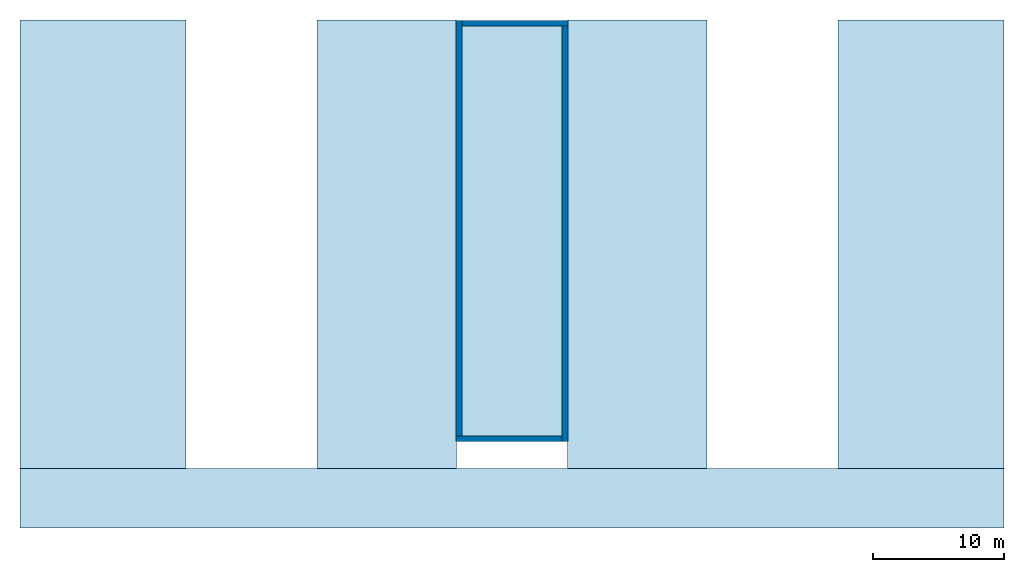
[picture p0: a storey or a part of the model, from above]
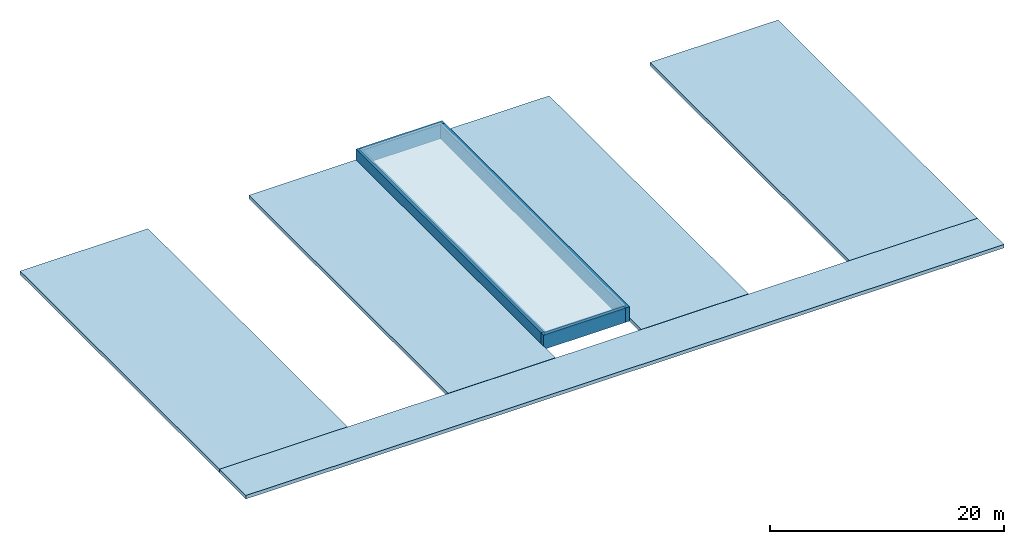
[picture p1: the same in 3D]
Properties of the parts of a building model (IFC2X3), part 1 of 3

# File
Description: ViewDefinition [CoordinationView_V2.0]
File name: Project Number
Time: 2020-09-23T11:52:34
Written by: The EXPRESS Data Manager Version 5.02.0100.07 : 28 Aug 2013
Made in: 21.0.0.383 - Exporter 21.0.0.383 - Alternate UI 21.0.0.383
Comment: STEP Physical File produced by: The EXPRESS Data Manager Version 5.02.0100.07 : 28 Aug 2013 * Module: EDMstepFileFactory/EDMstandAlone * Creation date: Wed Sep 23 11:52:34 2020 * Host: DESKTOP-DG8BND5 * Database: C:\Users\X\AppData\Local\Temp\ed47b6ea-077b-444b-8792-7ce0966b8367\b25919d0-d5f9-47cf-bf8c-4464f070ef61\ifc * Database version: 5507 * Database creation date: Wed Sep 23 11:42:41 2020 * Schema: IFC2X3 * Model: DataRepository.ifc * Model creation date: Wed Sep 23 11:42:42 2020 * Header model: DataRepository.ifc_HeaderModel * Header model creation date: Wed Sep 23 11:42:42 2020 * EDMuser: sdai-user * EDMgroup: sdai-group * License ID and type: 5605 : Permanent license. Expiry date: * EDMstepFileFactory options: 020000

# IfcProject, Project Number
LongName: Project Name; Phase: Project Status

# IfcSite, Default
RefLatitude: 48, 41, 46, 352233; RefLongitude: 6, 11, 34, 519615; RefElevation: 0 mm
Pset_ProductRequirements - Category: Project Information
Other - Category: Project Information; Client Name: Owner; Project Address: Enter address here; Project Issue Date: Issue Date; Project Name: Project Name; Project Number: Project Number; Project Status: Project Status

# IfcBuilding
Pset_BuildingCommon - NumberOfStoreys: 5
Pset_ProductRequirements - Category: Project Information
Other - Category: Project Information; Client Name: Owner; Project Address: Enter address here; Project Issue Date: Issue Date; Project Name: Project Name; Project Number: Project Number; Project Status: Project Status

# IfcBuildingStorey: Level:Circle Head - Project Datum (5)
Other(Type) - Category: Levels; Family Name: Level
Identity Data(Type) - Type Name: Circle Head - Project Datum
Graphics(Type) - Color: 0; Line Pattern: Centre; Line Weight: 1; Symbol: Anno_Level_Head_Circle: Standard; Symbol at End 1 Default: yes; Symbol at End 2 Default: no
Constraints(Type) - Elevation Base: Project Base Point
Pset_ProductRequirements - Category: Levels
Dimensions - Computation Height: 0 mm
Identity Data - Building Story: yes
Other - Category: Levels; Family: Level: Circle Head - Project Datum; Family and Type: Level: Circle Head - Project Datum; Type: Level: Circle Head - Project Datum; Type Id: Level: Circle Head - Project Datum
Name | LongName = Pset_AirSideSystemInformation, Name = Pset_ProductRequirements, Name = Identity Data, Name | Elevation (mm) = Constraints, Elevation (mm) | Structural
R-1 | R-1 | -3500 | yes
RDC | RDC | 0 | no
R+1 | R+1 | 3660 | no
R+2 | R+2 | 7320 | no
TOP | TOP | 11230 | no

# IfcBeam: M_Concrete-Rectangular Beam:200x300 mm, M_Concrete-Rectangular Beam:200x300 mm:497822
In: R-1
Type - Dimensions - b: 200 mm; h: 300 mm
Type - Identity Data - OmniClass Number: 23.25.30.11.14.14; OmniClass Title: Beams; Type Name: 200x300 mm
Type - Other - Category: Structural Framing; Family Name: M_Concrete-Rectangular Beam
Type - Structural - Section Shape: 0
Type - Pset_BeamCommon - IsExternal: no; LoadBearing: yes; Reference: 200x300 mm
Type - Pset_ProductRequirements - Category: Structural Framing
Type - Pset_QuantityTakeOff - Reference: 200x300 mm
Type - Pset_ReinforcementBarPitchOfBeam - Reference: 200x300 mm
Material: Concrete, Cast-in-Place gray
Pset_BeamCommon - Slope: 0 deg; Span: 1739.96 mm
Pset_QuantityTakeOff - sets with these values: 2
Constraints - Cross-Section Rotation: 0 deg; End Level Offset: 2330 mm; Reference Level: Level: R-1; Reference Level Elevation: -3500 mm; Start Level Offset: 2330 mm
Dimensions - Elevation at Bottom: -1470 mm; Elevation at Top: -1170 mm; Length: 1739.96 mm; Volume: 0.0989977 m3
Geometric Position - Join Status: Both joins enabled; y Justification: Origin; y Offset Value: 0 mm; yz Justification: Uniform; z Justification: Top; z Offset Value: 0 mm
Materials and Finishes - Structural Material: Concrete, Cast-in-Place gray
Other - Family: M_Concrete-Rectangular Beam: 200x300 mm; Family and Type: M_Concrete-Rectangular Beam: 200x300 mm; Type: M_Concrete-Rectangular Beam: 200x300 mm; Type Id: M_Concrete-Rectangular Beam: 200x300 mm
Phasing - Phase Created: New Construction
Structural - Enable Analytical Model: yes; Rebar Cover - Bottom Face: Rebar Cover Settings: Rebar Cover 1; Rebar Cover - Other Faces: Rebar Cover Settings: Rebar Cover 1; Rebar Cover - Top Face: Rebar Cover Settings: Rebar Cover 1; Cut Length: 1649.96 mm; Structural Usage: Secondary

# IfcBeam: M_Concrete-Rectangular Beam:400 x 800mm, M_Concrete-Rectangular Beam:400 x 800mm:545684
In: R+1
Type - PredefinedType: BEAM; Material: Concrete, Precast Smooth, Light Grey
Type - Dimensions - b: 430 mm; h: 430 mm
Type - Identity Data - OmniClass Number: 23.25.30.11.14.14; OmniClass Title: Beams; Type Name: 400 x 800mm
Type - Other - Category: Structural Framing; Family Name: M_Concrete-Rectangular Beam
Type - Structural - Section Shape: 0
Type - Pset_BeamCommon - IsExternal: no; LoadBearing: yes; Reference: 400 x 800mm
Type - Pset_ProductRequirements - Category: Structural Framing
Type - Pset_QuantityTakeOff - Reference: 400 x 800mm
Type - Pset_ReinforcementBarPitchOfBeam - Reference: 400 x 800mm
Pset_BeamCommon - Slope: 0 deg; Span: 31640 mm
Pset_QuantityTakeOff - sets with these values: 2
Constraints - Cross-Section Rotation: 0 deg; Reference Level: Level: R+1; End Level Offset: 0 mm; Orientation: Normal; Start Level Offset: 0 mm; Reference Level Elevation: 3660 mm; Work Plane: Level : R+1
Dimensions - Elevation at Bottom: 3230 mm; Elevation at Top: 3660 mm; Length: 31640 mm; Volume: 4.77689 m3
Geometric Position - Join Status: Both joins enabled; y Justification: Origin; y Offset Value: 0 mm; yz Justification: Uniform; z Justification: Top; z Offset Value: 0 mm
Materials and Finishes - Structural Material: Concrete, Precast Smooth, Light Grey
Other - Family: M_Concrete-Rectangular Beam: 400 x 800mm; Family and Type: M_Concrete-Rectangular Beam: 400 x 800mm; Type: M_Concrete-Rectangular Beam: 400 x 800mm; Type Id: M_Concrete-Rectangular Beam: 400 x 800mm
Phasing - Phase Created: Existing
Structural - Enable Analytical Model: yes; Rebar Cover - Bottom Face: Rebar Cover Settings: Rebar Cover 1; Rebar Cover - Other Faces: Rebar Cover Settings: Rebar Cover 1; Rebar Cover - Top Face: Rebar Cover Settings: Rebar Cover 1; Cut Length: 31425 mm; Structural Usage: Other

# IfcBeam: M_Concrete-Rectangular Beam:400 x 800mm (14)
In: R+1
Type - Dimensions - b: 430 mm; h: 430 mm
Type - Identity Data - OmniClass Number: 23.25.30.11.14.14; OmniClass Title: Beams; Type Name: 400 x 800mm
Type - Other - Category: Structural Framing; Family Name: M_Concrete-Rectangular Beam
Type - Structural - Section Shape: 0
Type - Pset_BeamCommon - IsExternal: no; LoadBearing: yes; Reference: 400 x 800mm
Type - Pset_ProductRequirements - Category: Structural Framing
Type - Pset_QuantityTakeOff - Reference: 400 x 800mm
Type - Pset_ReinforcementBarPitchOfBeam - Reference: 400 x 800mm
Material: Concrete, Precast Smooth, Light Grey
Pset_BeamCommon - Slope: 0 deg; Span: 4810 mm
Pset_QuantityTakeOff - sets with these values: 2
Constraints - Cross-Section Rotation: 0 deg; Reference Level: Level: R+1; End Level Offset: 0 mm; Orientation: Normal; Reference Level Elevation: 3660 mm; Start Level Offset: 0 mm; Work Plane: Level : R+1
Dimensions - Elevation at Bottom: 3230 mm; Elevation at Top: 3660 mm; Length: 4810 mm; Volume: 0.805166 m3
Geometric Position - Join Status: Both joins enabled; y Justification: Origin; y Offset Value: 0 mm; yz Justification: Uniform; z Justification: Top; z Offset Value: 0 mm
Materials and Finishes - Structural Material: Concrete, Precast Smooth, Light Grey
Other - Family: M_Concrete-Rectangular Beam: 400 x 800mm; Family and Type: M_Concrete-Rectangular Beam: 400 x 800mm; Type: M_Concrete-Rectangular Beam: 400 x 800mm; Type Id: M_Concrete-Rectangular Beam: 400 x 800mm
Phasing - Phase Created: Existing
Structural - Enable Analytical Model: yes; Rebar Cover - Bottom Face: Rebar Cover Settings: Rebar Cover 1; Rebar Cover - Other Faces: Rebar Cover Settings: Rebar Cover 1; Rebar Cover - Top Face: Rebar Cover Settings: Rebar Cover 1; End Attachment Type: End Elevation; Start Attachment Type: End Elevation; Structural Usage: Primary; Cut Length: 4354.6 mm
Name (M_Concrete-Rectangular Beam:400 x 800mm:...) | Comments
545226 | ThisIsExisting
545328 | ThisIsExisting
545407 | ThisIsExisting
545422 | ThisIsExisting
545442 | ThisIsExisting
545455 | ThisIsExisting
545468 | ThisIsExisting
545483 | ThisIsExisting
545496 | ThisIsExisting
545514 | ThisIsExisting
545534 | ThisIsExisting
545549 | ThisIsExisting
545629
545644

# IfcBeam: Poutre petite:Poutre petite (130)
Type - Identity Data - OmniClass Number: 23.25.30.11.14.14; OmniClass Title: Beams; Type Name: Poutre petite
Type - Other - Category: Structural Framing; Family Name: Poutre petite
Type - Structural - Section Shape: 0
Type - Pset_BeamCommon - IsExternal: no; LoadBearing: yes; Reference: Poutre petite
Type - Pset_ProductRequirements - Category: Structural Framing
Type - Pset_QuantityTakeOff - Reference: Poutre petite
Type - Pset_ReinforcementBarPitchOfBeam - Reference: Poutre petite
Material: Concrete, Precast Smooth, Light Grey
Pset_BeamCommon - Slope: 0 deg; Span: 2260 mm
Pset_QuantityTakeOff - sets with these values: 2
Constraints - Cross-Section Rotation: 0 deg; End Level Offset: 3530 mm; Start Level Offset: 3530 mm
Dimensions - Length: 2260 mm; Volume: 0.65021 m3
Geometric Position - End Extension: 0 mm; Join Status: Both joins enabled; Start Extension: 0 mm; y Justification: Origin; y Offset Value: 0 mm; yz Justification: Uniform; z Justification: Top; z Offset Value: 0 mm
Identity Data - Comments: ThisIsExisting
Materials and Finishes - Structural Material: Concrete - Precast Concrete
Other - Family: Poutre petite: Poutre petite; Family and Type: Poutre petite: Poutre petite; Type: Poutre petite: Poutre petite; Type Id: Poutre petite: Poutre petite
Phasing - Phase Created: Existing
Structural - Enable Analytical Model: yes; Rebar Cover - Bottom Face: Rebar Cover Settings: Rebar Cover 1; Rebar Cover - Other Faces: Rebar Cover Settings: Rebar Cover 1; Rebar Cover - Top Face: Rebar Cover Settings: Rebar Cover 1; Structural Usage: Primary; Cut Length: 2260 mm
Name (Poutre petite:Poutre petite:...) | In | Reference Level | Reference Level Elevation (mm) | Elevation at Bottom (mm) | Elevation at Top (mm) | Start Join Cutback (mm) | End Join Cutback (mm)
562425 | R+2 | Level: R+2 | 7320 | 10280 | 10850 | 12.7
562955 | R+2 | Level: R+2 | 7320 | 10280 | 10850 | 12.7 | 12.7
562975 | R+2 | Level: R+2 | 7320 | 10280 | 10850 | 12.7 | 12.7
562979 | R+2 | Level: R+2 | 7320 | 10280 | 10850 | 12.7 | 12.7
562983 | R+2 | Level: R+2 | 7320 | 10280 | 10850 | 12.7 | 12.7
562987 | R+2 | Level: R+2 | 7320 | 10280 | 10850 | 12.7 | 12.7
562991 | R+2 | Level: R+2 | 7320 | 10280 | 10850 | 12.7 | 12.7
562995 | R+2 | Level: R+2 | 7320 | 10280 | 10850 | 12.7 | 12.7
562999 | R+2 | Level: R+2 | 7320 | 10280 | 10850 | 12.7 | 12.7
563003 | R+2 | Level: R+2 | 7320 | 10280 | 10850 | 12.7 | 12.7
563007 | R+2 | Level: R+2 | 7320 | 10280 | 10850 | 12.7 | 12.7
563011 | R+2 | Level: R+2 | 7320 | 10280 | 10850 | 12.7 | 12.7
563015 | R+2 | Level: R+2 | 7320 | 10280 | 10850 | 12.7 | 12.7
563019 | R+2 | Level: R+2 | 7320 | 10280 | 10850 | 12.7 | 12.7
563023 | R+2 | Level: R+2 | 7320 | 10280 | 10850 | 12.7 | 12.7
563027 | R+2 | Level: R+2 | 7320 | 10280 | 10850 | 12.7 | 12.7
563031 | R+2 | Level: R+2 | 7320 | 10280 | 10850 |  | 12.7
563098 | R+2 | Level: R+2 | 7320 | 10280 | 10850 | 12.7
563100 | R+2 | Level: R+2 | 7320 | 10280 | 10850 | 12.7 | 12.7
563102 | R+2 | Level: R+2 | 7320 | 10280 | 10850 | 12.7 | 12.7
563104 | R+2 | Level: R+2 | 7320 | 10280 | 10850 | 12.7 | 12.7
563106 | R+2 | Level: R+2 | 7320 | 10280 | 10850 | 12.7 | 12.7
563108 | R+2 | Level: R+2 | 7320 | 10280 | 10850 | 12.7 | 12.7
563110 | R+2 | Level: R+2 | 7320 | 10280 | 10850 | 12.7 | 12.7
563112 | R+2 | Level: R+2 | 7320 | 10280 | 10850 | 12.7 | 12.7
563114 | R+2 | Level: R+2 | 7320 | 10280 | 10850 | 12.7 | 12.7
563116 | R+2 | Level: R+2 | 7320 | 10280 | 10850 | 12.7 | 12.7
563118 | R+2 | Level: R+2 | 7320 | 10280 | 10850 | 12.7 | 12.7
563120 | R+2 | Level: R+2 | 7320 | 10280 | 10850 | 12.7 | 12.7
563122 | R+2 | Level: R+2 | 7320 | 10280 | 10850 | 12.7 | 12.7
563124 | R+2 | Level: R+2 | 7320 | 10280 | 10850 | 12.7 | 12.7
563126 | R+2 | Level: R+2 | 7320 | 10280 | 10850 | 12.7 | 12.7
563128 | R+2 | Level: R+2 | 7320 | 10280 | 10850 | 12.7 | 12.7
563130 | R+2 | Level: R+2 | 7320 | 10280 | 10850 |  | 12.7
563202 | RDC | Level: RDC | 0 | 2960 | 3530 | 12.7
563204 | RDC | Level: RDC | 0 | 2960 | 3530 | 12.7 | 12.7
563206 | RDC | Level: RDC | 0 | 2960 | 3530 | 12.7 | 12.7
563208 | RDC | Level: RDC | 0 | 2960 | 3530 | 12.7 | 12.7
563210 | RDC | Level: RDC | 0 | 2960 | 3530 | 12.7 | 12.7
563212 | RDC | Level: RDC | 0 | 2960 | 3530 | 12.7 | 12.7
563214 | RDC | Level: RDC | 0 | 2960 | 3530 | 12.7 | 12.7
563216 | RDC | Level: RDC | 0 | 2960 | 3530 | 12.7 | 12.7
563218 | RDC | Level: RDC | 0 | 2960 | 3530 | 12.7 | 12.7
563220 | RDC | Level: RDC | 0 | 2960 | 3530 | 12.7 | 12.7
563222 | RDC | Level: RDC | 0 | 2960 | 3530 | 12.7 | 12.7
563224 | RDC | Level: RDC | 0 | 2960 | 3530 | 12.7 | 12.7
563226 | RDC | Level: RDC | 0 | 2960 | 3530 | 12.7 | 12.7
563228 | RDC | Level: RDC | 0 | 2960 | 3530 | 12.7 | 12.7
563230 | RDC | Level: RDC | 0 | 2960 | 3530 | 12.7 | 12.7
563232 | RDC | Level: RDC | 0 | 2960 | 3530 | 12.7 | 12.7
563234 | RDC | Level: RDC | 0 | 2960 | 3530 | 12.7 | 12.7
563236 | RDC | Level: RDC | 0 | 2960 | 3530 | 12.7
563238 | RDC | Level: RDC | 0 | 2960 | 3530 | 12.7 | 12.7
563240 | RDC | Level: RDC | 0 | 2960 | 3530 | 12.7 | 12.7
563242 | RDC | Level: RDC | 0 | 2960 | 3530 | 12.7 | 12.7
563244 | RDC | Level: RDC | 0 | 2960 | 3530 | 12.7 | 12.7
563246 | RDC | Level: RDC | 0 | 2960 | 3530 | 12.7 | 12.7
563248 | RDC | Level: RDC | 0 | 2960 | 3530 | 12.7 | 12.7
563250 | RDC | Level: RDC | 0 | 2960 | 3530 | 12.7 | 12.7
563252 | RDC | Level: RDC | 0 | 2960 | 3530 | 12.7 | 12.7
563254 | RDC | Level: RDC | 0 | 2960 | 3530 | 12.7 | 12.7
563256 | RDC | Level: RDC | 0 | 2960 | 3530 | 12.7 | 12.7
563258 | RDC | Level: RDC | 0 | 2960 | 3530 | 12.7 | 12.7
563260 | RDC | Level: RDC | 0 | 2960 | 3530 | 12.7 | 12.7
563262 | RDC | Level: RDC | 0 | 2960 | 3530 | 12.7 | 12.7
563264 | RDC | Level: RDC | 0 | 2960 | 3530 | 12.7 | 12.7
563266 | RDC | Level: RDC | 0 | 2960 | 3530 | 12.7 | 12.7
563268 | RDC | Level: RDC | 0 | 2960 | 3530 |  | 12.7
563583 | R+1 | Level: R+1 | 3660 | 6620 | 7190 | 12.7
563585 | R+1 | Level: R+1 | 3660 | 6620 | 7190 | 12.7 | 12.7
563587 | R+1 | Level: R+1 | 3660 | 6620 | 7190 | 12.7 | 12.7
563589 | R+1 | Level: R+1 | 3660 | 6620 | 7190 | 12.7 | 12.7
563591 | R+1 | Level: R+1 | 3660 | 6620 | 7190 | 12.7 | 12.7
563593 | R+1 | Level: R+1 | 3660 | 6620 | 7190 | 12.7 | 12.7
563595 | R+1 | Level: R+1 | 3660 | 6620 | 7190 | 12.7 | 12.7
563597 | R+1 | Level: R+1 | 3660 | 6620 | 7190 | 12.7 | 12.7
563599 | R+1 | Level: R+1 | 3660 | 6620 | 7190 | 12.7 | 12.7
563601 | R+1 | Level: R+1 | 3660 | 6620 | 7190 | 12.7 | 12.7
563603 | R+1 | Level: R+1 | 3660 | 6620 | 7190 | 12.7 | 12.7
563605 | R+1 | Level: R+1 | 3660 | 6620 | 7190 | 12.7 | 12.7
563607 | R+1 | Level: R+1 | 3660 | 6620 | 7190 | 12.7 | 12.7
563609 | R+1 | Level: R+1 | 3660 | 6620 | 7190 | 12.7 | 12.7
563611 | R+1 | Level: R+1 | 3660 | 6620 | 7190 | 12.7 | 12.7
563613 | R+1 | Level: R+1 | 3660 | 6620 | 7190 | 12.7 | 12.7
563615 | R+1 | Level: R+1 | 3660 | 6620 | 7190 |  | 12.7
563617 | R+1 | Level: R+1 | 3660 | 6620 | 7190 | 12.7
563619 | R+1 | Level: R+1 | 3660 | 6620 | 7190 | 12.7 | 12.7
563621 | R+1 | Level: R+1 | 3660 | 6620 | 7190 | 12.7 | 12.7
563623 | R+1 | Level: R+1 | 3660 | 6620 | 7190 | 12.7 | 12.7
563625 | R+1 | Level: R+1 | 3660 | 6620 | 7190 | 12.7 | 12.7
563627 | R+1 | Level: R+1 | 3660 | 6620 | 7190 | 12.7 | 12.7
563629 | R+1 | Level: R+1 | 3660 | 6620 | 7190 | 12.7 | 12.7
563631 | R+1 | Level: R+1 | 3660 | 6620 | 7190 | 12.7 | 12.7
563633 | R+1 | Level: R+1 | 3660 | 6620 | 7190 | 12.7 | 12.7
563635 | R+1 | Level: R+1 | 3660 | 6620 | 7190 | 12.7 | 12.7
563637 | R+1 | Level: R+1 | 3660 | 6620 | 7190 | 12.7 | 12.7
563639 | R+1 | Level: R+1 | 3660 | 6620 | 7190 | 12.7 | 12.7
563641 | R+1 | Level: R+1 | 3660 | 6620 | 7190 | 12.7 | 12.7
563643 | R+1 | Level: R+1 | 3660 | 6620 | 7190 | 12.7 | 12.7
563645 | R+1 | Level: R+1 | 3660 | 6620 | 7190 | 12.7 | 12.7
563647 | R+1 | Level: R+1 | 3660 | 6620 | 7190 | 12.7 | 12.7
563649 | R+1 | Level: R+1 | 3660 | 6620 | 7190 |  | 12.7
564461 | R+2 | Level: R+2 | 7320 | 10280 | 10850 | 12.7
564463 | R+2 | Level: R+2 | 7320 | 10280 | 10850 | 12.7 | 12.7
564465 | R+2 | Level: R+2 | 7320 | 10280 | 10850 | 12.7 | 12.7
564467 | R+2 | Level: R+2 | 7320 | 10280 | 10850 | 12.7 | 12.7
564469 | R+2 | Level: R+2 | 7320 | 10280 | 10850 | 12.7 | 12.7
564471 | R+2 | Level: R+2 | 7320 | 10280 | 10850 | 12.7 | 12.7
564473 | R+2 | Level: R+2 | 7320 | 10280 | 10850 | 12.7 | 12.7
564475 | R+2 | Level: R+2 | 7320 | 10280 | 10850 | 12.7 | 12.7
564477 | R+2 | Level: R+2 | 7320 | 10280 | 10850 | 12.7 | 12.7
564479 | R+2 | Level: R+2 | 7320 | 10280 | 10850 | 12.7 | 12.7
564481 | R+2 | Level: R+2 | 7320 | 10280 | 10850 | 12.7 | 12.7
564483 | R+2 | Level: R+2 | 7320 | 10280 | 10850 | 12.7 | 12.7
564485 | R+2 | Level: R+2 | 7320 | 10280 | 10850 | 12.7 | 12.7
564487 | R+2 | Level: R+2 | 7320 | 10280 | 10850 |  | 12.7
565113 | R+2 | Level: R+2 | 7320 | 10280 | 10850 | 12.7
565115 | R+2 | Level: R+2 | 7320 | 10280 | 10850 | 12.7 | 12.7
565117 | R+2 | Level: R+2 | 7320 | 10280 | 10850 | 12.7 | 12.7
565119 | R+2 | Level: R+2 | 7320 | 10280 | 10850 | 12.7 | 12.7
565121 | R+2 | Level: R+2 | 7320 | 10280 | 10850 | 12.7 | 12.7
565123 | R+2 | Level: R+2 | 7320 | 10280 | 10850 | 12.7 | 12.7
565125 | R+2 | Level: R+2 | 7320 | 10280 | 10850 | 12.7 | 12.7
565127 | R+2 | Level: R+2 | 7320 | 10280 | 10850 | 12.7 | 12.7
565129 | R+2 | Level: R+2 | 7320 | 10280 | 10850 | 12.7 | 12.7
565131 | R+2 | Level: R+2 | 7320 | 10280 | 10850 | 12.7 | 12.7
565133 | R+2 | Level: R+2 | 7320 | 10280 | 10850 | 12.7 | 12.7
565135 | R+2 | Level: R+2 | 7320 | 10280 | 10850 | 12.7 | 12.7
565137 | R+2 | Level: R+2 | 7320 | 10280 | 10850 | 12.7 | 12.7
565139 | R+2 | Level: R+2 | 7320 | 10280 | 10850 |  | 12.7

# IfcBeam: Poutres:Poutres 2 (215)
Type - PredefinedType: BEAM; Material: Concrete, Precast Smooth, Light Grey
Type - Identity Data - OmniClass Number: 23.25.30.11.14.14; OmniClass Title: Beams; Type Name: Poutres 2
Type - Other - Category: Structural Framing; Family Name: Poutres
Type - Structural - Section Shape: 0
Type - Pset_BeamCommon - IsExternal: no; LoadBearing: yes; Reference: Poutres 2
Type - Pset_ProductRequirements - Category: Structural Framing
Type - Pset_QuantityTakeOff - Reference: Poutres 2
Type - Pset_ReinforcementBarPitchOfBeam - Reference: Poutres 2
Pset_BeamCommon - Span: 10380 mm; Slope: 0 deg
Pset_QuantityTakeOff - sets with these values: 2
Constraints - Cross-Section Rotation: 0 deg; End Level Offset: 3530 mm; Start Level Offset: 3530 mm
Dimensions - Length: 10380 mm; Volume: 5.47672 m3
Geometric Position - End Extension: 0 mm; Join Status: Both joins enabled; Start Extension: 0 mm; y Justification: Origin; y Offset Value: 0 mm; yz Justification: Uniform; z Justification: Top; z Offset Value: 0 mm
Identity Data - Comments: ThisIsExisting
Materials and Finishes - Structural Material: Concrete, Precast Smooth, Light Grey
Other - Family: Poutres: Poutres 2; Family and Type: Poutres: Poutres 2; Type: Poutres: Poutres 2; Type Id: Poutres: Poutres 2
Phasing - Phase Created: Existing
Structural - Enable Analytical Model: yes; Rebar Cover - Bottom Face: Rebar Cover Settings: Rebar Cover 1; Rebar Cover - Other Faces: Rebar Cover Settings: Rebar Cover 1; Rebar Cover - Top Face: Rebar Cover Settings: Rebar Cover 1; Cut Length: 10380 mm; End Attachment Type: End Elevation; Start Attachment Type: End Elevation; Structural Usage: Primary
Name (Poutres:Poutres 2:...) | In | Reference Level | Reference Level Elevation (mm) | Elevation at Bottom (mm) | Elevation at Top (mm) | End Join Cutback (mm) = Start Join Cutback (mm)
442840 | RDC | Level: RDC | 0 | 2960 | 3530 | 12.7
443948 | RDC | Level: RDC | 0 | 2960 | 3530 | 12.7
443968 | RDC | Level: RDC | 0 | 2960 | 3530 | 12.7
443972 | RDC | Level: RDC | 0 | 2960 | 3530 | 12.7
443976 | RDC | Level: RDC | 0 | 2960 | 3530 | 12.7
443980 | RDC | Level: RDC | 0 | 2960 | 3530 | 12.7
443984 | RDC | Level: RDC | 0 | 2960 | 3530 | 12.7
443988 | RDC | Level: RDC | 0 | 2960 | 3530 | 12.7
443992 | RDC | Level: RDC | 0 | 2960 | 3530 | 12.7
443996 | RDC | Level: RDC | 0 | 2960 | 3530 | 12.7
444000 | RDC | Level: RDC | 0 | 2960 | 3530 | 12.7
444004 | RDC | Level: RDC | 0 | 2960 | 3530 | 12.7
444008 | RDC | Level: RDC | 0 | 2960 | 3530 | 12.7
444012 | RDC | Level: RDC | 0 | 2960 | 3530 | 12.7
444016 | RDC | Level: RDC | 0 | 2960 | 3530 | 12.7
444020 | RDC | Level: RDC | 0 | 2960 | 3530 | 12.7
444024 | RDC | Level: RDC | 0 | 2960 | 3530 | 12.7
444092 | R+1 | Level: R+1 | 3660 | 6620 | 7190 | 12.7
444095 | R+1 | Level: R+1 | 3660 | 6620 | 7190 | 12.7
444098 | R+1 | Level: R+1 | 3660 | 6620 | 7190 | 12.7
444101 | R+1 | Level: R+1 | 3660 | 6620 | 7190 | 12.7
444104 | R+1 | Level: R+1 | 3660 | 6620 | 7190 | 12.7
444107 | R+1 | Level: R+1 | 3660 | 6620 | 7190 | 12.7
444110 | R+1 | Level: R+1 | 3660 | 6620 | 7190 | 12.7
444113 | R+1 | Level: R+1 | 3660 | 6620 | 7190 | 12.7
444116 | R+1 | Level: R+1 | 3660 | 6620 | 7190 | 12.7
444119 | R+1 | Level: R+1 | 3660 | 6620 | 7190 | 12.7
444122 | R+1 | Level: R+1 | 3660 | 6620 | 7190 | 12.7
444125 | R+1 | Level: R+1 | 3660 | 6620 | 7190 | 12.7
444128 | R+1 | Level: R+1 | 3660 | 6620 | 7190 | 12.7
444131 | R+1 | Level: R+1 | 3660 | 6620 | 7190 | 12.7
444134 | R+1 | Level: R+1 | 3660 | 6620 | 7190 | 12.7
444137 | R+1 | Level: R+1 | 3660 | 6620 | 7190 | 12.7
444140 | R+1 | Level: R+1 | 3660 | 6620 | 7190 | 12.7
444212 | R+2 | Level: R+2 | 7320 | 10280 | 10850 | 12.7
444215 | R+2 | Level: R+2 | 7320 | 10280 | 10850 | 12.7
444218 | R+2 | Level: R+2 | 7320 | 10280 | 10850 | 12.7
444221 | R+2 | Level: R+2 | 7320 | 10280 | 10850 | 12.7
444224 | R+2 | Level: R+2 | 7320 | 10280 | 10850 | 12.7
444227 | R+2 | Level: R+2 | 7320 | 10280 | 10850 | 12.7
444230 | R+2 | Level: R+2 | 7320 | 10280 | 10850 | 12.7
444233 | R+2 | Level: R+2 | 7320 | 10280 | 10850 | 12.7
444236 | R+2 | Level: R+2 | 7320 | 10280 | 10850 | 12.7
444239 | R+2 | Level: R+2 | 7320 | 10280 | 10850 | 12.7
444242 | R+2 | Level: R+2 | 7320 | 10280 | 10850 | 12.7
444245 | R+2 | Level: R+2 | 7320 | 10280 | 10850 | 12.7
444248 | R+2 | Level: R+2 | 7320 | 10280 | 10850 | 12.7
444251 | R+2 | Level: R+2 | 7320 | 10280 | 10850 | 12.7
444254 | R+2 | Level: R+2 | 7320 | 10280 | 10850 | 12.7
444257 | R+2 | Level: R+2 | 7320 | 10280 | 10850 | 12.7
444260 | R+2 | Level: R+2 | 7320 | 10280 | 10850 | 12.7
448041 | RDC | Level: RDC | 0 | 2960 | 3530 | 12.7
448044 | RDC | Level: RDC | 0 | 2960 | 3530 | 12.7
448051 | RDC | Level: RDC | 0 | 2960 | 3530 | 12.7
448054 | RDC | Level: RDC | 0 | 2960 | 3530 | 12.7
448057 | RDC | Level: RDC | 0 | 2960 | 3530 | 12.7
448060 | RDC | Level: RDC | 0 | 2960 | 3530 | 12.7
448063 | RDC | Level: RDC | 0 | 2960 | 3530 | 12.7
448066 | RDC | Level: RDC | 0 | 2960 | 3530 | 12.7
448069 | RDC | Level: RDC | 0 | 2960 | 3530 | 12.7
448072 | RDC | Level: RDC | 0 | 2960 | 3530 | 12.7
448075 | RDC | Level: RDC | 0 | 2960 | 3530 | 12.7
448078 | RDC | Level: RDC | 0 | 2960 | 3530 | 12.7
448081 | RDC | Level: RDC | 0 | 2960 | 3530 | 12.7
448084 | RDC | Level: RDC | 0 | 2960 | 3530 | 12.7
448087 | RDC | Level: RDC | 0 | 2960 | 3530 | 12.7
448199 | RDC | Level: RDC | 0 | 2960 | 3530 | 12.7
448202 | RDC | Level: RDC | 0 | 2960 | 3530 | 12.7
448209 | RDC | Level: RDC | 0 | 2960 | 3530 | 12.7
448212 | RDC | Level: RDC | 0 | 2960 | 3530 | 12.7
448215 | RDC | Level: RDC | 0 | 2960 | 3530 | 12.7
448218 | RDC | Level: RDC | 0 | 2960 | 3530 | 12.7
448221 | RDC | Level: RDC | 0 | 2960 | 3530 | 12.7
448224 | RDC | Level: RDC | 0 | 2960 | 3530 | 12.7
448227 | RDC | Level: RDC | 0 | 2960 | 3530 | 12.7
448230 | RDC | Level: RDC | 0 | 2960 | 3530 | 12.7
448233 | RDC | Level: RDC | 0 | 2960 | 3530 | 12.7
448236 | RDC | Level: RDC | 0 | 2960 | 3530 | 12.7
448239 | RDC | Level: RDC | 0 | 2960 | 3530 | 12.7
448242 | RDC | Level: RDC | 0 | 2960 | 3530 | 12.7
448245 | RDC | Level: RDC | 0 | 2960 | 3530 | 12.7
448339 | R+1 | Level: R+1 | 3660 | 6620 | 7190 | 12.7
448342 | R+1 | Level: R+1 | 3660 | 6620 | 7190 | 12.7
448345 | R+1 | Level: R+1 | 3660 | 6620 | 7190 | 12.7
448348 | R+1 | Level: R+1 | 3660 | 6620 | 7190 | 12.7
448351 | R+1 | Level: R+1 | 3660 | 6620 | 7190 | 12.7
448354 | R+1 | Level: R+1 | 3660 | 6620 | 7190 | 12.7
448357 | R+1 | Level: R+1 | 3660 | 6620 | 7190 | 12.7
448360 | R+1 | Level: R+1 | 3660 | 6620 | 7190 | 12.7
448363 | R+1 | Level: R+1 | 3660 | 6620 | 7190 | 12.7
448366 | R+1 | Level: R+1 | 3660 | 6620 | 7190 | 12.7
448369 | R+1 | Level: R+1 | 3660 | 6620 | 7190 | 12.7
448372 | R+1 | Level: R+1 | 3660 | 6620 | 7190 | 12.7
448375 | R+1 | Level: R+1 | 3660 | 6620 | 7190 | 12.7
448378 | R+1 | Level: R+1 | 3660 | 6620 | 7190 | 12.7
448381 | R+1 | Level: R+1 | 3660 | 6620 | 7190 | 12.7
448591 | R+2 | Level: R+2 | 7320 | 10280 | 10850 | 12.7
448594 | R+2 | Level: R+2 | 7320 | 10280 | 10850 | 12.7
448597 | R+2 | Level: R+2 | 7320 | 10280 | 10850 | 12.7
448600 | R+2 | Level: R+2 | 7320 | 10280 | 10850 | 12.7
448603 | R+2 | Level: R+2 | 7320 | 10280 | 10850 | 12.7
448606 | R+2 | Level: R+2 | 7320 | 10280 | 10850 | 12.7
448609 | R+2 | Level: R+2 | 7320 | 10280 | 10850 | 12.7
448612 | R+2 | Level: R+2 | 7320 | 10280 | 10850 | 12.7
448615 | R+2 | Level: R+2 | 7320 | 10280 | 10850 | 12.7
448618 | R+2 | Level: R+2 | 7320 | 10280 | 10850 | 12.7
448621 | R+2 | Level: R+2 | 7320 | 10280 | 10850 | 12.7
448624 | R+2 | Level: R+2 | 7320 | 10280 | 10850 | 12.7
448627 | R+2 | Level: R+2 | 7320 | 10280 | 10850 | 12.7
448630 | R+2 | Level: R+2 | 7320 | 10280 | 10850 | 12.7
448633 | R+2 | Level: R+2 | 7320 | 10280 | 10850 | 12.7
487352 | RDC | Level: RDC | 0 | 2960 | 3530 | 12.7
487355 | RDC | Level: RDC | 0 | 2960 | 3530 | 12.7
487358 | RDC | Level: RDC | 0 | 2960 | 3530 | 12.7
487361 | RDC | Level: RDC | 0 | 2960 | 3530 | 12.7
487364 | RDC | Level: RDC | 0 | 2960 | 3530 | 12.7
487367 | RDC | Level: RDC | 0 | 2960 | 3530 | 12.7
487370 | RDC | Level: RDC | 0 | 2960 | 3530 | 12.7
487373 | RDC | Level: RDC | 0 | 2960 | 3530 | 12.7
487376 | RDC | Level: RDC | 0 | 2960 | 3530 | 12.7
487379 | RDC | Level: RDC | 0 | 2960 | 3530 | 12.7
487382 | RDC | Level: RDC | 0 | 2960 | 3530 | 12.7
487385 | RDC | Level: RDC | 0 | 2960 | 3530 | 12.7
487388 | RDC | Level: RDC | 0 | 2960 | 3530 | 12.7
487391 | RDC | Level: RDC | 0 | 2960 | 3530 | 12.7
487394 | RDC | Level: RDC | 0 | 2960 | 3530 | 12.7
487397 | RDC | Level: RDC | 0 | 2960 | 3530 | 12.7
487406 | R+2 | Level: R+2 | 7320 | 10280 | 10850 | 12.7
487409 | R+2 | Level: R+2 | 7320 | 10280 | 10850 | 12.7
487412 | R+2 | Level: R+2 | 7320 | 10280 | 10850 | 12.7
487415 | R+2 | Level: R+2 | 7320 | 10280 | 10850 | 12.7
487418 | R+2 | Level: R+2 | 7320 | 10280 | 10850 | 12.7
487421 | R+2 | Level: R+2 | 7320 | 10280 | 10850 | 12.7
487424 | R+2 | Level: R+2 | 7320 | 10280 | 10850 | 12.7
487427 | R+2 | Level: R+2 | 7320 | 10280 | 10850 | 12.7
487430 | R+2 | Level: R+2 | 7320 | 10280 | 10850 | 12.7
487433 | R+2 | Level: R+2 | 7320 | 10280 | 10850 | 12.7
487436 | R+2 | Level: R+2 | 7320 | 10280 | 10850 | 12.7
487439 | R+2 | Level: R+2 | 7320 | 10280 | 10850 | 12.7
487442 | R+2 | Level: R+2 | 7320 | 10280 | 10850 | 12.7
487445 | R+2 | Level: R+2 | 7320 | 10280 | 10850 | 12.7
487448 | R+2 | Level: R+2 | 7320 | 10280 | 10850 | 12.7
487451 | R+2 | Level: R+2 | 7320 | 10280 | 10850 | 12.7
487457 | RDC | Level: RDC | 0 | 2960 | 3530 | 12.7
487460 | RDC | Level: RDC | 0 | 2960 | 3530 | 12.7
487463 | RDC | Level: RDC | 0 | 2960 | 3530 | 12.7
487466 | RDC | Level: RDC | 0 | 2960 | 3530 | 12.7
487469 | RDC | Level: RDC | 0 | 2960 | 3530 | 12.7
487472 | RDC | Level: RDC | 0 | 2960 | 3530 | 12.7
487475 | RDC | Level: RDC | 0 | 2960 | 3530 | 12.7
487478 | RDC | Level: RDC | 0 | 2960 | 3530 | 12.7
487481 | RDC | Level: RDC | 0 | 2960 | 3530 | 12.7
487484 | RDC | Level: RDC | 0 | 2960 | 3530 | 12.7
487487 | RDC | Level: RDC | 0 | 2960 | 3530 | 12.7
487490 | RDC | Level: RDC | 0 | 2960 | 3530 | 12.7
487493 | RDC | Level: RDC | 0 | 2960 | 3530 | 12.7
487496 | RDC | Level: RDC | 0 | 2960 | 3530 | 12.7
487502 | RDC | Level: RDC | 0 | 2960 | 3530 | 12.7
487505 | RDC | Level: RDC | 0 | 2960 | 3530 | 12.7
487508 | RDC | Level: RDC | 0 | 2960 | 3530 | 12.7
487511 | RDC | Level: RDC | 0 | 2960 | 3530 | 12.7
487514 | RDC | Level: RDC | 0 | 2960 | 3530 | 12.7
487517 | RDC | Level: RDC | 0 | 2960 | 3530 | 12.7
487520 | RDC | Level: RDC | 0 | 2960 | 3530 | 12.7
487523 | RDC | Level: RDC | 0 | 2960 | 3530 | 12.7
487526 | RDC | Level: RDC | 0 | 2960 | 3530 | 12.7
487529 | RDC | Level: RDC | 0 | 2960 | 3530 | 12.7
487532 | RDC | Level: RDC | 0 | 2960 | 3530 | 12.7
487535 | RDC | Level: RDC | 0 | 2960 | 3530 | 12.7
487538 | RDC | Level: RDC | 0 | 2960 | 3530 | 12.7
487541 | RDC | Level: RDC | 0 | 2960 | 3530 | 12.7
487547 | R+1 | Level: R+1 | 3660 | 6620 | 7190 | 12.7
487550 | R+1 | Level: R+1 | 3660 | 6620 | 7190 | 12.7
487553 | R+1 | Level: R+1 | 3660 | 6620 | 7190 | 12.7
487556 | R+1 | Level: R+1 | 3660 | 6620 | 7190 | 12.7
487559 | R+1 | Level: R+1 | 3660 | 6620 | 7190 | 12.7
487562 | R+1 | Level: R+1 | 3660 | 6620 | 7190 | 12.7
487565 | R+1 | Level: R+1 | 3660 | 6620 | 7190 | 12.7
487568 | R+1 | Level: R+1 | 3660 | 6620 | 7190 | 12.7
487571 | R+1 | Level: R+1 | 3660 | 6620 | 7190 | 12.7
487574 | R+1 | Level: R+1 | 3660 | 6620 | 7190 | 12.7
487577 | R+1 | Level: R+1 | 3660 | 6620 | 7190 | 12.7
487580 | R+1 | Level: R+1 | 3660 | 6620 | 7190 | 12.7
487583 | R+1 | Level: R+1 | 3660 | 6620 | 7190 | 12.7
487586 | R+1 | Level: R+1 | 3660 | 6620 | 7190 | 12.7
487592 | R+2 | Level: R+2 | 7320 | 10280 | 10850 | 0
487595 | R+2 | Level: R+2 | 7320 | 10280 | 10850 | 12.7
487598 | R+2 | Level: R+2 | 7320 | 10280 | 10850 | 12.7
487601 | R+2 | Level: R+2 | 7320 | 10280 | 10850 | 12.7
487604 | R+2 | Level: R+2 | 7320 | 10280 | 10850 | 12.7
487607 | R+2 | Level: R+2 | 7320 | 10280 | 10850 | 12.7
487610 | R+2 | Level: R+2 | 7320 | 10280 | 10850 | 12.7
487613 | R+2 | Level: R+2 | 7320 | 10280 | 10850 | 12.7
487616 | R+2 | Level: R+2 | 7320 | 10280 | 10850 | 12.7
487619 | R+2 | Level: R+2 | 7320 | 10280 | 10850 | 12.7
487622 | R+2 | Level: R+2 | 7320 | 10280 | 10850 | 12.7
487625 | R+2 | Level: R+2 | 7320 | 10280 | 10850 | 12.7
487628 | R+2 | Level: R+2 | 7320 | 10280 | 10850 | 12.7
487631 | R+2 | Level: R+2 | 7320 | 10280 | 10850 | 12.7
488253 | R+1 | Level: R+1 | 3660 | 6620 | 7190 | 12.7
488255 | R+1 | Level: R+1 | 3660 | 6620 | 7190 | 12.7
488257 | R+1 | Level: R+1 | 3660 | 6620 | 7190 | 12.7
488259 | R+1 | Level: R+1 | 3660 | 6620 | 7190 | 12.7
488261 | R+1 | Level: R+1 | 3660 | 6620 | 7190 | 12.7
488263 | R+1 | Level: R+1 | 3660 | 6620 | 7190 | 12.7
488265 | R+1 | Level: R+1 | 3660 | 6620 | 7190 | 12.7
488267 | R+1 | Level: R+1 | 3660 | 6620 | 7190 | 12.7
488269 | R+1 | Level: R+1 | 3660 | 6620 | 7190 | 12.7
488271 | R+1 | Level: R+1 | 3660 | 6620 | 7190 | 12.7
488273 | R+1 | Level: R+1 | 3660 | 6620 | 7190 | 12.7
488275 | R+1 | Level: R+1 | 3660 | 6620 | 7190 | 12.7
488277 | R+1 | Level: R+1 | 3660 | 6620 | 7190 | 12.7
488279 | R+1 | Level: R+1 | 3660 | 6620 | 7190 | 12.7
488281 | R+1 | Level: R+1 | 3660 | 6620 | 7190 | 12.7
488283 | R+1 | Level: R+1 | 3660 | 6620 | 7190 | 12.7

# IfcColumn: M_Concrete-Round-Column:750mm (3)
In: R-1
Type - PredefinedType: COLUMN; Material: Concrete, Precast Smooth, Light Grey
Type - Dimensions - b: 750 mm
Type - Identity Data - OmniClass Number: 23.25.30.11.14.11; OmniClass Title: Columns; Type Name: 750mm
Type - Other - Category: Structural Columns; Family Name: M_Concrete-Round-Column
Type - Structural - Section Shape: 0
Type - Pset_ColumnCommon - IsExternal: no; LoadBearing: yes; Reference: 750mm
Type - Pset_ProductRequirements - Category: Structural Columns
Type - Pset_QuantityTakeOff - Reference: 750mm
Type - Pset_ReinforcementBarPitchOfColumn - Reference: 750mm
Pset_QuantityTakeOff - sets with these values: 2
Constraints - Base Level: Level: R-1; Column Style: Vertical; Level: Level: R-1; Moves With Grids: yes; Room Bounding: yes; Top Offset: 0 mm; Base Offset: 0 mm; Top Level: Level: TOITURE
Dimensions - Length: 14340 mm; Volume: 6.33512 m3
Materials and Finishes - Structural Material: Concrete, Precast Smooth, Light Grey
Other - Family: M_Concrete-Round-Column: 750mm; Family and Type: M_Concrete-Round-Column: 750mm; Type: M_Concrete-Round-Column: 750mm; Type Id: M_Concrete-Round-Column: 750mm
Phasing - Phase Created: Existing
Structural - Enable Analytical Model: yes; Rebar Cover - Bottom Face: Rebar Cover Settings: Rebar Cover 1; Rebar Cover - Other Faces: Rebar Cover Settings: Rebar Cover 1; Rebar Cover - Top Face: Rebar Cover Settings: Rebar Cover 1
Name (M_Concrete-Round-Column:750mm:...) | Column Location Mark
392007 | E(-928.4)-18(2173.4)
392240 | 18(2173.4)-20 | Identity Data - Comments: ThisIsExisting
392312 | 18(2173.4)-20(5163.4)

# IfcColumn: M_Precast-Rectangular Column:430X200 (2)
Type - PredefinedType: COLUMN; Material: Concrete - Precast Concrete - 35 MPa
Type - Dimensions - b: 430 mm; Chamfer: 25 mm; h: 200 mm
Type - Identity Data - OmniClass Number: 23.25.30.11.14.11; OmniClass Title: Columns; Type Name: 430X200
Type - Other - Category: Structural Columns; Family Name: M_Precast-Rectangular Column
Type - Structural - Section Shape: 0
Type - Pset_ColumnCommon - IsExternal: no; LoadBearing: yes; Reference: 430X200
Type - Pset_ProductRequirements - Category: Structural Columns
Type - Pset_QuantityTakeOff - Reference: 430X200
Type - Pset_ReinforcementBarPitchOfColumn - Reference: 430X200
Pset_QuantityTakeOff - sets with these values: 2
Constraints - Column Style: Vertical; Moves With Grids: yes; Room Bounding: yes
Materials and Finishes - Structural Material: Concrete - Precast Concrete - 35 MPa
Other - Family: M_Precast-Rectangular Column: 430X200; Family and Type: M_Precast-Rectangular Column: 430X200; Type: M_Precast-Rectangular Column: 430X200; Type Id: M_Precast-Rectangular Column: 430X200
Structural - Enable Analytical Model: yes; Rebar Cover - Bottom Face: Rebar Cover Settings: Rebar Cover 1; Rebar Cover - Other Faces: Rebar Cover Settings: Rebar Cover 1; Rebar Cover - Top Face: Rebar Cover Settings: Rebar Cover 1
Name (M_Precast-Rectangular Column:430X200:...) | In | Base Level = Level | Top Level | Base Offset (mm) | Column Location Mark | Top Offset (mm) | Length (mm) | Volume (m3) | Phase Created
417607 | R+1 | Level: R+1 | Level: R+2 | -750 | A1-1(115.0) | -1500 | 2910 | 0.246622 | New Construction | Identity Data - Comments: ThisIsNew
492508 | R-1 | Level: R-1 | Level: RDC | -2 | A1-1 | 0 | 3502 | 0.296795 | Existing

# IfcColumn: M_Precast-Rectangular Column:430X200 (2)
Type - PredefinedType: COLUMN; Material: Concrete, Precast Smooth, Light Grey
Type - Dimensions - b: 430 mm; Chamfer: 25 mm; h: 200 mm
Type - Identity Data - OmniClass Number: 23.25.30.11.14.11; OmniClass Title: Columns; Type Name: 430X200
Type - Other - Category: Structural Columns; Family Name: M_Precast-Rectangular Column
Type - Structural - Section Shape: 0
Type - Pset_ColumnCommon - IsExternal: no; LoadBearing: yes; Reference: 430X200
Type - Pset_ProductRequirements - Category: Structural Columns
Type - Pset_QuantityTakeOff - Reference: 430X200
Type - Pset_ReinforcementBarPitchOfColumn - Reference: 430X200
Pset_QuantityTakeOff - sets with these values: 2
Constraints - Column Style: Vertical; Moves With Grids: yes; Room Bounding: yes
Identity Data - Comments: ThisIsNew
Materials and Finishes - Structural Material: Concrete, Precast Smooth, Light Grey
Other - Family: M_Precast-Rectangular Column: 430X200; Family and Type: M_Precast-Rectangular Column: 430X200; Type: M_Precast-Rectangular Column: 430X200; Type Id: M_Precast-Rectangular Column: 430X200
Phasing - Phase Created: New Construction
Structural - Enable Analytical Model: yes; Rebar Cover - Bottom Face: Rebar Cover Settings: Rebar Cover 1; Rebar Cover - Other Faces: Rebar Cover Settings: Rebar Cover 1; Rebar Cover - Top Face: Rebar Cover Settings: Rebar Cover 1
Name (M_Precast-Rectangular Column:430X200:...) | In | Base Offset (mm) | Base Level = Level | Top Level | Column Location Mark | Top Offset (mm) | Length (mm) | Volume (m3)
400652 | RDC | 0 | Level: RDC | Level: R+1 | A1-1(110.0) | -750 | 2910 | 0.246622
417745 | R+2 | -1500 | Level: R+2 | Level: TOP | A1-1(105.0) | 0 | 5410 | 0.458498

# IfcColumn: M_Precast-Square Column:430x430 (310)
Type - PredefinedType: COLUMN; Material: Concrete, Precast Smooth, Light Grey
Type - Dimensions - b: 430 mm; Chamfer: 0 mm
Type - Identity Data - OmniClass Number: 23.25.30.11.14.11; OmniClass Title: Columns; Type Name: 430x430
Type - Other - Category: Structural Columns; Family Name: M_Precast-Square Column; TransChamfer: 2 mm
Type - Structural - Section Shape: 0
Type - Pset_ColumnCommon - Reference: 430x430; IsExternal: no; LoadBearing: yes
Type - Pset_ProductRequirements - Category: Structural Columns
Type - Pset_QuantityTakeOff - Reference: 430x430
Type - Pset_ReinforcementBarPitchOfColumn - Reference: 430x430
Pset_QuantityTakeOff - sets with these values: 2
Constraints - Column Style: Vertical; Moves With Grids: yes; Room Bounding: yes
Identity Data - Comments: ThisIsExisting
Materials and Finishes - Structural Material: Concrete, Precast Smooth, Light Grey
Other - Family: M_Precast-Square Column: 430x430; Family and Type: M_Precast-Square Column: 430x430; Rebar Grids W: 0.98 kN; Single Rebar W: 0.49 kN; Tie Rod W: 0.294 kN; Type: M_Precast-Square Column: 430x430; Type Id: M_Precast-Square Column: 430x430
Phasing - Phase Created: Existing
Structural - Enable Analytical Model: yes; Rebar Cover - Bottom Face: Rebar Cover Settings: Rebar Cover 1; Rebar Cover - Other Faces: Rebar Cover Settings: Rebar Cover 1; Rebar Cover - Top Face: Rebar Cover Settings: Rebar Cover 1; Rebar Grids Weight: 100; Single Rebar Weight: 50; Tie Rod Weight: 30
Name (M_Precast-Square Column:430x430:...) | In | Base Level = Level | Base Offset (mm) | Column Location Mark | Top is Attached | Top Level | Top Offset (mm) | Attachment Justification At Top | Offset From Attachment At Top (mm) | Length (mm) | Volume (m3)
382164 | R-1 | Level: R-1 | -300 | A-0 | yes | Level: RDC | 0 | Minimum Intersection | 0 | 3800 | 0.70262
382166 | R-1 | Level: R-1 | -300 | A1-0 | yes | Level: RDC | 0 | Minimum Intersection | 0 | 3800 | 0.70262
382170 | R-1 | Level: R-1 | -300 | A-1 | yes | Level: RDC | 0 | Minimum Intersection | 0 | 3800 | 0.70262
382174 | R-1 | Level: R-1 | -300 | A-2 | yes | Level: RDC | 0 | Minimum Intersection | 0 | 3800 | 0.70262
382178 | R-1 | Level: R-1 | -300 | A-3 | yes | Level: RDC | 0 | Minimum Intersection | 0 | 3800 | 0.70262
382180 | R-1 | Level: R-1 | -300 | B-1 | yes | Level: RDC | 0 | Minimum Intersection | 0 | 3800 | 0.70262
382182 | R-1 | Level: R-1 | -300 | B-2 | yes | Level: RDC | 0 | Minimum Intersection | 0 | 3800 | 0.70262
382186 | R-1 | Level: R-1 | -300 | B-3 | yes | Level: RDC | 0 | Minimum Intersection | 0 | 3800 | 0.70262
382188 | R-1 | Level: R-1 | -300 | C-1 | yes | Level: RDC | 0 | Minimum Intersection | 0 | 3800 | 0.70262
382190 | R-1 | Level: R-1 | -300 | C-2 | yes | Level: RDC | 0 | Minimum Intersection | 0 | 3800 | 0.70262
382194 | R-1 | Level: R-1 | -300 | C-3 | yes | Level: RDC | 0 | Minimum Intersection | 0 | 3800 | 0.70262
382196 | R-1 | Level: R-1 | -300 | C1-1 | yes | Level: RDC | 0 | Minimum Intersection | 0 | 3800 | 0.70262
382204 | R-1 | Level: R-1 | -300 | D-1 | yes | Level: RDC | 0 | Minimum Intersection | 0 | 3800 | 0.70262
382206 | R-1 | Level: R-1 | -300 | D-2 | yes | Level: RDC | 0 | Minimum Intersection | 0 | 3800 | 0.70262
382208 | R-1 | Level: R-1 | -300 | D-0 | yes | Level: RDC | 0 | Minimum Intersection | 0 | 3800 | 0.70262
382210 | R-1 | Level: R-1 | -300 | D-3 | yes | Level: RDC | 0 | Minimum Intersection | 0 | 3800 | 0.70262
382212 | R-1 | Level: R-1 | -300 | E-1 | yes | Level: RDC | 0 | Minimum Intersection | 0 | 3800 | 0.70262
382214 | R-1 | Level: R-1 | -300 | E-2 | yes | Level: RDC | 0 | Minimum Intersection | 0 | 3800 | 0.70262
382216 | R-1 | Level: R-1 | -300 | E-0 | yes | Level: RDC | 0 | Minimum Intersection | 0 | 3800 | 0.70262
382218 | R-1 | Level: R-1 | -300 | E-3 | yes | Level: RDC | 0 | Minimum Intersection | 0 | 3800 | 0.70262
382220 | R-1 | Level: R-1 | -300 | F-1 | yes | Level: RDC | 0 | Minimum Intersection | 0 | 3800 | 0.70262
382222 | R-1 | Level: R-1 | -300 | F-2 | yes | Level: RDC | 0 | Minimum Intersection | 0 | 3800 | 0.70262
382224 | R-1 | Level: R-1 | -300 | F-0 | yes | Level: RDC | 0 | Minimum Intersection | 0 | 3800 | 0.70262
382226 | R-1 | Level: R-1 | -300 | F-3 | yes | Level: RDC | 0 | Minimum Intersection | 0 | 3800 | 0.70262
382230 | R-1 | Level: R-1 | -300 | B-4 | yes | Level: RDC | 0 | Minimum Intersection | 0 | 3800 | 0.70262
382232 | R-1 | Level: R-1 | -300 | C-4 | yes | Level: RDC | 0 | Minimum Intersection | 0 | 3800 | 0.70262
382234 | R-1 | Level: R-1 | -300 | A-4 | yes | Level: RDC | 0 | Minimum Intersection | 0 | 3800 | 0.70262
382238 | R-1 | Level: R-1 | -300 | D-4 | yes | Level: RDC | 0 | Minimum Intersection | 0 | 3800 | 0.70262
382240 | R-1 | Level: R-1 | -300 | E-4 | yes | Level: RDC | 0 | Minimum Intersection | 0 | 3800 | 0.70262
382242 | R-1 | Level: R-1 | -300 | F-4 | yes | Level: RDC | 0 | Minimum Intersection | 0 | 3800 | 0.70262
382246 | R-1 | Level: R-1 | -300 | B-5 | yes | Level: RDC | 0 | Minimum Intersection | 0 | 3800 | 0.70262
382248 | R-1 | Level: R-1 | -300 | C-5 | yes | Level: RDC | 0 | Minimum Intersection | 0 | 3800 | 0.70262
382250 | R-1 | Level: R-1 | -300 | A-5 | yes | Level: RDC | 0 | Minimum Intersection | 0 | 3800 | 0.70262
382254 | R-1 | Level: R-1 | -300 | D-5 | yes | Level: RDC | 0 | Minimum Intersection | 0 | 3800 | 0.70262
382256 | R-1 | Level: R-1 | -300 | E-5 | yes | Level: RDC | 0 | Minimum Intersection | 0 | 3800 | 0.70262
382258 | R-1 | Level: R-1 | -300 | F-5 | yes | Level: RDC | 0 | Minimum Intersection | 0 | 3800 | 0.70262
382262 | R-1 | Level: R-1 | -300 | B-6 | yes | Level: RDC | 0 | Minimum Intersection | 0 | 3800 | 0.70262
382264 | R-1 | Level: R-1 | -300 | C-6 | yes | Level: RDC | 0 | Minimum Intersection | 0 | 3800 | 0.70262
382266 | R-1 | Level: R-1 | -300 | A-6 | yes | Level: RDC | 0 | Minimum Intersection | 0 | 3800 | 0.70262
382270 | R-1 | Level: R-1 | -300 | D-6 | yes | Level: RDC | 0 | Minimum Intersection | 0 | 3800 | 0.70262
382272 | R-1 | Level: R-1 | -300 | E-6 | yes | Level: RDC | 0 | Minimum Intersection | 0 | 3800 | 0.70262
382274 | R-1 | Level: R-1 | -300 | F-6 | yes | Level: RDC | 0 | Minimum Intersection | 0 | 3800 | 0.70262
382278 | R-1 | Level: R-1 | -300 | B-7 | yes | Level: RDC | 0 | Minimum Intersection | 0 | 3800 | 0.70262
382280 | R-1 | Level: R-1 | -300 | C-7 | yes | Level: RDC | 0 | Minimum Intersection | 0 | 3800 | 0.70262
382282 | R-1 | Level: R-1 | -300 | A-7 | yes | Level: RDC | 0 | Minimum Intersection | 0 | 3800 | 0.70262
382286 | R-1 | Level: R-1 | -300 | D-7 | yes | Level: RDC | 0 | Minimum Intersection | 0 | 3800 | 0.70262
382288 | R-1 | Level: R-1 | -300 | E-7 | yes | Level: RDC | 0 | Minimum Intersection | 0 | 3800 | 0.70262
382290 | R-1 | Level: R-1 | -300 | F-7 | yes | Level: RDC | 0 | Minimum Intersection | 0 | 3800 | 0.70262
382294 | R-1 | Level: R-1 | -300 | B-8 | yes | Level: RDC | 0 | Minimum Intersection | 0 | 3800 | 0.70262
382296 | R-1 | Level: R-1 | -300 | C-8 | yes | Level: RDC | 0 | Minimum Intersection | 0 | 3800 | 0.70262
382298 | R-1 | Level: R-1 | -300 | A-8 | yes | Level: RDC | 0 | Minimum Intersection | 0 | 3800 | 0.70262
382302 | R-1 | Level: R-1 | -300 | D-8 | yes | Level: RDC | 0 | Minimum Intersection | 0 | 3800 | 0.70262
382304 | R-1 | Level: R-1 | -300 | E-8 | yes | Level: RDC | 0 | Minimum Intersection | 0 | 3800 | 0.70262
382306 | R-1 | Level: R-1 | -300 | F-8 | yes | Level: RDC | 0 | Minimum Intersection | 0 | 3800 | 0.70262
382310 | R-1 | Level: R-1 | -300 | B-9 | yes | Level: RDC | 0 | Minimum Intersection | 0 | 3800 | 0.70262
382312 | R-1 | Level: R-1 | -300 | C-9 | yes | Level: RDC | 0 | Minimum Intersection | 0 | 3800 | 0.70262
382314 | R-1 | Level: R-1 | -300 | A-9 | yes | Level: RDC | 0 | Minimum Intersection | 0 | 3800 | 0.70262
382318 | R-1 | Level: R-1 | -300 | D-9 | yes | Level: RDC | 0 | Minimum Intersection | 0 | 3800 | 0.70262
382320 | R-1 | Level: R-1 | -300 | E-9 | yes | Level: RDC | 0 | Minimum Intersection | 0 | 3800 | 0.70262
382322 | R-1 | Level: R-1 | -300 | F-9 | yes | Level: RDC | 0 | Minimum Intersection | 0 | 3800 | 0.70262
382326 | R-1 | Level: R-1 | -300 | B-10 | yes | Level: RDC | 0 | Minimum Intersection | 0 | 3800 | 0.70262
382328 | R-1 | Level: R-1 | -300 | C-10 | yes | Level: RDC | 0 | Minimum Intersection | 0 | 3800 | 0.70262
382330 | R-1 | Level: R-1 | -300 | A-10 | yes | Level: RDC | 0 | Minimum Intersection | 0 | 3800 | 0.70262
382334 | R-1 | Level: R-1 | -300 | D-10 | yes | Level: RDC | 0 | Minimum Intersection | 0 | 3800 | 0.70262
382336 | R-1 | Level: R-1 | -300 | E-10 | yes | Level: RDC | 0 | Minimum Intersection | 0 | 3800 | 0.70262
382338 | R-1 | Level: R-1 | -300 | F-10 | yes | Level: RDC | 0 | Minimum Intersection | 0 | 3800 | 0.70262
382342 | R-1 | Level: R-1 | -300 | B-11 | yes | Level: RDC | 0 | Minimum Intersection | 0 | 3800 | 0.70262
382344 | R-1 | Level: R-1 | -300 | C-11 | yes | Level: RDC | 0 | Minimum Intersection | 0 | 3800 | 0.70262
382346 | R-1 | Level: R-1 | -300 | A-11 | yes | Level: RDC | 0 | Minimum Intersection | 0 | 3800 | 0.70262
382350 | R-1 | Level: R-1 | -300 | D-11 | yes | Level: RDC | 0 | Minimum Intersection | 0 | 3800 | 0.70262
382352 | R-1 | Level: R-1 | -300 | E-11 | yes | Level: RDC | 0 | Minimum Intersection | 0 | 3800 | 0.70262
382354 | R-1 | Level: R-1 | -300 | F-11 | yes | Level: RDC | 0 | Minimum Intersection | 0 | 3800 | 0.70262
382358 | R-1 | Level: R-1 | -300 | B-12 | yes | Level: RDC | 0 | Minimum Intersection | 0 | 3800 | 0.70262
382360 | R-1 | Level: R-1 | -300 | C-12 | yes | Level: RDC | 0 | Minimum Intersection | 0 | 3800 | 0.70262
382362 | R-1 | Level: R-1 | -300 | A-12 | yes | Level: RDC | 0 | Minimum Intersection | 0 | 3800 | 0.70262
382366 | R-1 | Level: R-1 | -300 | D-12 | yes | Level: RDC | 0 | Minimum Intersection | 0 | 3800 | 0.70262
382368 | R-1 | Level: R-1 | -300 | E-12 | yes | Level: RDC | 0 | Minimum Intersection | 0 | 3800 | 0.70262
382370 | R-1 | Level: R-1 | -300 | F-12 | yes | Level: RDC | 0 | Minimum Intersection | 0 | 3800 | 0.70262
382374 | R-1 | Level: R-1 | -300 | B-13 | yes | Level: RDC | 0 | Minimum Intersection | 0 | 3800 | 0.70262
382376 | R-1 | Level: R-1 | -300 | C-13 | yes | Level: RDC | 0 | Minimum Intersection | 0 | 3800 | 0.70262
382378 | R-1 | Level: R-1 | -300 | A-13 | yes | Level: RDC | 0 | Minimum Intersection | 0 | 3800 | 0.70262
382382 | R-1 | Level: R-1 | -300 | D-13 | yes | Level: RDC | 0 | Minimum Intersection | 0 | 3800 | 0.70262
382384 | R-1 | Level: R-1 | -300 | E-13 | yes | Level: RDC | 0 | Minimum Intersection | 0 | 3800 | 0.70262
382386 | R-1 | Level: R-1 | -300 | F-13 | yes | Level: RDC | 0 | Minimum Intersection | 0 | 3800 | 0.70262
382390 | R-1 | Level: R-1 | -300 | B-14 | yes | Level: RDC | 0 | Minimum Intersection | 0 | 3800 | 0.70262
382392 | R-1 | Level: R-1 | -300 | C-14 | yes | Level: RDC | 0 | Minimum Intersection | 0 | 3800 | 0.70262
382394 | R-1 | Level: R-1 | -300 | A-14 | yes | Level: RDC | 0 | Minimum Intersection | 0 | 3800 | 0.70262
382398 | R-1 | Level: R-1 | -300 | D-14 | yes | Level: RDC | 0 | Minimum Intersection | 0 | 3800 | 0.70262
382400 | R-1 | Level: R-1 | -300 | E-14 | yes | Level: RDC | 0 | Minimum Intersection | 0 | 3800 | 0.70262
382402 | R-1 | Level: R-1 | -300 | F-14 | yes | Level: RDC | 0 | Minimum Intersection | 0 | 3800 | 0.70262
382406 | R-1 | Level: R-1 | -300 | B-15 | yes | Level: RDC | 0 | Minimum Intersection | 0 | 3800 | 0.70262
382408 | R-1 | Level: R-1 | -300 | C-15 | yes | Level: RDC | 0 | Minimum Intersection | 0 | 3800 | 0.70262
382410 | R-1 | Level: R-1 | -300 | A-15 | yes | Level: RDC | 0 | Minimum Intersection | 0 | 3800 | 0.70262
382414 | R-1 | Level: R-1 | -300 | D-15 | yes | Level: RDC | 0 | Minimum Intersection | 0 | 3800 | 0.70262
382416 | R-1 | Level: R-1 | -300 | E-15 | yes | Level: RDC | 0 | Minimum Intersection | 0 | 3800 | 0.70262
382418 | R-1 | Level: R-1 | -300 | F-15 | yes | Level: RDC | 0 | Minimum Intersection | 0 | 3800 | 0.70262
382422 | R-1 | Level: R-1 | -300 | B-16 | yes | Level: RDC | 0 | Minimum Intersection | 0 | 3800 | 0.70262
382424 | R-1 | Level: R-1 | -300 | C-16 | yes | Level: RDC | 0 | Minimum Intersection | 0 | 3800 | 0.70262
382426 | R-1 | Level: R-1 | -300 | A-16 | yes | Level: RDC | 0 | Minimum Intersection | 0 | 3800 | 0.70262
382430 | R-1 | Level: R-1 | -300 | D-16 | yes | Level: RDC | 0 | Minimum Intersection | 0 | 3800 | 0.70262
382432 | R-1 | Level: R-1 | -300 | E-16 | yes | Level: RDC | -130 | Minimum Intersection | 0 | 3670 | 0.678583
382434 | R-1 | Level: R-1 | -300 | F-16 | yes | Level: RDC | -130 | Minimum Intersection | 0 | 3670 | 0.678583
382438 | R-1 | Level: R-1 | -300 | B-16(-2260.0) | yes | Level: RDC | 0 | Minimum Intersection | 0 | 3800 | 0.70262
382440 | R-1 | Level: R-1 | -300 | C-16(-2260.0) | yes | Level: RDC | 0 | Minimum Intersection | 0 | 3800 | 0.70262
382442 | R-1 | Level: R-1 | -300 | A-16(-2260.0) | yes | Level: RDC | 0 | Minimum Intersection | 0 | 3800 | 0.70262
382446 | R-1 | Level: R-1 | -300 | D-16(-2260.0) | yes | Level: RDC | 0 | Minimum Intersection | 0 | 3800 | 0.70262
382454 | R-1 | Level: R-1 | -300 | B-18 | yes | Level: RDC | 0 | Minimum Intersection | 0 | 3800 | 0.70262
382456 | R-1 | Level: R-1 | -300 | C-18 | yes | Level: RDC | 0 | Minimum Intersection | 0 | 3800 | 0.70262
382458 | R-1 | Level: R-1 | -300 | A-18 | yes | Level: RDC | 0 | Minimum Intersection | 0 | 3800 | 0.70262
382462 | R-1 | Level: R-1 | -300 | D-18 | yes | Level: RDC | 0 | Minimum Intersection | 0 | 3800 | 0.70262
386817 | R-1 | Level: R-1 | -300 | D(-1830.0)-1 | yes | Level: RDC | 0 | Minimum Intersection | 0 | 3800 | 0.70262
389126 | R-1 | Level: R-1 | -300 | 0-20(37205.0) | yes | Level: RDC | 0 | Minimum Intersection | 0 | 3800 | 0.70262
389128 | R-1 | Level: R-1 | -300 | 0-20(35375.0) | yes | Level: RDC | 0 | Minimum Intersection | 0 | 3800 | 0.70262
389130 | R-1 | Level: R-1 | -300 | 1-20(35375.0) | yes | Level: RDC | 0 | Minimum Intersection | 0 | 3800 | 0.70262
389132 | R-1 | Level: R-1 | -300 | 1-20(37205.0) | yes | Level: RDC | 0 | Minimum Intersection | 0 | 3800 | 0.70262
389136 | R-1 | Level: R-1 | -300 | 2-20(37205.0) | yes | Level: RDC | 0 | Minimum Intersection | 0 | 3800 | 0.70262
389140 | R-1 | Level: R-1 | -300 | 3-20(37205.0) | yes | Level: RDC | 0 | Minimum Intersection | 0 | 3800 | 0.70262
389142 | R-1 | Level: R-1 | -300 | 1-20(26825.0) | yes | Level: RDC | 0 | Minimum Intersection | 0 | 3800 | 0.70262
389144 | R-1 | Level: R-1 | -300 | 2-20(26825.0) | yes | Level: RDC | 0 | Minimum Intersection | 0 | 3800 | 0.70262
389146 | R-1 | Level: R-1 | -300 | 0-20(26825.0) | yes | Level: RDC | 0 | Minimum Intersection | 0 | 3800 | 0.70262
389148 | R-1 | Level: R-1 | -300 | 3-20(26825.0) | yes | Level: RDC | 0 | Minimum Intersection | 0 | 3800 | 0.70262
389150 | R-1 | Level: R-1 | -300 | 1-20(24995.0) | yes | Level: RDC | 0 | Minimum Intersection | 0 | 3800 | 0.70262
389152 | R-1 | Level: R-1 | -300 | 2-20(24995.0) | yes | Level: RDC | -130 | Minimum Intersection | 0 | 3670 | 0.678583
389154 | R-1 | Level: R-1 | -300 | 0-20(24995.0) | yes | Level: RDC | 0 | Minimum Intersection | 0 | 3800 | 0.70262
389156 | R-1 | Level: R-1 | -300 | 3-20(24995.0) | yes | Level: RDC | -130 | Minimum Intersection | 0 | 3670 | 0.678583
389158 | R-1 | Level: R-1 | -300 | 1-20(23165.0) | yes | Level: RDC | 0 | Minimum Intersection | 0 | 3800 | 0.70262
389166 | R-1 | Level: R-1 | -300 | 1-20(14615.0) | yes | Level: RDC | 0 | Minimum Intersection | 0 | 3800 | 0.70262
389168 | R-1 | Level: R-1 | -300 | 2-20(14615.0) | yes | Level: RDC | -130 | Minimum Intersection | 0 | 3670 | 0.678583
389170 | R-1 | Level: R-1 | -300 | 0-20(14615.0) | yes | Level: RDC | 0 | Minimum Intersection | 0 | 3800 | 0.70262
389172 | R-1 | Level: R-1 | -300 | 3-20(14615.0) | yes | Level: RDC | -130 | Minimum Intersection | 0 | 3670 | 0.678583
389174 | R-1 | Level: R-1 | -300 | 1-20(4235.0) | yes | Level: RDC | 0 | Minimum Intersection | 0 | 3800 | 0.70262
389176 | R-1 | Level: R-1 | -300 | 2-20(4235.0) | yes | Level: RDC | 0 | Minimum Intersection | 0 | 3800 | 0.70262
389178 | R-1 | Level: R-1 | -300 | 0-20(4235.0) | yes | Level: RDC | 0 | Minimum Intersection | 0 | 3800 | 0.70262
389180 | R-1 | Level: R-1 | -300 | 3-20(4235.0) | yes | Level: RDC | 0 | Minimum Intersection | 0 | 3800 | 0.70262
389182 | R-1 | Level: R-1 | -300 | 1-20(2405.0) | yes | Level: RDC | 0 | Minimum Intersection | 0 | 3800 | 0.70262
389184 | R-1 | Level: R-1 | -300 | 2-20(2405.0) | yes | Level: RDC | 0 | Minimum Intersection | 0 | 3800 | 0.70262
389186 | R-1 | Level: R-1 | -300 | 0-20(2405.0) | yes | Level: RDC | 0 | Minimum Intersection | 0 | 3800 | 0.70262
389188 | R-1 | Level: R-1 | -300 | 3-20(2405.0) | yes | Level: RDC | 0 | Minimum Intersection | 0 | 3800 | 0.70262
389192 | R-1 | Level: R-1 | -300 | 4-20(26825.0) | yes | Level: RDC | 0 | Minimum Intersection | 0 | 3800 | 0.70262
389194 | R-1 | Level: R-1 | -300 | 4-20(24995.0) | yes | Level: RDC | -130 | Minimum Intersection | 0 | 3670 | 0.678583
389196 | R-1 | Level: R-1 | -300 | 4-20(37205.0) | yes | Level: RDC | 0 | Minimum Intersection | 0 | 3800 | 0.70262
389200 | R-1 | Level: R-1 | -300 | 4-20(14615.0) | yes | Level: RDC | -130 | Minimum Intersection | 0 | 3670 | 0.678583
389202 | R-1 | Level: R-1 | -300 | 4-20(4235.0) | yes | Level: RDC | 0 | Minimum Intersection | 0 | 3800 | 0.70262
389204 | R-1 | Level: R-1 | -300 | 4-20(2405.0) | yes | Level: RDC | 0 | Minimum Intersection | 0 | 3800 | 0.70262
389208 | R-1 | Level: R-1 | -300 | 5-20(26825.0) | yes | Level: RDC | 0 | Minimum Intersection | 0 | 3800 | 0.70262
389210 | R-1 | Level: R-1 | -300 | 5-20(24995.0) | yes | Level: RDC | -130 | Minimum Intersection | 0 | 3670 | 0.678583
389212 | R-1 | Level: R-1 | -300 | 5-20(37205.0) | yes | Level: RDC | 0 | Minimum Intersection | 0 | 3800 | 0.70262
389216 | R-1 | Level: R-1 | -300 | 5-20(14615.0) | yes | Level: RDC | -130 | Minimum Intersection | 0 | 3670 | 0.678583
389218 | R-1 | Level: R-1 | -300 | 5-20(4235.0) | yes | Level: RDC | 0 | Minimum Intersection | 0 | 3800 | 0.70262
389220 | R-1 | Level: R-1 | -300 | 5-20(2405.0) | yes | Level: RDC | 0 | Minimum Intersection | 0 | 3800 | 0.70262
389224 | R-1 | Level: R-1 | -300 | 6-20(26825.0) | yes | Level: RDC | 0 | Minimum Intersection | 0 | 3800 | 0.70262
389226 | R-1 | Level: R-1 | -300 | 6-20(24995.0) | yes | Level: RDC | -130 | Minimum Intersection | 0 | 3670 | 0.678583
389228 | R-1 | Level: R-1 | -300 | 6-20(37205.0) | yes | Level: RDC | 0 | Minimum Intersection | 0 | 3800 | 0.70262
389232 | R-1 | Level: R-1 | -300 | 6-20(14615.0) | yes | Level: RDC | -130 | Minimum Intersection | 0 | 3670 | 0.678583
389234 | R-1 | Level: R-1 | -300 | 6-20(4235.0) | yes | Level: RDC | 0 | Minimum Intersection | 0 | 3800 | 0.70262
389236 | R-1 | Level: R-1 | -300 | 6-20(2405.0) | yes | Level: RDC | 0 | Minimum Intersection | 0 | 3800 | 0.70262
389240 | R-1 | Level: R-1 | -300 | 7-20(26825.0) | yes | Level: RDC | 0 | Minimum Intersection | 0 | 3800 | 0.70262
389242 | R-1 | Level: R-1 | -300 | 7-20(24995.0) | yes | Level: RDC | -130 | Minimum Intersection | 0 | 3670 | 0.678583
389244 | R-1 | Level: R-1 | -300 | 7-20(37205.0) | yes | Level: RDC | 0 | Minimum Intersection | 0 | 3800 | 0.70262
389248 | R-1 | Level: R-1 | -300 | 7-20(14615.0) | yes | Level: RDC | -130 | Minimum Intersection | 0 | 3670 | 0.678583
389250 | R-1 | Level: R-1 | -300 | 7-20(4235.0) | yes | Level: RDC | 0 | Minimum Intersection | 0 | 3800 | 0.70262
389252 | R-1 | Level: R-1 | -300 | 7-20(2405.0) | yes | Level: RDC | 0 | Minimum Intersection | 0 | 3800 | 0.70262
389256 | R-1 | Level: R-1 | -300 | 8-20(26825.0) | yes | Level: RDC | 0 | Minimum Intersection | 0 | 3800 | 0.70262
389258 | R-1 | Level: R-1 | -300 | 8-20(24995.0) | yes | Level: RDC | -130 | Minimum Intersection | 0 | 3670 | 0.678583
389260 | R-1 | Level: R-1 | -300 | 8-20(37205.0) | yes | Level: RDC | 0 | Minimum Intersection | 0 | 3800 | 0.70262
389264 | R-1 | Level: R-1 | -300 | 8-20(14615.0) | yes | Level: RDC | -130 | Minimum Intersection | 0 | 3670 | 0.678583
389266 | R-1 | Level: R-1 | -300 | 8-20(4235.0) | yes | Level: RDC | 0 | Minimum Intersection | 0 | 3800 | 0.70262
389268 | R-1 | Level: R-1 | -300 | 8-20(2405.0) | yes | Level: RDC | 0 | Minimum Intersection | 0 | 3800 | 0.70262
389272 | R-1 | Level: R-1 | -300 | 9-20(26825.0) | yes | Level: RDC | 0 | Minimum Intersection | 0 | 3800 | 0.70262
389274 | R-1 | Level: R-1 | -300 | 9-20(24995.0) | yes | Level: RDC | -130 | Minimum Intersection | 0 | 3670 | 0.678583
389276 | R-1 | Level: R-1 | -300 | 9-20(37205.0) | yes | Level: RDC | 0 | Minimum Intersection | 0 | 3800 | 0.70262
389280 | R-1 | Level: R-1 | -300 | 9-20(14615.0) | yes | Level: RDC | -130 | Minimum Intersection | 0 | 3670 | 0.678583
389282 | R-1 | Level: R-1 | -300 | 9-20(4235.0) | yes | Level: RDC | 0 | Minimum Intersection | 0 | 3800 | 0.70262
389284 | R-1 | Level: R-1 | -300 | 9-20(2405.0) | yes | Level: RDC | 0 | Minimum Intersection | 0 | 3800 | 0.70262
389288 | R-1 | Level: R-1 | -300 | 10-20(26825.0) | yes | Level: RDC | 0 | Minimum Intersection | 0 | 3800 | 0.70262
389290 | R-1 | Level: R-1 | -300 | 10-20(24995.0) | yes | Level: RDC | -130 | Minimum Intersection | 0 | 3670 | 0.678583
389292 | R-1 | Level: R-1 | -300 | 10-20(37205.0) | yes | Level: RDC | 0 | Minimum Intersection | 0 | 3800 | 0.70262
389296 | R-1 | Level: R-1 | -300 | 10-20(14615.0) | yes | Level: RDC | -130 | Minimum Intersection | 0 | 3670 | 0.678583
389298 | R-1 | Level: R-1 | -300 | 10-20(4235.0) | yes | Level: RDC | 0 | Minimum Intersection | 0 | 3800 | 0.70262
389300 | R-1 | Level: R-1 | -300 | 10-20(2405.0) | yes | Level: RDC | 0 | Minimum Intersection | 0 | 3800 | 0.70262
389304 | R-1 | Level: R-1 | -300 | 11-20(26825.0) | yes | Level: RDC | 0 | Minimum Intersection | 0 | 3800 | 0.70262
389306 | R-1 | Level: R-1 | -300 | 11-20(24995.0) | yes | Level: RDC | -130 | Minimum Intersection | 0 | 3670 | 0.678583
389308 | R-1 | Level: R-1 | -300 | 11-20(37205.0) | yes | Level: RDC | 0 | Minimum Intersection | 0 | 3800 | 0.70262
389312 | R-1 | Level: R-1 | -300 | 11-20(14615.0) | yes | Level: RDC | -130 | Minimum Intersection | 0 | 3670 | 0.678583
389314 | R-1 | Level: R-1 | -300 | 11-20(4235.0) | yes | Level: RDC | 0 | Minimum Intersection | 0 | 3800 | 0.70262
389316 | R-1 | Level: R-1 | -300 | 11-20(2405.0) | yes | Level: RDC | 0 | Minimum Intersection | 0 | 3800 | 0.70262
389320 | R-1 | Level: R-1 | -300 | 12-20(26825.0) | yes | Level: RDC | 0 | Minimum Intersection | 0 | 3800 | 0.70262
389322 | R-1 | Level: R-1 | -300 | 12-20(24995.0) | yes | Level: RDC | -130 | Minimum Intersection | 0 | 3670 | 0.678583
389324 | R-1 | Level: R-1 | -300 | 12-20(37205.0) | yes | Level: RDC | 0 | Minimum Intersection | 0 | 3800 | 0.70262
389328 | R-1 | Level: R-1 | -300 | 12-20(14615.0) | yes | Level: RDC | -130 | Minimum Intersection | 0 | 3670 | 0.678583
389330 | R-1 | Level: R-1 | -300 | 12-20(4235.0) | yes | Level: RDC | 0 | Minimum Intersection | 0 | 3800 | 0.70262
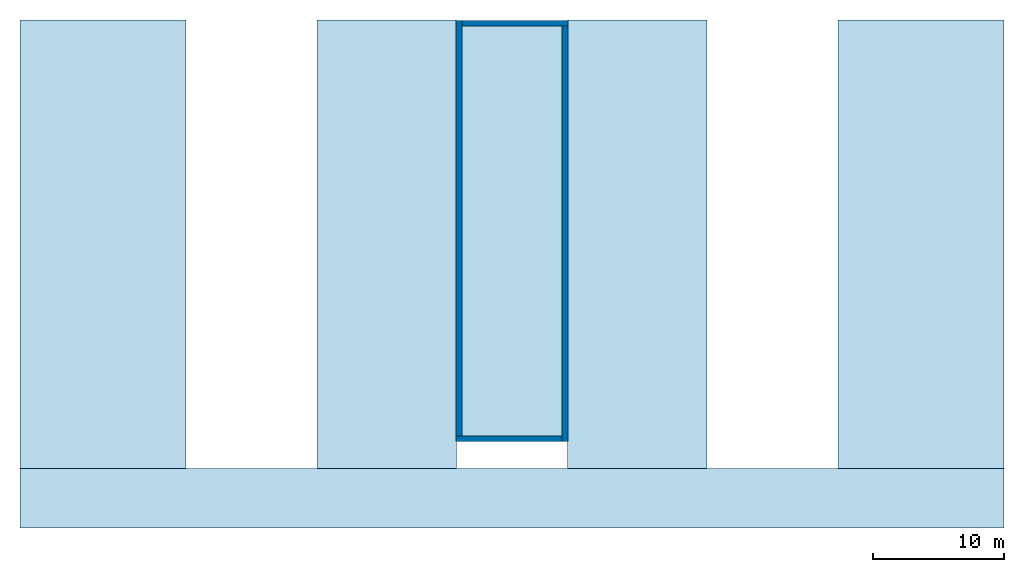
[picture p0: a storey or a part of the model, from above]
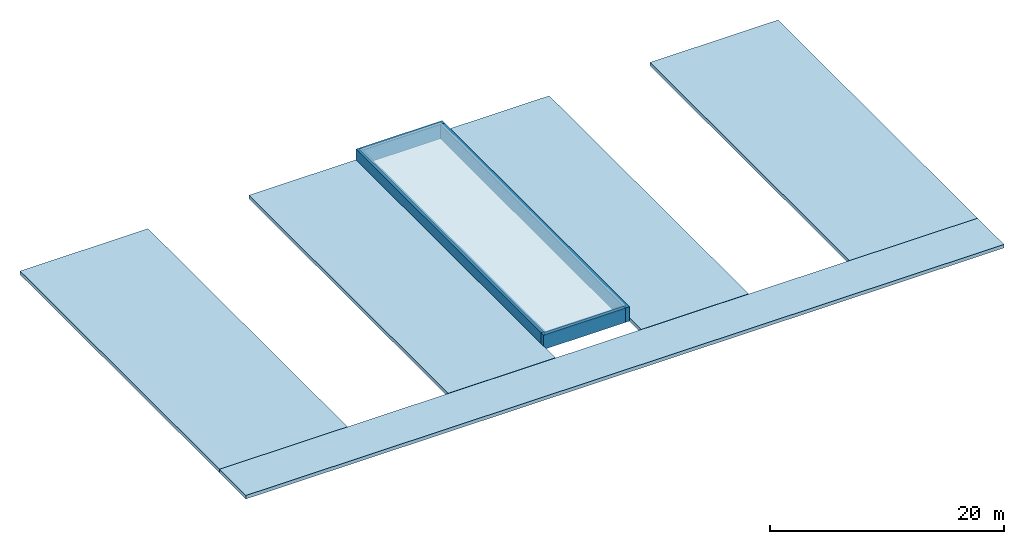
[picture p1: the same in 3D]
Properties of the parts of a building model (IFC2X3), part 2 of 3

# IfcColumn: M_Precast-Square Column:430x430 (310)
Name (M_Precast-Square Column:430x430:...) | In | Base Level = Level | Base Offset (mm) | Column Location Mark | Top is Attached | Top Level | Top Offset (mm) | Attachment Justification At Top | Offset From Attachment At Top (mm) | Length (mm) | Volume (m3)
389332 | R-1 | Level: R-1 | -300 | 12-20(2405.0) | yes | Level: RDC | 0 | Minimum Intersection | 0 | 3800 | 0.70262
389336 | R-1 | Level: R-1 | -300 | 13-20(26825.0) | yes | Level: RDC | 0 | Minimum Intersection | 0 | 3800 | 0.70262
389338 | R-1 | Level: R-1 | -300 | 13-20(24995.0) | yes | Level: RDC | -130 | Minimum Intersection | 0 | 3670 | 0.678583
389340 | R-1 | Level: R-1 | -300 | 13-20(37205.0) | yes | Level: RDC | 0 | Minimum Intersection | 0 | 3800 | 0.70262
389342 | R-1 | Level: R-1 | -300 | 13-20(23165.0) | yes | Level: RDC | -130 | Minimum Intersection | 0 | 3670 | 0.678583
389344 | R-1 | Level: R-1 | -300 | 13-20(14615.0) | yes | Level: RDC | -130 | Minimum Intersection | 0 | 3670 | 0.678583
389346 | R-1 | Level: R-1 | -300 | 13-20(4235.0) | yes | Level: RDC | 0 | Minimum Intersection | 0 | 3800 | 0.70262
389348 | R-1 | Level: R-1 | -300 | 13-20(2405.0) | yes | Level: RDC | 0 | Minimum Intersection | 0 | 3800 | 0.70262
389352 | R-1 | Level: R-1 | -300 | 14-20(26825.0) | yes | Level: RDC | 0 | Minimum Intersection | 0 | 3800 | 0.70262
389354 | R-1 | Level: R-1 | -300 | 14-20(24995.0) | yes | Level: RDC | -130 | Minimum Intersection | 0 | 3670 | 0.678583
389356 | R-1 | Level: R-1 | -300 | 14-20(37205.0) | yes | Level: RDC | 0 | Minimum Intersection | 0 | 3800 | 0.70262
389358 | R-1 | Level: R-1 | -300 | 14-20(23165.0) | yes | Level: RDC | -130 | Minimum Intersection | 0 | 3670 | 0.678583
389360 | R-1 | Level: R-1 | -300 | 14-20(14615.0) | yes | Level: RDC | -130 | Minimum Intersection | 0 | 3670 | 0.678583
389362 | R-1 | Level: R-1 | -300 | 14-20(4235.0) | yes | Level: RDC | 0 | Minimum Intersection | 0 | 3800 | 0.70262
389364 | R-1 | Level: R-1 | -300 | 14-20(2405.0) | yes | Level: RDC | 0 | Minimum Intersection | 0 | 3800 | 0.70262
389368 | R-1 | Level: R-1 | -300 | 15-20(26825.0) | yes | Level: RDC | 0 | Minimum Intersection | 0 | 3800 | 0.70262
389370 | R-1 | Level: R-1 | -300 | 15-20(24995.0) | yes | Level: RDC | -130 | Minimum Intersection | 0 | 3670 | 0.678583
389372 | R-1 | Level: R-1 | -300 | 15-20(37205.0) | yes | Level: RDC | 0 | Minimum Intersection | 0 | 3800 | 0.70262
389374 | R-1 | Level: R-1 | -300 | 15-20(23165.0) | yes | Level: RDC | -130 | Minimum Intersection | 0 | 3670 | 0.678583
389376 | R-1 | Level: R-1 | -300 | 15-20(14615.0) | yes | Level: RDC | -130 | Minimum Intersection | 0 | 3670 | 0.678583
389378 | R-1 | Level: R-1 | -300 | 15-20(4235.0) | yes | Level: RDC | 0 | Minimum Intersection | 0 | 3800 | 0.70262
389380 | R-1 | Level: R-1 | -300 | 15-20(2405.0) | yes | Level: RDC | 0 | Minimum Intersection | 0 | 3800 | 0.70262
389384 | R-1 | Level: R-1 | -300 | 16-20(26825.0) | yes | Level: RDC | 0 | Minimum Intersection | 0 | 3800 | 0.70262
389386 | R-1 | Level: R-1 | -300 | 16-20(24995.0) | yes | Level: RDC | -130 | Minimum Intersection | 0 | 3670 | 0.678583
389390 | R-1 | Level: R-1 | -300 | 16-20(23165.0) | yes | Level: RDC | -130 | Minimum Intersection | 0 | 3670 | 0.678583
389392 | R-1 | Level: R-1 | -300 | 16-20(14615.0) | yes | Level: RDC | -130 | Minimum Intersection | 0 | 3670 | 0.678583
389394 | R-1 | Level: R-1 | -300 | 16-20(4235.0) | yes | Level: RDC | -130 | Minimum Intersection | 0 | 3670 | 0.678583
389396 | R-1 | Level: R-1 | -300 | 16-20(2405.0) | yes | Level: RDC | -130 | Minimum Intersection | 0 | 3670 | 0.678583
389400 | R-1 | Level: R-1 | -300 | 16(-2260.0)-20(26825.0) | yes | Level: RDC | 0 | Minimum Intersection | 0 | 3800 | 0.70262
389402 | R-1 | Level: R-1 | -300 | 16(-2260.0)-20(24995.0) | yes | Level: RDC | -130 | Minimum Intersection | 0 | 3670 | 0.678583
389406 | R-1 | Level: R-1 | -300 | 16(-2260.0)-20(23165.0) | yes | Level: RDC | -130 | Minimum Intersection | 0 | 3670 | 0.678583
389408 | R-1 | Level: R-1 | -300 | 16(-2260.0)-20(14615.0) | yes | Level: RDC | 0 | Minimum Intersection | 0 | 3800 | 0.70262
389416 | R-1 | Level: R-1 | -300 | 18-20(26825.0) | yes | Level: RDC | 0 | Minimum Intersection | 0 | 3800 | 0.70262
389418 | R-1 | Level: R-1 | -300 | 18-20(24995.0) | yes | Level: RDC | 0 | Minimum Intersection | 0 | 3800 | 0.70262
389420 | R-1 | Level: R-1 | -300 | 18-20(37205.0) | yes | Level: RDC | 0 | Minimum Intersection | 0 | 3800 | 0.70262
389422 | R-1 | Level: R-1 | -300 | 18-20(23165.0) | yes | Level: RDC | 0 | Minimum Intersection | 0 | 3800 | 0.70262
389424 | R-1 | Level: R-1 | -300 | 18-20(14615.0) | yes | Level: RDC | 0 | Minimum Intersection | 0 | 3800 | 0.70262
389464 | R-1 | Level: R-1 | -300 | 1-20(16445.0) | yes | Level: RDC | 0 | Minimum Intersection | 0 | 3800 | 0.70262
400325 | R-1 | Level: R-1 | -300 | B-1 | yes | Level: RDC | 0 | Minimum Intersection | 0 | 3800 | 0.70262
400534 | RDC | Level: RDC | 0 | B-1 |  | Level: R+1 | -750 |  |  | 2910 | 0.538059
400638 | RDC | Level: RDC | 0 | B-0 |  | Level: R+1 | -750 |  |  | 2910 | 0.538059
400640 | RDC | Level: RDC | 0 | C-0 |  | Level: R+1 | -750 |  |  | 2910 | 0.538059
400644 | RDC | Level: RDC | 0 | C-1 |  | Level: R+1 | -750 |  |  | 2910 | 0.538059
400646 | RDC | Level: RDC | 0 | C1-1 |  | Level: R+1 | -750 |  |  | 2910 | 0.538059
400648 | RDC | Level: RDC | 0 | D-1 |  | Level: R+1 | -750 |  |  | 2910 | 0.538059
400650 | RDC | Level: RDC | 0 | D-0 |  | Level: R+1 | -750 |  |  | 2910 | 0.538059
400654 | RDC | Level: RDC | 0 | A1-0 |  | Level: R+1 | -750 |  |  | 2910 | 0.538059
400656 | RDC | Level: RDC | 0 | E-1 |  | Level: R+1 | -750 |  |  | 2910 | 0.538059
400660 | RDC | Level: RDC | 0 | F-1 |  | Level: R+1 | -750 |  |  | 2910 | 0.538059
402755 | RDC | Level: RDC | 0 | D(-1944.8)-1 |  | Level: R+1 | -750 |  |  | 2910 | 0.538059
417593 | R+1 | Level: R+1 | -750 | B-1 |  | Level: R+2 | -1500 |  |  | 2910 | 0.538059
417595 | R+1 | Level: R+1 | -750 | B-0 |  | Level: R+2 | -1500 |  |  | 2910 | 0.538059
417597 | R+1 | Level: R+1 | -750 | C-0 |  | Level: R+2 | -1500 |  |  | 2910 | 0.538059
417599 | R+1 | Level: R+1 | -750 | C-1 |  | Level: R+2 | -1500 |  |  | 2910 | 0.538059
417601 | R+1 | Level: R+1 | -750 | C1-1 |  | Level: R+2 | -1500 |  |  | 2910 | 0.538059
417603 | R+1 | Level: R+1 | -750 | D-1 |  | Level: R+2 | -1500 |  |  | 2910 | 0.538059
417605 | R+1 | Level: R+1 | -750 | D-0 |  | Level: R+2 | -1500 |  |  | 2910 | 0.538059
417609 | R+1 | Level: R+1 | -750 | A1-0 |  | Level: R+2 | -1500 |  |  | 2910 | 0.538059
417611 | R+1 | Level: R+1 | -750 | E-1 |  | Level: R+2 | -1500 |  |  | 2910 | 0.538059
417615 | R+1 | Level: R+1 | -750 | F-1 |  | Level: R+2 | -1500 |  |  | 2910 | 0.538059
417619 | R+1 | Level: R+1 | -750 | D(-1924.8)-1 |  | Level: R+2 | -1500 |  |  | 2910 | 0.538059
417731 | R+2 | Level: R+2 | -1500 | B-1 |  | Level: TOP | 0 |  |  | 5410 | 1.00031
417733 | R+2 | Level: R+2 | -1500 | B-0 |  | Level: TOITURE | -2050 |  |  | 2970 | 0.549153
417735 | R+2 | Level: R+2 | -1500 | C-0 |  | Level: TOITURE | -2050 |  |  | 2970 | 0.549153
417737 | R+2 | Level: R+2 | -1500 | C-1 |  | Level: TOP | 0 |  |  | 5410 | 1.00031
417739 | R+2 | Level: R+2 | -1500 | C1-1 |  | Level: TOP | 0 |  |  | 5410 | 1.00031
417741 | R+2 | Level: R+2 | -1500 | D-1 |  | Level: TOP | 0 |  |  | 5410 | 1.00031
417743 | R+2 | Level: R+2 | -1500 | D-0 |  | Level: TOITURE | -2050 |  |  | 2970 | 0.549153
417747 | R+2 | Level: R+2 | -1500 | A1-0 |  | Level: TOITURE | -2050 |  |  | 2970 | 0.549153
417749 | R+2 | Level: R+2 | -1500 | E-1 |  | Level: TOP | 0 |  |  | 5410 | 1.00031
417753 | R+2 | Level: R+2 | -1500 | F-1 |  | Level: TOP | 0 |  |  | 5410 | 1.00031
417757 | R+2 | Level: R+2 | -1500 | D(-1924.8)-1 |  | Level: TOP | 0 |  |  | 5410 | 1.00031
429205 | RDC | Level: RDC | 0 | 0-19 |  | Level: R+1 | -750 |  |  | 2910 | 0.538059
429338 | RDC | Level: RDC | 0 | 1-19 |  | Level: R+1 | -750 |  |  | 2910 | 0.538059
430192 | R+1 | Level: R+1 | -750 | 1-19 |  | Level: R+2 | -1500 |  |  | 2910 | 0.538059
430293 | R+2 | Level: R+2 | -1500 | 1-19 |  | Level: TOP | 0 |  |  | 5410 | 1.00031
430505 | RDC | Level: RDC | 0 | 1-20(26825.0) |  | Level: R+1 | -750 |  |  | 2910 | 0.538059
430507 | RDC | Level: RDC | 0 | 0-20(26825.0) |  | Level: R+1 | -750 |  |  | 2910 | 0.538059
430509 | RDC | Level: RDC | 0 | 0-20(24995.0) |  | Level: R+1 | -750 |  |  | 2910 | 0.538059
430511 | RDC | Level: RDC | 0 | 1-20(24995.0) |  | Level: R+1 | -750 |  |  | 2910 | 0.538059
430513 | RDC | Level: RDC | 0 | 1-20(23032.0) |  | Level: R+1 | -750 |  |  | 2910 | 0.538059
430515 | RDC | Level: RDC | 0 | 1-20(14615.0) |  | Level: R+1 | -750 |  |  | 2910 | 0.538059
430517 | RDC | Level: RDC | 0 | 0-20(14615.0) |  | Level: R+1 | -750 |  |  | 2910 | 0.538059
430519 | RDC | Level: RDC | 0 | 1-20(35375.0) |  | Level: R+1 | -750 |  |  | 2910 | 0.538059
430521 | RDC | Level: RDC | 0 | 0-20(35375.0) |  | Level: R+1 | -750 |  |  | 2910 | 0.538059
430523 | RDC | Level: RDC | 0 | 1-20(4235.0) |  | Level: R+1 | -750 |  |  | 2910 | 0.538059
430525 | RDC | Level: RDC | 0 | 1-20(2405.0) |  | Level: R+1 | -750 |  |  | 2910 | 0.538059
430527 | RDC | Level: RDC | 0 | 1-20(16559.8) |  | Level: R+1 | -750 |  |  | 2910 | 0.538059
430536 | R+1 | Level: R+1 | -750 | 1-20(26825.0) |  | Level: R+2 | -1500 |  |  | 2910 | 0.538059
430538 | R+1 | Level: R+1 | -750 | 0-20(26825.0) |  | Level: R+2 | -1500 |  |  | 2910 | 0.538059
430540 | R+1 | Level: R+1 | -750 | 0-20(24995.0) |  | Level: R+2 | -1500 |  |  | 2910 | 0.538059
430542 | R+1 | Level: R+1 | -750 | 1-20(24995.0) |  | Level: R+2 | -1500 |  |  | 2910 | 0.538059
430544 | R+1 | Level: R+1 | -750 | 1-20(23032.0) |  | Level: R+2 | -1500 |  |  | 2910 | 0.538059
430546 | R+1 | Level: R+1 | -750 | 1-20(14615.0) |  | Level: R+2 | -1500 |  |  | 2910 | 0.538059
430548 | R+1 | Level: R+1 | -750 | 0-20(14615.0) |  | Level: R+2 | -1500 |  |  | 2910 | 0.538059
430550 | R+1 | Level: R+1 | -750 | 1-20(35375.0) |  | Level: R+2 | -1500 |  |  | 2910 | 0.538059
430552 | R+1 | Level: R+1 | -750 | 0-20(35375.0) |  | Level: R+2 | -1500 |  |  | 2910 | 0.538059
430554 | R+1 | Level: R+1 | -750 | 1-20(4235.0) |  | Level: R+2 | -1500 |  |  | 2910 | 0.538059
430556 | R+1 | Level: R+1 | -750 | 1-20(2405.0) |  | Level: R+2 | -1500 |  |  | 2910 | 0.538059
430558 | R+1 | Level: R+1 | -750 | 1-20(16539.8) |  | Level: R+2 | -1500 |  |  | 2910 | 0.538059
430560 | R+2 | Level: R+2 | -1500 | 1-20(26825.0) |  | Level: TOP | 0 |  |  | 5410 | 1.00031
430562 | R+2 | Level: R+2 | -1500 | 0-20(26825.0) |  | Level: TOITURE | -2050 |  |  | 2970 | 0.549153
430564 | R+2 | Level: R+2 | -1500 | 0-20(24995.0) |  | Level: TOITURE | -2050 |  |  | 2970 | 0.549153
430566 | R+2 | Level: R+2 | -1500 | 1-20(24995.0) |  | Level: TOP | 0 |  |  | 5410 | 1.00031
430568 | R+2 | Level: R+2 | -1500 | 1-20(23032.0) |  | Level: TOP | 0 |  |  | 5410 | 1.00031
430570 | R+2 | Level: R+2 | -1500 | 1-20(14615.0) |  | Level: TOP | 0 |  |  | 5410 | 1.00031
430572 | R+2 | Level: R+2 | -1500 | 0-20(14615.0) |  | Level: TOITURE | -2050 |  |  | 2970 | 0.549153
430574 | R+2 | Level: R+2 | -1500 | 1-20(35375.0) |  | Level: TOP | 0 |  |  | 5410 | 1.00031
430576 | R+2 | Level: R+2 | -1500 | 0-20(35375.0) |  | Level: TOITURE | -2050 |  |  | 2970 | 0.549153
430578 | R+2 | Level: R+2 | -1500 | 1-20(4235.0) |  | Level: TOP | 0 |  |  | 5410 | 1.00031
430580 | R+2 | Level: R+2 | -1500 | 1-20(2405.0) |  | Level: TOP | 0 |  |  | 5410 | 1.00031
430582 | R+2 | Level: R+2 | -1500 | 1-20(16539.8) |  | Level: TOP | 0 |  |  | 5410 | 1.00031
430656 | RDC | Level: RDC | 0 | 0-20(12785.0) |  | Level: R+1 | -750 |  |  | 2910 | 0.538059
430658 | RDC | Level: RDC | 0 | 1-20(12785.0) |  | Level: R+1 | -750 |  |  | 2910 | 0.538059
430664 | R+1 | Level: R+1 | -750 | 1-20(12785.0) |  | Level: R+2 | -1500 |  |  | 2910 | 0.538059
430666 | R+2 | Level: R+2 | -1500 | 1-20(12785.0) |  | Level: TOP | 0 |  |  | 5410 | 1.00031
502930 | RDC | Level: RDC | 0 | A-1 |  | Level: R+1 | 0 |  |  | 3660 | 0.676734
502994 | R+1 | Level: R+1 | 0 | A-1 |  | Level: R+2 | 0 |  |  | 3660 | 0.676734
503047 | R+2 | Level: R+2 | 0 | A-1 |  | Level: TOP | 0 |  |  | 3910 | 0.722959

# IfcColumn: M_Precast-Square Column:430x430 Main floor (569)
Type - PredefinedType: COLUMN; Material: Concrete, Precast Smooth, Light Grey
Type - Dimensions - Chamfer: 0 mm; b: 430 mm
Type - Identity Data - OmniClass Number: 23.25.30.11.14.11; OmniClass Title: Columns; Type Name: 430x430 Main floor
Type - Other - Category: Structural Columns; Family Name: M_Precast-Square Column; TransChamfer: 2 mm
Type - Structural - Section Shape: 0
Type - Pset_ColumnCommon - IsExternal: no; LoadBearing: yes; Reference: 430x430 Main floor
Type - Pset_ProductRequirements - Category: Structural Columns
Type - Pset_QuantityTakeOff - Reference: 430x430 Main floor
Type - Pset_ReinforcementBarPitchOfColumn - Reference: 430x430 Main floor
Pset_QuantityTakeOff - sets with these values: 2
Constraints - Column Style: Vertical; Moves With Grids: yes; Room Bounding: yes; Base Offset: 0 mm
Identity Data - Comments: ThisIsExisting
Materials and Finishes - Structural Material: Concrete, Precast Smooth, Light Grey
Other - Family: M_Precast-Square Column: 430x430 Main floor; Family and Type: M_Precast-Square Column: 430x430 Main floor; Rebar Grids W: 0.98 kN; Single Rebar W: 0.49 kN; Tie Rod W: 0.294 kN; Type: M_Precast-Square Column: 430x430 Main floor; Type Id: M_Precast-Square Column: 430x430 Main floor
Phasing - Phase Created: Existing
Structural - Enable Analytical Model: yes; Rebar Cover - Bottom Face: Rebar Cover Settings: Rebar Cover 1; Rebar Cover - Other Faces: Rebar Cover Settings: Rebar Cover 1; Rebar Cover - Top Face: Rebar Cover Settings: Rebar Cover 1; Rebar Grids Weight: 100; Single Rebar Weight: 50; Tie Rod Weight: 30
Name (M_Precast-Square Column:430x430 Main floor:...) | In | Base Level = Level | Top Level | Column Location Mark | Top Offset (mm) | Length (mm) | Volume (m3)
430888 | RDC | Level: RDC | Level: R+1 | A1-2 | -700 | 2960 | 0.547304
430890 | RDC | Level: RDC | Level: R+1 | A-2 | 0 | 3660 | 0.676734
430894 | RDC | Level: RDC | Level: R+1 | A-3 | 0 | 3660 | 0.676734
430896 | RDC | Level: RDC | Level: R+1 | B-2 | 0 | 3660 | 0.676734
430898 | RDC | Level: RDC | Level: R+1 | B-3 | 0 | 3660 | 0.676734
430900 | RDC | Level: RDC | Level: R+1 | C-2 | 0 | 3660 | 0.676734
430902 | RDC | Level: RDC | Level: R+1 | C-3 | 0 | 3660 | 0.676734
430904 | RDC | Level: RDC | Level: R+1 | D-2 | 0 | 3660 | 0.676734
430906 | RDC | Level: RDC | Level: R+1 | D-3 | 0 | 3660 | 0.676734
430908 | RDC | Level: RDC | Level: R+1 | E-2 | 0 | 3660 | 0.676734
430910 | RDC | Level: RDC | Level: R+1 | E-3 | 0 | 3660 | 0.676734
430912 | RDC | Level: RDC | Level: R+1 | F-2 | 0 | 3660 | 0.676734
430914 | RDC | Level: RDC | Level: R+1 | F-3 | 0 | 3660 | 0.676734
430918 | RDC | Level: RDC | Level: R+1 | B-4 | 0 | 3660 | 0.676734
430920 | RDC | Level: RDC | Level: R+1 | C-4 | 0 | 3660 | 0.676734
430922 | RDC | Level: RDC | Level: R+1 | A-4 | 0 | 3660 | 0.676734
430924 | RDC | Level: RDC | Level: R+1 | D-4 | 0 | 3660 | 0.676734
430926 | RDC | Level: RDC | Level: R+1 | E-4 | 0 | 3660 | 0.676734
430928 | RDC | Level: RDC | Level: R+1 | F-4 | 0 | 3660 | 0.676734
430932 | RDC | Level: RDC | Level: R+1 | B-5 | 0 | 3660 | 0.676734
430934 | RDC | Level: RDC | Level: R+1 | C-5 | 0 | 3660 | 0.676734
430936 | RDC | Level: RDC | Level: R+1 | A-5 | 0 | 3660 | 0.676734
430938 | RDC | Level: RDC | Level: R+1 | D-5 | 0 | 3660 | 0.676734
430940 | RDC | Level: RDC | Level: R+1 | E-5 | 0 | 3660 | 0.676734
430942 | RDC | Level: RDC | Level: R+1 | F-5 | 0 | 3660 | 0.676734
430946 | RDC | Level: RDC | Level: R+1 | B-6 | 0 | 3660 | 0.676734
430948 | RDC | Level: RDC | Level: R+1 | C-6 | 0 | 3660 | 0.676734
430950 | RDC | Level: RDC | Level: R+1 | A-6 | 0 | 3660 | 0.676734
430952 | RDC | Level: RDC | Level: R+1 | D-6 | 0 | 3660 | 0.676734
430954 | RDC | Level: RDC | Level: R+1 | E-6 | 0 | 3660 | 0.676734
430956 | RDC | Level: RDC | Level: R+1 | F-6 | 0 | 3660 | 0.676734
430960 | RDC | Level: RDC | Level: R+1 | B-7 | 0 | 3660 | 0.676734
430962 | RDC | Level: RDC | Level: R+1 | C-7 | 0 | 3660 | 0.676734
430964 | RDC | Level: RDC | Level: R+1 | A-7 | 0 | 3660 | 0.676734
430966 | RDC | Level: RDC | Level: R+1 | D-7 | 0 | 3660 | 0.676734
430968 | RDC | Level: RDC | Level: R+1 | E-7 | 0 | 3660 | 0.676734
430970 | RDC | Level: RDC | Level: R+1 | F-7 | 0 | 3660 | 0.676734
430974 | RDC | Level: RDC | Level: R+1 | B-8 | 0 | 3660 | 0.676734
430976 | RDC | Level: RDC | Level: R+1 | C-8 | 0 | 3660 | 0.676734
430978 | RDC | Level: RDC | Level: R+1 | A-8 | 0 | 3660 | 0.676734
430980 | RDC | Level: RDC | Level: R+1 | D-8 | 0 | 3660 | 0.676734
430982 | RDC | Level: RDC | Level: R+1 | E-8 | 0 | 3660 | 0.676734
430984 | RDC | Level: RDC | Level: R+1 | F-8 | 0 | 3660 | 0.676734
430988 | RDC | Level: RDC | Level: R+1 | B-9 | 0 | 3660 | 0.676734
430990 | RDC | Level: RDC | Level: R+1 | C-9 | 0 | 3660 | 0.676734
430992 | RDC | Level: RDC | Level: R+1 | A-9 | 0 | 3660 | 0.676734
430994 | RDC | Level: RDC | Level: R+1 | D-9 | 0 | 3660 | 0.676734
430996 | RDC | Level: RDC | Level: R+1 | E-9 | 0 | 3660 | 0.676734
430998 | RDC | Level: RDC | Level: R+1 | F-9 | 0 | 3660 | 0.676734
431002 | RDC | Level: RDC | Level: R+1 | B-10 | 0 | 3660 | 0.676734
431004 | RDC | Level: RDC | Level: R+1 | C-10 | 0 | 3660 | 0.676734
431006 | RDC | Level: RDC | Level: R+1 | A-10 | 0 | 3660 | 0.676734
431008 | RDC | Level: RDC | Level: R+1 | D-10 | 0 | 3660 | 0.676734
431010 | RDC | Level: RDC | Level: R+1 | E-10 | 0 | 3660 | 0.676734
431012 | RDC | Level: RDC | Level: R+1 | F-10 | 0 | 3660 | 0.676734
431016 | RDC | Level: RDC | Level: R+1 | B-11 | 0 | 3660 | 0.676734
431018 | RDC | Level: RDC | Level: R+1 | C-11 | 0 | 3660 | 0.676734
431020 | RDC | Level: RDC | Level: R+1 | A-11 | 0 | 3660 | 0.676734
431022 | RDC | Level: RDC | Level: R+1 | D-11 | 0 | 3660 | 0.676734
431024 | RDC | Level: RDC | Level: R+1 | E-11 | 0 | 3660 | 0.676734
431026 | RDC | Level: RDC | Level: R+1 | F-11 | 0 | 3660 | 0.676734
431030 | RDC | Level: RDC | Level: R+1 | B-12 | 0 | 3660 | 0.676734
431032 | RDC | Level: RDC | Level: R+1 | C-12 | 0 | 3660 | 0.676734
431034 | RDC | Level: RDC | Level: R+1 | A-12 | 0 | 3660 | 0.676734
431036 | RDC | Level: RDC | Level: R+1 | D-12 | 0 | 3660 | 0.676734
431038 | RDC | Level: RDC | Level: R+1 | E-12 | 0 | 3660 | 0.676734
431040 | RDC | Level: RDC | Level: R+1 | F-12 | 0 | 3660 | 0.676734
431044 | RDC | Level: RDC | Level: R+1 | B-13 | 0 | 3660 | 0.676734
431046 | RDC | Level: RDC | Level: R+1 | C-13 | 0 | 3660 | 0.676734
431048 | RDC | Level: RDC | Level: R+1 | A-13 | 0 | 3660 | 0.676734
431050 | RDC | Level: RDC | Level: R+1 | D-13 | 0 | 3660 | 0.676734
431052 | RDC | Level: RDC | Level: R+1 | E-13 | 0 | 3660 | 0.676734
431054 | RDC | Level: RDC | Level: R+1 | F-13 | 0 | 3660 | 0.676734
431058 | RDC | Level: RDC | Level: R+1 | B-14 | 0 | 3660 | 0.676734
431060 | RDC | Level: RDC | Level: R+1 | C-14 | 0 | 3660 | 0.676734
431062 | RDC | Level: RDC | Level: R+1 | A-14 | 0 | 3660 | 0.676734
431064 | RDC | Level: RDC | Level: R+1 | D-14 | 0 | 3660 | 0.676734
431066 | RDC | Level: RDC | Level: R+1 | E-14 | 0 | 3660 | 0.676734
431068 | RDC | Level: RDC | Level: R+1 | F-14 | 0 | 3660 | 0.676734
431072 | RDC | Level: RDC | Level: R+1 | B-15 | 0 | 3660 | 0.676734
431074 | RDC | Level: RDC | Level: R+1 | C-15 | 0 | 3660 | 0.676734
431076 | RDC | Level: RDC | Level: R+1 | A-15 | 0 | 3660 | 0.676734
431078 | RDC | Level: RDC | Level: R+1 | D-15 | 0 | 3660 | 0.676734
431080 | RDC | Level: RDC | Level: R+1 | E-15 | 0 | 3660 | 0.676734
431082 | RDC | Level: RDC | Level: R+1 | F-15 | 0 | 3660 | 0.676734
431086 | RDC | Level: RDC | Level: R+1 | B-16 | 0 | 3660 | 0.676734
431088 | RDC | Level: RDC | Level: R+1 | C-16 | 0 | 3660 | 0.676734
431090 | RDC | Level: RDC | Level: R+1 | A-16 | 0 | 3660 | 0.676734
431100 | RDC | Level: RDC | Level: R+1 | B-16(-2260.0) | 0 | 3660 | 0.676734
431102 | RDC | Level: RDC | Level: R+1 | C-16(-2260.0) | 0 | 3660 | 0.676734
431104 | RDC | Level: RDC | Level: R+1 | A-16(-2260.0) | 0 | 3660 | 0.676734
431110 | RDC | Level: RDC | Level: R+1 | B-18 | 0 | 3660 | 0.676734
431112 | RDC | Level: RDC | Level: R+1 | C-18 | 0 | 3660 | 0.676734
431114 | RDC | Level: RDC | Level: R+1 | A-18 | 0 | 3660 | 0.676734
431118 | RDC | Level: RDC | Level: R+1 | 2-20(37205.0) | 0 | 3660 | 0.676734
431120 | RDC | Level: RDC | Level: R+1 | 3-20(37205.0) | 0 | 3660 | 0.676734
431122 | RDC | Level: RDC | Level: R+1 | 2-20(26825.0) | 0 | 3660 | 0.676734
431124 | RDC | Level: RDC | Level: R+1 | 3-20(26825.0) | 0 | 3660 | 0.676734
431126 | RDC | Level: RDC | Level: R+1 | 2-20(24995.0) | 0 | 3660 | 0.676734
431128 | RDC | Level: RDC | Level: R+1 | 3-20(24995.0) | 0 | 3660 | 0.676734
431130 | RDC | Level: RDC | Level: R+1 | 2-20(14615.0) | 0 | 3660 | 0.676734
431132 | RDC | Level: RDC | Level: R+1 | 3-20(14615.0) | 0 | 3660 | 0.676734
431134 | RDC | Level: RDC | Level: R+1 | 2-20(4235.0) | 0 | 3660 | 0.676734
431136 | RDC | Level: RDC | Level: R+1 | 3-20(4235.0) | 0 | 3660 | 0.676734
431138 | RDC | Level: RDC | Level: R+1 | 2-20(2405.0) | 0 | 3660 | 0.676734
431140 | RDC | Level: RDC | Level: R+1 | 3-20(2405.0) | 0 | 3660 | 0.676734
431142 | RDC | Level: RDC | Level: R+1 | 4-20(26825.0) | 0 | 3660 | 0.676734
431144 | RDC | Level: RDC | Level: R+1 | 4-20(24995.0) | 0 | 3660 | 0.676734
431146 | RDC | Level: RDC | Level: R+1 | 4-20(37205.0) | 0 | 3660 | 0.676734
431148 | RDC | Level: RDC | Level: R+1 | 4-20(14615.0) | 0 | 3660 | 0.676734
431150 | RDC | Level: RDC | Level: R+1 | 4-20(4235.0) | 0 | 3660 | 0.676734
431152 | RDC | Level: RDC | Level: R+1 | 4-20(2405.0) | 0 | 3660 | 0.676734
431154 | RDC | Level: RDC | Level: R+1 | 5-20(26825.0) | 0 | 3660 | 0.676734
431156 | RDC | Level: RDC | Level: R+1 | 5-20(24995.0) | 0 | 3660 | 0.676734
431158 | RDC | Level: RDC | Level: R+1 | 5-20(37205.0) | 0 | 3660 | 0.676734
431160 | RDC | Level: RDC | Level: R+1 | 5-20(14615.0) | 0 | 3660 | 0.676734
431162 | RDC | Level: RDC | Level: R+1 | 5-20(4235.0) | 0 | 3660 | 0.676734
431164 | RDC | Level: RDC | Level: R+1 | 5-20(2405.0) | 0 | 3660 | 0.676734
431166 | RDC | Level: RDC | Level: R+1 | 6-20(26825.0) | 0 | 3660 | 0.676734
431168 | RDC | Level: RDC | Level: R+1 | 6-20(24995.0) | 0 | 3660 | 0.676734
431170 | RDC | Level: RDC | Level: R+1 | 6-20(37205.0) | 0 | 3660 | 0.676734
431172 | RDC | Level: RDC | Level: R+1 | 6-20(14615.0) | 0 | 3660 | 0.676734
431174 | RDC | Level: RDC | Level: R+1 | 6-20(4235.0) | 0 | 3660 | 0.676734
431176 | RDC | Level: RDC | Level: R+1 | 6-20(2405.0) | 0 | 3660 | 0.676734
431178 | RDC | Level: RDC | Level: R+1 | 7-20(26825.0) | 0 | 3660 | 0.676734
431180 | RDC | Level: RDC | Level: R+1 | 7-20(24995.0) | 0 | 3660 | 0.676734
431182 | RDC | Level: RDC | Level: R+1 | 7-20(37205.0) | 0 | 3660 | 0.676734
431184 | RDC | Level: RDC | Level: R+1 | 7-20(14615.0) | 0 | 3660 | 0.676734
431186 | RDC | Level: RDC | Level: R+1 | 7-20(4235.0) | 0 | 3660 | 0.676734
431188 | RDC | Level: RDC | Level: R+1 | 7-20(2405.0) | 0 | 3660 | 0.676734
431190 | RDC | Level: RDC | Level: R+1 | 8-20(26825.0) | 0 | 3660 | 0.676734
431192 | RDC | Level: RDC | Level: R+1 | 8-20(24995.0) | 0 | 3660 | 0.676734
431194 | RDC | Level: RDC | Level: R+1 | 8-20(37205.0) | 0 | 3660 | 0.676734
431196 | RDC | Level: RDC | Level: R+1 | 8-20(14615.0) | 0 | 3660 | 0.676734
431198 | RDC | Level: RDC | Level: R+1 | 8-20(4235.0) | 0 | 3660 | 0.676734
431200 | RDC | Level: RDC | Level: R+1 | 8-20(2405.0) | 0 | 3660 | 0.676734
431202 | RDC | Level: RDC | Level: R+1 | 9-20(26825.0) | 0 | 3660 | 0.676734
431204 | RDC | Level: RDC | Level: R+1 | 9-20(24995.0) | 0 | 3660 | 0.676734
431206 | RDC | Level: RDC | Level: R+1 | 9-20(37205.0) | 0 | 3660 | 0.676734
431208 | RDC | Level: RDC | Level: R+1 | 9-20(14615.0) | 0 | 3660 | 0.676734
431210 | RDC | Level: RDC | Level: R+1 | 9-20(4235.0) | 0 | 3660 | 0.676734
431212 | RDC | Level: RDC | Level: R+1 | 9-20(2405.0) | 0 | 3660 | 0.676734
431214 | RDC | Level: RDC | Level: R+1 | 10-20(26825.0) | 0 | 3660 | 0.676734
431216 | RDC | Level: RDC | Level: R+1 | 10-20(24995.0) | 0 | 3660 | 0.676734
431218 | RDC | Level: RDC | Level: R+1 | 10-20(37205.0) | 0 | 3660 | 0.676734
431220 | RDC | Level: RDC | Level: R+1 | 10-20(14615.0) | 0 | 3660 | 0.676734
431222 | RDC | Level: RDC | Level: R+1 | 10-20(4235.0) | 0 | 3660 | 0.676734
431224 | RDC | Level: RDC | Level: R+1 | 10-20(2405.0) | 0 | 3660 | 0.676734
431226 | RDC | Level: RDC | Level: R+1 | 11-20(26825.0) | 0 | 3660 | 0.676734
431228 | RDC | Level: RDC | Level: R+1 | 11-20(24995.0) | 0 | 3660 | 0.676734
431230 | RDC | Level: RDC | Level: R+1 | 11-20(37205.0) | 0 | 3660 | 0.676734
431232 | RDC | Level: RDC | Level: R+1 | 11-20(14615.0) | 0 | 3660 | 0.676734
431234 | RDC | Level: RDC | Level: R+1 | 11-20(4235.0) | 0 | 3660 | 0.676734
431236 | RDC | Level: RDC | Level: R+1 | 11-20(2405.0) | 0 | 3660 | 0.676734
431238 | RDC | Level: RDC | Level: R+1 | 12-20(26825.0) | 0 | 3660 | 0.676734
431240 | RDC | Level: RDC | Level: R+1 | 12-20(24995.0) | 0 | 3660 | 0.676734
431242 | RDC | Level: RDC | Level: R+1 | 12-20(37205.0) | 0 | 3660 | 0.676734
431244 | RDC | Level: RDC | Level: R+1 | 12-20(14615.0) | 0 | 3660 | 0.676734
431246 | RDC | Level: RDC | Level: R+1 | 12-20(4235.0) | 0 | 3660 | 0.676734
431248 | RDC | Level: RDC | Level: R+1 | 12-20(2405.0) | 0 | 3660 | 0.676734
431250 | RDC | Level: RDC | Level: R+1 | 13-20(26825.0) | 0 | 3660 | 0.676734
431252 | RDC | Level: RDC | Level: R+1 | 13-20(24995.0) | 0 | 3660 | 0.676734
431254 | RDC | Level: RDC | Level: R+1 | 13-20(37205.0) | 0 | 3660 | 0.676734
431258 | RDC | Level: RDC | Level: R+1 | 13-20(14615.0) | 0 | 3660 | 0.676734
431260 | RDC | Level: RDC | Level: R+1 | 13-20(4235.0) | 0 | 3660 | 0.676734
431262 | RDC | Level: RDC | Level: R+1 | 13-20(2405.0) | 0 | 3660 | 0.676734
431264 | RDC | Level: RDC | Level: R+1 | 14-20(26825.0) | 0 | 3660 | 0.676734
431266 | RDC | Level: RDC | Level: R+1 | 14-20(24995.0) | 0 | 3660 | 0.676734
431268 | RDC | Level: RDC | Level: R+1 | 14-20(37205.0) | 0 | 3660 | 0.676734
431272 | RDC | Level: RDC | Level: R+1 | 14-20(14615.0) | 0 | 3660 | 0.676734
431274 | RDC | Level: RDC | Level: R+1 | 14-20(4235.0) | 0 | 3660 | 0.676734
431276 | RDC | Level: RDC | Level: R+1 | 14-20(2405.0) | 0 | 3660 | 0.676734
431278 | RDC | Level: RDC | Level: R+1 | 15-20(26825.0) | 0 | 3660 | 0.676734
431280 | RDC | Level: RDC | Level: R+1 | 15-20(24995.0) | 0 | 3660 | 0.676734
431282 | RDC | Level: RDC | Level: R+1 | 15-20(37205.0) | 0 | 3660 | 0.676734
431286 | RDC | Level: RDC | Level: R+1 | 15-20(14615.0) | 0 | 3660 | 0.676734
431288 | RDC | Level: RDC | Level: R+1 | 15-20(4235.0) | 0 | 3660 | 0.676734
431290 | RDC | Level: RDC | Level: R+1 | 15-20(2405.0) | 0 | 3660 | 0.676734
431292 | RDC | Level: RDC | Level: R+1 | 16-20(26825.0) | 0 | 3660 | 0.676734
431294 | RDC | Level: RDC | Level: R+1 | 16-20(24995.0) | 0 | 3660 | 0.676734
431304 | RDC | Level: RDC | Level: R+1 | 16(-2260.0)-20(26825.0) | 0 | 3660 | 0.676734
431306 | RDC | Level: RDC | Level: R+1 | 16(-2260.0)-20(24995.0) | 0 | 3660 | 0.676734
431312 | RDC | Level: RDC | Level: R+1 | 18-20(26825.0) | 0 | 3660 | 0.676734
431314 | RDC | Level: RDC | Level: R+1 | 18-20(24995.0) | 0 | 3660 | 0.676734
431316 | RDC | Level: RDC | Level: R+1 | 18-20(37205.0) | 0 | 3660 | 0.676734
444795 | R+1 | Level: R+1 | Level: R+2 | A-2 | 0 | 3660 | 0.676734
444799 | R+1 | Level: R+1 | Level: R+2 | A-3 | 0 | 3660 | 0.676734
444801 | R+1 | Level: R+1 | Level: R+2 | B-2 | 0 | 3660 | 0.676734
444803 | R+1 | Level: R+1 | Level: R+2 | B-3 | 0 | 3660 | 0.676734
444805 | R+1 | Level: R+1 | Level: R+2 | C-2 | 0 | 3660 | 0.676734
444807 | R+1 | Level: R+1 | Level: R+2 | C-3 | 0 | 3660 | 0.676734
444809 | R+1 | Level: R+1 | Level: R+2 | D-2 | 0 | 3660 | 0.676734
444811 | R+1 | Level: R+1 | Level: R+2 | D-3 | 0 | 3660 | 0.676734
444813 | R+1 | Level: R+1 | Level: R+2 | E-2 | 0 | 3660 | 0.676734
444815 | R+1 | Level: R+1 | Level: R+2 | E-3 | 0 | 3660 | 0.676734
444817 | R+1 | Level: R+1 | Level: R+2 | F-2 | 0 | 3660 | 0.676734
444819 | R+1 | Level: R+1 | Level: R+2 | F-3 | 0 | 3660 | 0.676734
444823 | R+1 | Level: R+1 | Level: R+2 | B-4 | 0 | 3660 | 0.676734
444825 | R+1 | Level: R+1 | Level: R+2 | C-4 | 0 | 3660 | 0.676734
444827 | R+1 | Level: R+1 | Level: R+2 | A-4 | 0 | 3660 | 0.676734
444829 | R+1 | Level: R+1 | Level: R+2 | D-4 | 0 | 3660 | 0.676734
444831 | R+1 | Level: R+1 | Level: R+2 | E-4 | 0 | 3660 | 0.676734
444833 | R+1 | Level: R+1 | Level: R+2 | F-4 | 0 | 3660 | 0.676734
444837 | R+1 | Level: R+1 | Level: R+2 | B-5 | 0 | 3660 | 0.676734
444839 | R+1 | Level: R+1 | Level: R+2 | C-5 | 0 | 3660 | 0.676734
444841 | R+1 | Level: R+1 | Level: R+2 | A-5 | 0 | 3660 | 0.676734
444843 | R+1 | Level: R+1 | Level: R+2 | D-5 | 0 | 3660 | 0.676734
444845 | R+1 | Level: R+1 | Level: R+2 | E-5 | 0 | 3660 | 0.676734
444847 | R+1 | Level: R+1 | Level: R+2 | F-5 | 0 | 3660 | 0.676734
444851 | R+1 | Level: R+1 | Level: R+2 | B-6 | 0 | 3660 | 0.676734
444853 | R+1 | Level: R+1 | Level: R+2 | C-6 | 0 | 3660 | 0.676734
444855 | R+1 | Level: R+1 | Level: R+2 | A-6 | 0 | 3660 | 0.676734
444857 | R+1 | Level: R+1 | Level: R+2 | D-6 | 0 | 3660 | 0.676734
444859 | R+1 | Level: R+1 | Level: R+2 | E-6 | 0 | 3660 | 0.676734
444861 | R+1 | Level: R+1 | Level: R+2 | F-6 | 0 | 3660 | 0.676734
444865 | R+1 | Level: R+1 | Level: R+2 | B-7 | 0 | 3660 | 0.676734
444867 | R+1 | Level: R+1 | Level: R+2 | C-7 | 0 | 3660 | 0.676734
444869 | R+1 | Level: R+1 | Level: R+2 | A-7 | 0 | 3660 | 0.676734
444871 | R+1 | Level: R+1 | Level: R+2 | D-7 | 0 | 3660 | 0.676734
444873 | R+1 | Level: R+1 | Level: R+2 | E-7 | 0 | 3660 | 0.676734
444875 | R+1 | Level: R+1 | Level: R+2 | F-7 | 0 | 3660 | 0.676734
444879 | R+1 | Level: R+1 | Level: R+2 | B-8 | 0 | 3660 | 0.676734
444881 | R+1 | Level: R+1 | Level: R+2 | C-8 | 0 | 3660 | 0.676734
444883 | R+1 | Level: R+1 | Level: R+2 | A-8 | 0 | 3660 | 0.676734
444885 | R+1 | Level: R+1 | Level: R+2 | D-8 | 0 | 3660 | 0.676734
444887 | R+1 | Level: R+1 | Level: R+2 | E-8 | 0 | 3660 | 0.676734
444889 | R+1 | Level: R+1 | Level: R+2 | F-8 | 0 | 3660 | 0.676734
444893 | R+1 | Level: R+1 | Level: R+2 | B-9 | 0 | 3660 | 0.676734
444895 | R+1 | Level: R+1 | Level: R+2 | C-9 | 0 | 3660 | 0.676734
444897 | R+1 | Level: R+1 | Level: R+2 | A-9 | 0 | 3660 | 0.676734
444899 | R+1 | Level: R+1 | Level: R+2 | D-9 | 0 | 3660 | 0.676734
444901 | R+1 | Level: R+1 | Level: R+2 | E-9 | 0 | 3660 | 0.676734
444903 | R+1 | Level: R+1 | Level: R+2 | F-9 | 0 | 3660 | 0.676734
444907 | R+1 | Level: R+1 | Level: R+2 | B-10 | 0 | 3660 | 0.676734
444909 | R+1 | Level: R+1 | Level: R+2 | C-10 | 0 | 3660 | 0.676734
444911 | R+1 | Level: R+1 | Level: R+2 | A-10 | 0 | 3660 | 0.676734
444913 | R+1 | Level: R+1 | Level: R+2 | D-10 | 0 | 3660 | 0.676734
444915 | R+1 | Level: R+1 | Level: R+2 | E-10 | 0 | 3660 | 0.676734
444917 | R+1 | Level: R+1 | Level: R+2 | F-10 | 0 | 3660 | 0.676734
444921 | R+1 | Level: R+1 | Level: R+2 | B-11 | 0 | 3660 | 0.676734
444923 | R+1 | Level: R+1 | Level: R+2 | C-11 | 0 | 3660 | 0.676734
444925 | R+1 | Level: R+1 | Level: R+2 | A-11 | 0 | 3660 | 0.676734
444927 | R+1 | Level: R+1 | Level: R+2 | D-11 | 0 | 3660 | 0.676734
444929 | R+1 | Level: R+1 | Level: R+2 | E-11 | 0 | 3660 | 0.676734
444931 | R+1 | Level: R+1 | Level: R+2 | F-11 | 0 | 3660 | 0.676734
444935 | R+1 | Level: R+1 | Level: R+2 | B-12 | 0 | 3660 | 0.676734
444937 | R+1 | Level: R+1 | Level: R+2 | C-12 | 0 | 3660 | 0.676734
444939 | R+1 | Level: R+1 | Level: R+2 | A-12 | 0 | 3660 | 0.676734
444941 | R+1 | Level: R+1 | Level: R+2 | D-12 | 0 | 3660 | 0.676734
444943 | R+1 | Level: R+1 | Level: R+2 | E-12 | 0 | 3660 | 0.676734
444945 | R+1 | Level: R+1 | Level: R+2 | F-12 | 0 | 3660 | 0.676734
444949 | R+1 | Level: R+1 | Level: R+2 | B-13 | 0 | 3660 | 0.676734
444951 | R+1 | Level: R+1 | Level: R+2 | C-13 | 0 | 3660 | 0.676734
444953 | R+1 | Level: R+1 | Level: R+2 | A-13 | 0 | 3660 | 0.676734
444955 | R+1 | Level: R+1 | Level: R+2 | D-13 | 0 | 3660 | 0.676734
444957 | R+1 | Level: R+1 | Level: R+2 | E-13 | 0 | 3660 | 0.676734
444959 | R+1 | Level: R+1 | Level: R+2 | F-13 | 0 | 3660 | 0.676734
444963 | R+1 | Level: R+1 | Level: R+2 | B-14 | 0 | 3660 | 0.676734
444965 | R+1 | Level: R+1 | Level: R+2 | C-14 | 0 | 3660 | 0.676734
444967 | R+1 | Level: R+1 | Level: R+2 | A-14 | 0 | 3660 | 0.676734
444969 | R+1 | Level: R+1 | Level: R+2 | D-14 | 0 | 3660 | 0.676734
444971 | R+1 | Level: R+1 | Level: R+2 | E-14 | 0 | 3660 | 0.676734
444973 | R+1 | Level: R+1 | Level: R+2 | F-14 | 0 | 3660 | 0.676734
444977 | R+1 | Level: R+1 | Level: R+2 | B-15 | 0 | 3660 | 0.676734
444979 | R+1 | Level: R+1 | Level: R+2 | C-15 | 0 | 3660 | 0.676734
444981 | R+1 | Level: R+1 | Level: R+2 | A-15 | 0 | 3660 | 0.676734
444983 | R+1 | Level: R+1 | Level: R+2 | D-15 | 0 | 3660 | 0.676734
444985 | R+1 | Level: R+1 | Level: R+2 | E-15 | 0 | 3660 | 0.676734
444987 | R+1 | Level: R+1 | Level: R+2 | F-15 | 0 | 3660 | 0.676734
444991 | R+1 | Level: R+1 | Level: R+2 | B-16 | 0 | 3660 | 0.676734
444993 | R+1 | Level: R+1 | Level: R+2 | C-16 | 0 | 3660 | 0.676734
444995 | R+1 | Level: R+1 | Level: R+2 | A-16 | 0 | 3660 | 0.676734
444997 | R+1 | Level: R+1 | Level: R+2 | D-16 | 0 | 3660 | 0.676734
445005 | R+1 | Level: R+1 | Level: R+2 | B-16(-2260.0) | 0 | 3660 | 0.676734
445007 | R+1 | Level: R+1 | Level: R+2 | C-16(-2260.0) | 0 | 3660 | 0.676734
445009 | R+1 | Level: R+1 | Level: R+2 | A-16(-2260.0) | 0 | 3660 | 0.676734
445011 | R+1 | Level: R+1 | Level: R+2 | D-16(-2260.0) | 0 | 3660 | 0.676734
445015 | R+1 | Level: R+1 | Level: R+2 | B-18 | 0 | 3660 | 0.676734
445017 | R+1 | Level: R+1 | Level: R+2 | C-18 | 0 | 3660 | 0.676734
445019 | R+1 | Level: R+1 | Level: R+2 | A-18 | 0 | 3660 | 0.676734
445023 | R+1 | Level: R+1 | Level: R+2 | 2-20(37205.0) | 0 | 3660 | 0.676734
445025 | R+1 | Level: R+1 | Level: R+2 | 3-20(37205.0) | 0 | 3660 | 0.676734
445027 | R+1 | Level: R+1 | Level: R+2 | 2-20(26825.0) | 0 | 3660 | 0.676734
445029 | R+1 | Level: R+1 | Level: R+2 | 3-20(26825.0) | 0 | 3660 | 0.676734
445031 | R+1 | Level: R+1 | Level: R+2 | 2-20(24995.0) | 0 | 3660 | 0.676734
445033 | R+1 | Level: R+1 | Level: R+2 | 3-20(24995.0) | 0 | 3660 | 0.676734
445035 | R+1 | Level: R+1 | Level: R+2 | 2-20(14615.0) | 0 | 3660 | 0.676734
445037 | R+1 | Level: R+1 | Level: R+2 | 3-20(14615.0) | 0 | 3660 | 0.676734
445039 | R+1 | Level: R+1 | Level: R+2 | 2-20(4235.0) | 0 | 3660 | 0.676734
445041 | R+1 | Level: R+1 | Level: R+2 | 3-20(4235.0) | 0 | 3660 | 0.676734
445043 | R+1 | Level: R+1 | Level: R+2 | 2-20(2405.0) | 0 | 3660 | 0.676734
445045 | R+1 | Level: R+1 | Level: R+2 | 3-20(2405.0) | 0 | 3660 | 0.676734
445047 | R+1 | Level: R+1 | Level: R+2 | 4-20(26825.0) | 0 | 3660 | 0.676734
445049 | R+1 | Level: R+1 | Level: R+2 | 4-20(24995.0) | 0 | 3660 | 0.676734
445051 | R+1 | Level: R+1 | Level: R+2 | 4-20(37205.0) | 0 | 3660 | 0.676734
445053 | R+1 | Level: R+1 | Level: R+2 | 4-20(14615.0) | 0 | 3660 | 0.676734
445055 | R+1 | Level: R+1 | Level: R+2 | 4-20(4235.0) | 0 | 3660 | 0.676734
445057 | R+1 | Level: R+1 | Level: R+2 | 4-20(2405.0) | 0 | 3660 | 0.676734
445059 | R+1 | Level: R+1 | Level: R+2 | 5-20(26825.0) | 0 | 3660 | 0.676734
445061 | R+1 | Level: R+1 | Level: R+2 | 5-20(24995.0) | 0 | 3660 | 0.676734
445063 | R+1 | Level: R+1 | Level: R+2 | 5-20(37205.0) | 0 | 3660 | 0.676734
445065 | R+1 | Level: R+1 | Level: R+2 | 5-20(14615.0) | 0 | 3660 | 0.676734
445067 | R+1 | Level: R+1 | Level: R+2 | 5-20(4235.0) | 0 | 3660 | 0.676734
445069 | R+1 | Level: R+1 | Level: R+2 | 5-20(2405.0) | 0 | 3660 | 0.676734
445071 | R+1 | Level: R+1 | Level: R+2 | 6-20(26825.0) | 0 | 3660 | 0.676734
445073 | R+1 | Level: R+1 | Level: R+2 | 6-20(24995.0) | 0 | 3660 | 0.676734
445075 | R+1 | Level: R+1 | Level: R+2 | 6-20(37205.0) | 0 | 3660 | 0.676734
445077 | R+1 | Level: R+1 | Level: R+2 | 6-20(14615.0) | 0 | 3660 | 0.676734
445079 | R+1 | Level: R+1 | Level: R+2 | 6-20(4235.0) | 0 | 3660 | 0.676734
445081 | R+1 | Level: R+1 | Level: R+2 | 6-20(2405.0) | 0 | 3660 | 0.676734
445083 | R+1 | Level: R+1 | Level: R+2 | 7-20(26825.0) | 0 | 3660 | 0.676734
445085 | R+1 | Level: R+1 | Level: R+2 | 7-20(24995.0) | 0 | 3660 | 0.676734
445087 | R+1 | Level: R+1 | Level: R+2 | 7-20(37205.0) | 0 | 3660 | 0.676734
445089 | R+1 | Level: R+1 | Level: R+2 | 7-20(14615.0) | 0 | 3660 | 0.676734
445091 | R+1 | Level: R+1 | Level: R+2 | 7-20(4235.0) | 0 | 3660 | 0.676734
445093 | R+1 | Level: R+1 | Level: R+2 | 7-20(2405.0) | 0 | 3660 | 0.676734
445095 | R+1 | Level: R+1 | Level: R+2 | 8-20(26825.0) | 0 | 3660 | 0.676734
445097 | R+1 | Level: R+1 | Level: R+2 | 8-20(24995.0) | 0 | 3660 | 0.676734
445099 | R+1 | Level: R+1 | Level: R+2 | 8-20(37205.0) | 0 | 3660 | 0.676734
445101 | R+1 | Level: R+1 | Level: R+2 | 8-20(14615.0) | 0 | 3660 | 0.676734
445103 | R+1 | Level: R+1 | Level: R+2 | 8-20(4235.0) | 0 | 3660 | 0.676734
445105 | R+1 | Level: R+1 | Level: R+2 | 8-20(2405.0) | 0 | 3660 | 0.676734
445107 | R+1 | Level: R+1 | Level: R+2 | 9-20(26825.0) | 0 | 3660 | 0.676734
445109 | R+1 | Level: R+1 | Level: R+2 | 9-20(24995.0) | 0 | 3660 | 0.676734
445111 | R+1 | Level: R+1 | Level: R+2 | 9-20(37205.0) | 0 | 3660 | 0.676734
445113 | R+1 | Level: R+1 | Level: R+2 | 9-20(14615.0) | 0 | 3660 | 0.676734
445115 | R+1 | Level: R+1 | Level: R+2 | 9-20(4235.0) | 0 | 3660 | 0.676734
445117 | R+1 | Level: R+1 | Level: R+2 | 9-20(2405.0) | 0 | 3660 | 0.676734
445119 | R+1 | Level: R+1 | Level: R+2 | 10-20(26825.0) | 0 | 3660 | 0.676734
445121 | R+1 | Level: R+1 | Level: R+2 | 10-20(24995.0) | 0 | 3660 | 0.676734
445123 | R+1 | Level: R+1 | Level: R+2 | 10-20(37205.0) | 0 | 3660 | 0.676734
445125 | R+1 | Level: R+1 | Level: R+2 | 10-20(14615.0) | 0 | 3660 | 0.676734
445127 | R+1 | Level: R+1 | Level: R+2 | 10-20(4235.0) | 0 | 3660 | 0.676734
445129 | R+1 | Level: R+1 | Level: R+2 | 10-20(2405.0) | 0 | 3660 | 0.676734
445131 | R+1 | Level: R+1 | Level: R+2 | 11-20(26825.0) | 0 | 3660 | 0.676734
445133 | R+1 | Level: R+1 | Level: R+2 | 11-20(24995.0) | 0 | 3660 | 0.676734
445135 | R+1 | Level: R+1 | Level: R+2 | 11-20(37205.0) | 0 | 3660 | 0.676734
445137 | R+1 | Level: R+1 | Level: R+2 | 11-20(14615.0) | 0 | 3660 | 0.676734
445139 | R+1 | Level: R+1 | Level: R+2 | 11-20(4235.0) | 0 | 3660 | 0.676734
445141 | R+1 | Level: R+1 | Level: R+2 | 11-20(2405.0) | 0 | 3660 | 0.676734
445143 | R+1 | Level: R+1 | Level: R+2 | 12-20(26825.0) | 0 | 3660 | 0.676734
445145 | R+1 | Level: R+1 | Level: R+2 | 12-20(24995.0) | 0 | 3660 | 0.676734
445147 | R+1 | Level: R+1 | Level: R+2 | 12-20(37205.0) | 0 | 3660 | 0.676734
445149 | R+1 | Level: R+1 | Level: R+2 | 12-20(14615.0) | 0 | 3660 | 0.676734
445151 | R+1 | Level: R+1 | Level: R+2 | 12-20(4235.0) | 0 | 3660 | 0.676734
445153 | R+1 | Level: R+1 | Level: R+2 | 12-20(2405.0) | 0 | 3660 | 0.676734
445155 | R+1 | Level: R+1 | Level: R+2 | 13-20(26825.0) | 0 | 3660 | 0.676734
445157 | R+1 | Level: R+1 | Level: R+2 | 13-20(24995.0) | 0 | 3660 | 0.676734
445159 | R+1 | Level: R+1 | Level: R+2 | 13-20(37205.0) | 0 | 3660 | 0.676734
445163 | R+1 | Level: R+1 | Level: R+2 | 13-20(14615.0) | 0 | 3660 | 0.676734
445165 | R+1 | Level: R+1 | Level: R+2 | 13-20(4235.0) | 0 | 3660 | 0.676734
445167 | R+1 | Level: R+1 | Level: R+2 | 13-20(2405.0) | 0 | 3660 | 0.676734
445169 | R+1 | Level: R+1 | Level: R+2 | 14-20(26825.0) | 0 | 3660 | 0.676734
445171 | R+1 | Level: R+1 | Level: R+2 | 14-20(24995.0) | 0 | 3660 | 0.676734
445173 | R+1 | Level: R+1 | Level: R+2 | 14-20(37205.0) | 0 | 3660 | 0.676734
445177 | R+1 | Level: R+1 | Level: R+2 | 14-20(14615.0) | 0 | 3660 | 0.676734
445179 | R+1 | Level: R+1 | Level: R+2 | 14-20(4235.0) | 0 | 3660 | 0.676734
445181 | R+1 | Level: R+1 | Level: R+2 | 14-20(2405.0) | 0 | 3660 | 0.676734
445183 | R+1 | Level: R+1 | Level: R+2 | 15-20(26825.0) | 0 | 3660 | 0.676734
445185 | R+1 | Level: R+1 | Level: R+2 | 15-20(24995.0) | 0 | 3660 | 0.676734
445187 | R+1 | Level: R+1 | Level: R+2 | 15-20(37205.0) | 0 | 3660 | 0.676734
445191 | R+1 | Level: R+1 | Level: R+2 | 15-20(14615.0) | 0 | 3660 | 0.676734
445193 | R+1 | Level: R+1 | Level: R+2 | 15-20(4235.0) | 0 | 3660 | 0.676734
445195 | R+1 | Level: R+1 | Level: R+2 | 15-20(2405.0) | 0 | 3660 | 0.676734
445197 | R+1 | Level: R+1 | Level: R+2 | 16-20(26825.0) | 0 | 3660 | 0.676734
445199 | R+1 | Level: R+1 | Level: R+2 | 16-20(24995.0) | 0 | 3660 | 0.676734
445203 | R+1 | Level: R+1 | Level: R+2 | 16-20(14615.0) | 0 | 3660 | 0.676734
445209 | R+1 | Level: R+1 | Level: R+2 | 16(-2260.0)-20(26825.0) | 0 | 3660 | 0.676734
445211 | R+1 | Level: R+1 | Level: R+2 | 16(-2260.0)-20(24995.0) | 0 | 3660 | 0.676734
445217 | R+1 | Level: R+1 | Level: R+2 | 18-20(26825.0) | 0 | 3660 | 0.676734
445219 | R+1 | Level: R+1 | Level: R+2 | 18-20(24995.0) | 0 | 3660 | 0.676734
445221 | R+1 | Level: R+1 | Level: R+2 | 18-20(37205.0) | 0 | 3660 | 0.676734
446135 | R+2 | Level: R+2 | Level: TOP | A-2 | 0 | 3910 | 0.722959
446139 | R+2 | Level: R+2 | Level: TOP | A-3 | 0 | 3910 | 0.722959
446141 | R+2 | Level: R+2 | Level: TOP | B-2 | 0 | 3910 | 0.722959
446143 | R+2 | Level: R+2 | Level: TOP | B-3 | 0 | 3910 | 0.722959
446145 | R+2 | Level: R+2 | Level: TOP | C-2 | 0 | 3910 | 0.722959
446147 | R+2 | Level: R+2 | Level: TOP | C-3 | 0 | 3910 | 0.722959
446149 | R+2 | Level: R+2 | Level: TOP | D-2 | 0 | 3910 | 0.722959
446151 | R+2 | Level: R+2 | Level: TOP | D-3 | 0 | 3910 | 0.722959
446153 | R+2 | Level: R+2 | Level: TOP | E-2 | 0 | 3910 | 0.722959
446155 | R+2 | Level: R+2 | Level: TOP | E-3 | 0 | 3910 | 0.722959
446157 | R+2 | Level: R+2 | Level: TOP | F-2 | 0 | 3910 | 0.722959
446159 | R+2 | Level: R+2 | Level: TOP | F-3 | 0 | 3910 | 0.722959
446163 | R+2 | Level: R+2 | Level: TOP | B-4 | 0 | 3910 | 0.722959
446165 | R+2 | Level: R+2 | Level: TOP | C-4 | 0 | 3910 | 0.722959
446167 | R+2 | Level: R+2 | Level: TOP | A-4 | 0 | 3910 | 0.722959
446169 | R+2 | Level: R+2 | Level: TOP | D-4 | 0 | 3910 | 0.722959
446171 | R+2 | Level: R+2 | Level: TOP | E-4 | 0 | 3910 | 0.722959
446173 | R+2 | Level: R+2 | Level: TOP | F-4 | 0 | 3910 | 0.722959
446177 | R+2 | Level: R+2 | Level: TOP | B-5 | 0 | 3910 | 0.722959
446179 | R+2 | Level: R+2 | Level: TOP | C-5 | 0 | 3910 | 0.722959
446181 | R+2 | Level: R+2 | Level: TOP | A-5 | 0 | 3910 | 0.722959
446183 | R+2 | Level: R+2 | Level: TOP | D-5 | 0 | 3910 | 0.722959
446185 | R+2 | Level: R+2 | Level: TOP | E-5 | 0 | 3910 | 0.722959
446187 | R+2 | Level: R+2 | Level: TOP | F-5 | 0 | 3910 | 0.722959
446191 | R+2 | Level: R+2 | Level: TOP | B-6 | 0 | 3910 | 0.722959
446193 | R+2 | Level: R+2 | Level: TOP | C-6 | 0 | 3910 | 0.722959
446195 | R+2 | Level: R+2 | Level: TOP | A-6 | 0 | 3910 | 0.722959
446197 | R+2 | Level: R+2 | Level: TOP | D-6 | 0 | 3910 | 0.722959
446199 | R+2 | Level: R+2 | Level: TOP | E-6 | 0 | 3910 | 0.722959
446201 | R+2 | Level: R+2 | Level: TOP | F-6 | 0 | 3910 | 0.722959
446205 | R+2 | Level: R+2 | Level: TOP | B-7 | 0 | 3910 | 0.722959
446207 | R+2 | Level: R+2 | Level: TOP | C-7 | 0 | 3910 | 0.722959
446209 | R+2 | Level: R+2 | Level: TOP | A-7 | 0 | 3910 | 0.722959
446211 | R+2 | Level: R+2 | Level: TOP | D-7 | 0 | 3910 | 0.722959
446213 | R+2 | Level: R+2 | Level: TOP | E-7 | 0 | 3910 | 0.722959
446215 | R+2 | Level: R+2 | Level: TOP | F-7 | 0 | 3910 | 0.722959
446219 | R+2 | Level: R+2 | Level: TOP | B-8 | 0 | 3910 | 0.722959
446221 | R+2 | Level: R+2 | Level: TOP | C-8 | 0 | 3910 | 0.722959
446223 | R+2 | Level: R+2 | Level: TOP | A-8 | 0 | 3910 | 0.722959
446225 | R+2 | Level: R+2 | Level: TOP | D-8 | 0 | 3910 | 0.722959
446227 | R+2 | Level: R+2 | Level: TOP | E-8 | 0 | 3910 | 0.722959
446229 | R+2 | Level: R+2 | Level: TOP | F-8 | 0 | 3910 | 0.722959
446233 | R+2 | Level: R+2 | Level: TOP | B-9 | 0 | 3910 | 0.722959
446235 | R+2 | Level: R+2 | Level: TOP | C-9 | 0 | 3910 | 0.722959
446237 | R+2 | Level: R+2 | Level: TOP | A-9 | 0 | 3910 | 0.722959
446239 | R+2 | Level: R+2 | Level: TOP | D-9 | 0 | 3910 | 0.722959
446241 | R+2 | Level: R+2 | Level: TOP | E-9 | 0 | 3910 | 0.722959
446243 | R+2 | Level: R+2 | Level: TOP | F-9 | 0 | 3910 | 0.722959
446247 | R+2 | Level: R+2 | Level: TOP | B-10 | 0 | 3910 | 0.722959
446249 | R+2 | Level: R+2 | Level: TOP | C-10 | 0 | 3910 | 0.722959
446251 | R+2 | Level: R+2 | Level: TOP | A-10 | 0 | 3910 | 0.722959
446253 | R+2 | Level: R+2 | Level: TOP | D-10 | 0 | 3910 | 0.722959
446255 | R+2 | Level: R+2 | Level: TOP | E-10 | 0 | 3910 | 0.722959
446257 | R+2 | Level: R+2 | Level: TOP | F-10 | 0 | 3910 | 0.722959
446261 | R+2 | Level: R+2 | Level: TOP | B-11 | 0 | 3910 | 0.722959
446263 | R+2 | Level: R+2 | Level: TOP | C-11 | 0 | 3910 | 0.722959
446265 | R+2 | Level: R+2 | Level: TOP | A-11 | 0 | 3910 | 0.722959
446267 | R+2 | Level: R+2 | Level: TOP | D-11 | 0 | 3910 | 0.722959
446269 | R+2 | Level: R+2 | Level: TOP | E-11 | 0 | 3910 | 0.722959
446271 | R+2 | Level: R+2 | Level: TOP | F-11 | 0 | 3910 | 0.722959
446275 | R+2 | Level: R+2 | Level: TOP | B-12 | 0 | 3910 | 0.722959
446277 | R+2 | Level: R+2 | Level: TOP | C-12 | 0 | 3910 | 0.722959
446279 | R+2 | Level: R+2 | Level: TOP | A-12 | 0 | 3910 | 0.722959
446281 | R+2 | Level: R+2 | Level: TOP | D-12 | 0 | 3910 | 0.722959
446283 | R+2 | Level: R+2 | Level: TOP | E-12 | 0 | 3910 | 0.722959
446285 | R+2 | Level: R+2 | Level: TOP | F-12 | 0 | 3910 | 0.722959
446289 | R+2 | Level: R+2 | Level: TOP | B-13 | 0 | 3910 | 0.722959
446291 | R+2 | Level: R+2 | Level: TOP | C-13 | 0 | 3910 | 0.722959
446293 | R+2 | Level: R+2 | Level: TOP | A-13 | 0 | 3910 | 0.722959
446295 | R+2 | Level: R+2 | Level: TOP | D-13 | 0 | 3910 | 0.722959
446297 | R+2 | Level: R+2 | Level: TOP | E-13 | 0 | 3910 | 0.722959
446299 | R+2 | Level: R+2 | Level: TOP | F-13 | 0 | 3910 | 0.722959
446303 | R+2 | Level: R+2 | Level: TOP | B-14 | 0 | 3910 | 0.722959
446305 | R+2 | Level: R+2 | Level: TOP | C-14 | 0 | 3910 | 0.722959
446307 | R+2 | Level: R+2 | Level: TOP | A-14 | 0 | 3910 | 0.722959
446309 | R+2 | Level: R+2 | Level: TOP | D-14 | 0 | 3910 | 0.722959
446311 | R+2 | Level: R+2 | Level: TOP | E-14 | 0 | 3910 | 0.722959
446313 | R+2 | Level: R+2 | Level: TOP | F-14 | 0 | 3910 | 0.722959
446317 | R+2 | Level: R+2 | Level: TOP | B-15 | 0 | 3910 | 0.722959
446319 | R+2 | Level: R+2 | Level: TOP | C-15 | 0 | 3910 | 0.722959
446321 | R+2 | Level: R+2 | Level: TOP | A-15 | 0 | 3910 | 0.722959
446323 | R+2 | Level: R+2 | Level: TOP | D-15 | 0 | 3910 | 0.722959
446325 | R+2 | Level: R+2 | Level: TOP | E-15 | 0 | 3910 | 0.722959
446327 | R+2 | Level: R+2 | Level: TOP | F-15 | 0 | 3910 | 0.722959
446331 | R+2 | Level: R+2 | Level: TOP | B-16 | 0 | 3910 | 0.722959
446333 | R+2 | Level: R+2 | Level: TOP | C-16 | 0 | 3910 | 0.722959
446335 | R+2 | Level: R+2 | Level: TOP | A-16 | 0 | 3910 | 0.722959
446337 | R+2 | Level: R+2 | Level: TOP | D-16 | 0 | 3910 | 0.722959
446345 | R+2 | Level: R+2 | Level: TOP | B-16(-2260.0) | 0 | 3910 | 0.722959
446347 | R+2 | Level: R+2 | Level: TOP | C-16(-2260.0) | 0 | 3910 | 0.722959
446349 | R+2 | Level: R+2 | Level: TOP | A-16(-2260.0) | 0 | 3910 | 0.722959
446355 | R+2 | Level: R+2 | Level: TOP | B-18 | 0 | 3910 | 0.722959
446357 | R+2 | Level: R+2 | Level: TOP | C-18 | 0 | 3910 | 0.722959
446359 | R+2 | Level: R+2 | Level: TOP | A-18 | 0 | 3910 | 0.722959
446363 | R+2 | Level: R+2 | Level: TOP | 2-20(37205.0) | 0 | 3910 | 0.722959
446365 | R+2 | Level: R+2 | Level: TOP | 3-20(37205.0) | 0 | 3910 | 0.722959
446367 | R+2 | Level: R+2 | Level: TOP | 2-20(26825.0) | 0 | 3910 | 0.722959
446369 | R+2 | Level: R+2 | Level: TOP | 3-20(26825.0) | 0 | 3910 | 0.722959
446371 | R+2 | Level: R+2 | Level: TOP | 2-20(24995.0) | 0 | 3910 | 0.722959
446373 | R+2 | Level: R+2 | Level: TOP | 3-20(24995.0) | 0 | 3910 | 0.722959
446375 | R+2 | Level: R+2 | Level: TOP | 2-20(14615.0) | 0 | 3910 | 0.722959
446377 | R+2 | Level: R+2 | Level: TOP | 3-20(14615.0) | 0 | 3910 | 0.722959
446379 | R+2 | Level: R+2 | Level: TOP | 2-20(4235.0) | 0 | 3910 | 0.722959
446381 | R+2 | Level: R+2 | Level: TOP | 3-20(4235.0) | 0 | 3910 | 0.722959
446383 | R+2 | Level: R+2 | Level: TOP | 2-20(2405.0) | 0 | 3910 | 0.722959
446385 | R+2 | Level: R+2 | Level: TOP | 3-20(2405.0) | 0 | 3910 | 0.722959
446387 | R+2 | Level: R+2 | Level: TOP | 4-20(26825.0) | 0 | 3910 | 0.722959
446389 | R+2 | Level: R+2 | Level: TOP | 4-20(24995.0) | 0 | 3910 | 0.722959
446391 | R+2 | Level: R+2 | Level: TOP | 4-20(37205.0) | 0 | 3910 | 0.722959
446393 | R+2 | Level: R+2 | Level: TOP | 4-20(14615.0) | 0 | 3910 | 0.722959
446395 | R+2 | Level: R+2 | Level: TOP | 4-20(4235.0) | 0 | 3910 | 0.722959
446397 | R+2 | Level: R+2 | Level: TOP | 4-20(2405.0) | 0 | 3910 | 0.722959
446399 | R+2 | Level: R+2 | Level: TOP | 5-20(26825.0) | 0 | 3910 | 0.722959
446401 | R+2 | Level: R+2 | Level: TOP | 5-20(24995.0) | 0 | 3910 | 0.722959
446403 | R+2 | Level: R+2 | Level: TOP | 5-20(37205.0) | 0 | 3910 | 0.722959
446405 | R+2 | Level: R+2 | Level: TOP | 5-20(14615.0) | 0 | 3910 | 0.722959
446407 | R+2 | Level: R+2 | Level: TOP | 5-20(4235.0) | 0 | 3910 | 0.722959
446409 | R+2 | Level: R+2 | Level: TOP | 5-20(2405.0) | 0 | 3910 | 0.722959
446411 | R+2 | Level: R+2 | Level: TOP | 6-20(26825.0) | 0 | 3910 | 0.722959
446413 | R+2 | Level: R+2 | Level: TOP | 6-20(24995.0) | 0 | 3910 | 0.722959
446415 | R+2 | Level: R+2 | Level: TOP | 6-20(37205.0) | 0 | 3910 | 0.722959
446417 | R+2 | Level: R+2 | Level: TOP | 6-20(14615.0) | 0 | 3910 | 0.722959
446419 | R+2 | Level: R+2 | Level: TOP | 6-20(4235.0) | 0 | 3910 | 0.722959
446421 | R+2 | Level: R+2 | Level: TOP | 6-20(2405.0) | 0 | 3910 | 0.722959
446423 | R+2 | Level: R+2 | Level: TOP | 7-20(26825.0) | 0 | 3910 | 0.722959
446425 | R+2 | Level: R+2 | Level: TOP | 7-20(24995.0) | 0 | 3910 | 0.722959
446427 | R+2 | Level: R+2 | Level: TOP | 7-20(37205.0) | 0 | 3910 | 0.722959
446429 | R+2 | Level: R+2 | Level: TOP | 7-20(14615.0) | 0 | 3910 | 0.722959
446431 | R+2 | Level: R+2 | Level: TOP | 7-20(4235.0) | 0 | 3910 | 0.722959
446433 | R+2 | Level: R+2 | Level: TOP | 7-20(2405.0) | 0 | 3910 | 0.722959
446435 | R+2 | Level: R+2 | Level: TOP | 8-20(26825.0) | 0 | 3910 | 0.722959
446437 | R+2 | Level: R+2 | Level: TOP | 8-20(24995.0) | 0 | 3910 | 0.722959
446439 | R+2 | Level: R+2 | Level: TOP | 8-20(37205.0) | 0 | 3910 | 0.722959
446441 | R+2 | Level: R+2 | Level: TOP | 8-20(14615.0) | 0 | 3910 | 0.722959
446443 | R+2 | Level: R+2 | Level: TOP | 8-20(4235.0) | 0 | 3910 | 0.722959
446445 | R+2 | Level: R+2 | Level: TOP | 8-20(2405.0) | 0 | 3910 | 0.722959
446447 | R+2 | Level: R+2 | Level: TOP | 9-20(26825.0) | 0 | 3910 | 0.722959
446449 | R+2 | Level: R+2 | Level: TOP | 9-20(24995.0) | 0 | 3910 | 0.722959
446451 | R+2 | Level: R+2 | Level: TOP | 9-20(37205.0) | 0 | 3910 | 0.722959
446453 | R+2 | Level: R+2 | Level: TOP | 9-20(14615.0) | 0 | 3910 | 0.722959
446455 | R+2 | Level: R+2 | Level: TOP | 9-20(4235.0) | 0 | 3910 | 0.722959
446457 | R+2 | Level: R+2 | Level: TOP | 9-20(2405.0) | 0 | 3910 | 0.722959
446459 | R+2 | Level: R+2 | Level: TOP | 10-20(26825.0) | 0 | 3910 | 0.722959
446461 | R+2 | Level: R+2 | Level: TOP | 10-20(24995.0) | 0 | 3910 | 0.722959
446463 | R+2 | Level: R+2 | Level: TOP | 10-20(37205.0) | 0 | 3910 | 0.722959
446465 | R+2 | Level: R+2 | Level: TOP | 10-20(14615.0) | 0 | 3910 | 0.722959
446467 | R+2 | Level: R+2 | Level: TOP | 10-20(4235.0) | 0 | 3910 | 0.722959
446469 | R+2 | Level: R+2 | Level: TOP | 10-20(2405.0) | 0 | 3910 | 0.722959
446471 | R+2 | Level: R+2 | Level: TOP | 11-20(26825.0) | 0 | 3910 | 0.722959
446473 | R+2 | Level: R+2 | Level: TOP | 11-20(24995.0) | 0 | 3910 | 0.722959
446475 | R+2 | Level: R+2 | Level: TOP | 11-20(37205.0) | 0 | 3910 | 0.722959
446477 | R+2 | Level: R+2 | Level: TOP | 11-20(14615.0) | 0 | 3910 | 0.722959
446479 | R+2 | Level: R+2 | Level: TOP | 11-20(4235.0) | 0 | 3910 | 0.722959
446481 | R+2 | Level: R+2 | Level: TOP | 11-20(2405.0) | 0 | 3910 | 0.722959
446483 | R+2 | Level: R+2 | Level: TOP | 12-20(26825.0) | 0 | 3910 | 0.722959
446485 | R+2 | Level: R+2 | Level: TOP | 12-20(24995.0) | 0 | 3910 | 0.722959
446487 | R+2 | Level: R+2 | Level: TOP | 12-20(37205.0) | 0 | 3910 | 0.722959
446489 | R+2 | Level: R+2 | Level: TOP | 12-20(14615.0) | 0 | 3910 | 0.722959
446491 | R+2 | Level: R+2 | Level: TOP | 12-20(4235.0) | 0 | 3910 | 0.722959
446493 | R+2 | Level: R+2 | Level: TOP | 12-20(2405.0) | 0 | 3910 | 0.722959
446495 | R+2 | Level: R+2 | Level: TOP | 13-20(26825.0) | 0 | 3910 | 0.722959
446497 | R+2 | Level: R+2 | Level: TOP | 13-20(24995.0) | 0 | 3910 | 0.722959
446499 | R+2 | Level: R+2 | Level: TOP | 13-20(37205.0) | 0 | 3910 | 0.722959
446503 | R+2 | Level: R+2 | Level: TOP | 13-20(14615.0) | 0 | 3910 | 0.722959
446505 | R+2 | Level: R+2 | Level: TOP | 13-20(4235.0) | 0 | 3910 | 0.722959
446507 | R+2 | Level: R+2 | Level: TOP | 13-20(2405.0) | 0 | 3910 | 0.722959
446509 | R+2 | Level: R+2 | Level: TOP | 14-20(26825.0) | 0 | 3910 | 0.722959
446511 | R+2 | Level: R+2 | Level: TOP | 14-20(24995.0) | 0 | 3910 | 0.722959
446513 | R+2 | Level: R+2 | Level: TOP | 14-20(37205.0) | 0 | 3910 | 0.722959
446517 | R+2 | Level: R+2 | Level: TOP | 14-20(14615.0) | 0 | 3910 | 0.722959
446519 | R+2 | Level: R+2 | Level: TOP | 14-20(4235.0) | 0 | 3910 | 0.722959
446521 | R+2 | Level: R+2 | Level: TOP | 14-20(2405.0) | 0 | 3910 | 0.722959
446523 | R+2 | Level: R+2 | Level: TOP | 15-20(26825.0) | 0 | 3910 | 0.722959
446525 | R+2 | Level: R+2 | Level: TOP | 15-20(24995.0) | 0 | 3910 | 0.722959
446527 | R+2 | Level: R+2 | Level: TOP | 15-20(37205.0) | 0 | 3910 | 0.722959
446531 | R+2 | Level: R+2 | Level: TOP | 15-20(14615.0) | 0 | 3910 | 0.722959
446533 | R+2 | Level: R+2 | Level: TOP | 15-20(4235.0) | 0 | 3910 | 0.722959
446535 | R+2 | Level: R+2 | Level: TOP | 15-20(2405.0) | 0 | 3910 | 0.722959
446537 | R+2 | Level: R+2 | Level: TOP | 16-20(26825.0) | 0 | 3910 | 0.722959
446539 | R+2 | Level: R+2 | Level: TOP | 16-20(24995.0) | 0 | 3910 | 0.722959
446543 | R+2 | Level: R+2 | Level: TOP | 16-20(14615.0) | 0 | 3910 | 0.722959
446549 | R+2 | Level: R+2 | Level: TOP | 16(-2260.0)-20(26825.0) | 0 | 3910 | 0.722959
446551 | R+2 | Level: R+2 | Level: TOP | 16(-2260.0)-20(24995.0) | 0 | 3910 | 0.722959
446557 | R+2 | Level: R+2 | Level: TOP | 18-20(26825.0) | 0 | 3910 | 0.722959
446559 | R+2 | Level: R+2 | Level: TOP | 18-20(24995.0) | 0 | 3910 | 0.722959
446561 | R+2 | Level: R+2 | Level: TOP | 18-20(37205.0) | 0 | 3910 | 0.722959
485215 | RDC | Level: RDC | Level: R+1 | 16-20(37205.0) | 0 | 3660 | 0.676734
485265 | RDC | Level: RDC | Level: R+1 | 16(-2260.0)-20(37205.0) | 0 | 3660 | 0.676734
485280 | RDC | Level: RDC | Level: R+1 | 16(-2260.0)-20(37205.0) | 0 | 3660 | 0.676734
485311 | R+1 | Level: R+1 | Level: R+2 | 16-20(37205.0) | 0 | 3660 | 0.676734
485313 | RDC | Level: RDC | Level: R+1 | 16(-2260.0)-20(37205.0) | 0 | 3660 | 0.676734
485355 | R+2 | Level: R+2 | Level: TOP | 16-20(37205.0) | 0 | 3910 | 0.722959
485416 | R+1 | Level: R+1 | Level: R+2 | 16(-2260.0)-20(37205.0) | 0 | 3660 | 0.676734
485482 | R+2 | Level: R+2 | Level: TOP | 16(-2260.0)-20(37205.0) | 0 | 3910 | 0.722959
545167 | R+1 | Level: R+1 | Level: R+2 | 1-20(37205.0) | 0 | 3660 | 0.676734
548625 | R+2 | Level: R+2 | Level: TOP | 1-20(37205.0) | 0 | 3910 | 0.722959
556782 | RDC | Level: RDC | Level: R+1 | 1-20(37205.0) | 0 | 3660 | 0.676734

# IfcCovering: Basic Ceiling:Generic (120)
Type - PredefinedType: CEILING
Type - Analytical Properties - Roughness: 3; Absorptance: 0.7
Type - Identity Data - Keynote: K; Type Name: Generic
Type - Materials and Finishes - Material: Aluminum
Type - Other - Category: Ceilings; Family Name: Basic Ceiling
Type - Pset_CoveringCommon - Reference: Generic; Material: Aluminum
Type - Pset_ElementShading - Roughness: 914.4 mm
Type - Pset_ProductRequirements - Category: Ceilings
Type - Pset_QuantityTakeOff - Reference: Generic
Constraints - Room Bounding: yes; Height Offset From Level: 2959 mm
Identity Data - Comments: ThisIsExisiting
Other - Family: Basic Ceiling: Generic; Family and Type: Basic Ceiling: Generic; Type: Basic Ceiling: Generic; Type Id: Basic Ceiling: Generic
Phasing - Phase Created: Existing
Name (Basic Ceiling:Generic:...) | In | Level | Area (m2) | Perimeter (mm)
560115 | R+1 | Level: R+1 | 0.602 | 3660
560204 | R+1 | Level: R+1 | 0.602 | 3660
560225 | R+1 | Level: R+1 | 0.602 | 3660
560234 | R+1 | Level: R+1 | 0.602 | 3660
560243 | R+1 | Level: R+1 | 0.602 | 3660
560252 | R+1 | Level: R+1 | 0.602 | 3660
560261 | R+1 | Level: R+1 | 0.602 | 3660
560270 | R+1 | Level: R+1 | 0.602 | 3660
560279 | R+1 | Level: R+1 | 0.602 | 3660
560288 | R+1 | Level: R+1 | 0.602 | 3660
560297 | R+1 | Level: R+1 | 0.602 | 3660
560306 | R+1 | Level: R+1 | 0.602 | 3660
560315 | R+1 | Level: R+1 | 0.602 | 3660
560324 | R+1 | Level: R+1 | 0.602 | 3660
560336 | R+1 | Level: R+1 | 0.604375 | 3663.39
560393 | R+1 | Level: R+1 | 0.602 | 3660
560400 | R+1 | Level: R+1 | 0.602 | 3660
560407 | R+1 | Level: R+1 | 0.602 | 3660
560414 | R+1 | Level: R+1 | 0.602 | 3660
560421 | R+1 | Level: R+1 | 0.602 | 3660
560428 | R+1 | Level: R+1 | 0.602 | 3660
560435 | R+1 | Level: R+1 | 0.602 | 3660
560442 | R+1 | Level: R+1 | 0.602 | 3660
560449 | R+1 | Level: R+1 | 0.602 | 3660
560456 | R+1 | Level: R+1 | 0.602 | 3660
560463 | R+1 | Level: R+1 | 0.602 | 3660
560470 | R+1 | Level: R+1 | 0.602 | 3660
560477 | R+1 | Level: R+1 | 0.602 | 3660
560484 | R+1 | Level: R+1 | 0.602 | 3660
560491 | R+1 | Level: R+1 | 0.604375 | 3663.39
560513 | R+1 | Level: R+1 | 0.602 | 3660
560520 | R+1 | Level: R+1 | 0.602 | 3660
560527 | R+1 | Level: R+1 | 0.602 | 3660
560534 | R+1 | Level: R+1 | 0.602 | 3660
560541 | R+1 | Level: R+1 | 0.602 | 3660
560548 | R+1 | Level: R+1 | 0.602 | 3660
560555 | R+1 | Level: R+1 | 0.602 | 3660
560562 | R+1 | Level: R+1 | 0.602 | 3660
560569 | R+1 | Level: R+1 | 0.602 | 3660
560576 | R+1 | Level: R+1 | 0.602 | 3660
560583 | R+1 | Level: R+1 | 0.602 | 3660
560590 | R+1 | Level: R+1 | 0.602 | 3660
560597 | R+1 | Level: R+1 | 0.602 | 3660
560604 | R+1 | Level: R+1 | 0.602 | 3660
560611 | R+1 | Level: R+1 | 0.604375 | 3663.39
560618 | R+1 | Level: R+1 | 0.602 | 3660
560625 | R+1 | Level: R+1 | 0.602 | 3660
560632 | R+1 | Level: R+1 | 0.602 | 3660
560639 | R+1 | Level: R+1 | 0.602 | 3660
560646 | R+1 | Level: R+1 | 0.602 | 3660
560653 | R+1 | Level: R+1 | 0.602 | 3660
560660 | R+1 | Level: R+1 | 0.602 | 3660
560667 | R+1 | Level: R+1 | 0.602 | 3660
560674 | R+1 | Level: R+1 | 0.602 | 3660
560681 | R+1 | Level: R+1 | 0.602 | 3660
560688 | R+1 | Level: R+1 | 0.602 | 3660
560695 | R+1 | Level: R+1 | 0.602 | 3660
560702 | R+1 | Level: R+1 | 0.602 | 3660
560709 | R+1 | Level: R+1 | 0.602 | 3660
560716 | R+1 | Level: R+1 | 0.604375 | 3663.39
560860 | R+2 | Level: R+2 | 0.602 | 3660
560867 | R+2 | Level: R+2 | 0.602 | 3660
560874 | R+2 | Level: R+2 | 0.602 | 3660
560881 | R+2 | Level: R+2 | 0.602 | 3660
560888 | R+2 | Level: R+2 | 0.602 | 3660
560895 | R+2 | Level: R+2 | 0.602 | 3660
560902 | R+2 | Level: R+2 | 0.602 | 3660
560909 | R+2 | Level: R+2 | 0.602 | 3660
560916 | R+2 | Level: R+2 | 0.602 | 3660
560923 | R+2 | Level: R+2 | 0.602 | 3660
560930 | R+2 | Level: R+2 | 0.602 | 3660
560937 | R+2 | Level: R+2 | 0.602 | 3660
560944 | R+2 | Level: R+2 | 0.602 | 3660
560951 | R+2 | Level: R+2 | 0.602 | 3660
560958 | R+2 | Level: R+2 | 0.604375 | 3663.39
560965 | R+2 | Level: R+2 | 0.602 | 3660
560972 | R+2 | Level: R+2 | 0.602 | 3660
560979 | R+2 | Level: R+2 | 0.602 | 3660
560986 | R+2 | Level: R+2 | 0.602 | 3660
560993 | R+2 | Level: R+2 | 0.602 | 3660
561000 | R+2 | Level: R+2 | 0.602 | 3660
561007 | R+2 | Level: R+2 | 0.602 | 3660
561014 | R+2 | Level: R+2 | 0.602 | 3660
561021 | R+2 | Level: R+2 | 0.602 | 3660
561028 | R+2 | Level: R+2 | 0.602 | 3660
561035 | R+2 | Level: R+2 | 0.602 | 3660
561042 | R+2 | Level: R+2 | 0.602 | 3660
561049 | R+2 | Level: R+2 | 0.602 | 3660
561056 | R+2 | Level: R+2 | 0.602 | 3660
561063 | R+2 | Level: R+2 | 0.604375 | 3663.39
561070 | R+2 | Level: R+2 | 0.602 | 3660
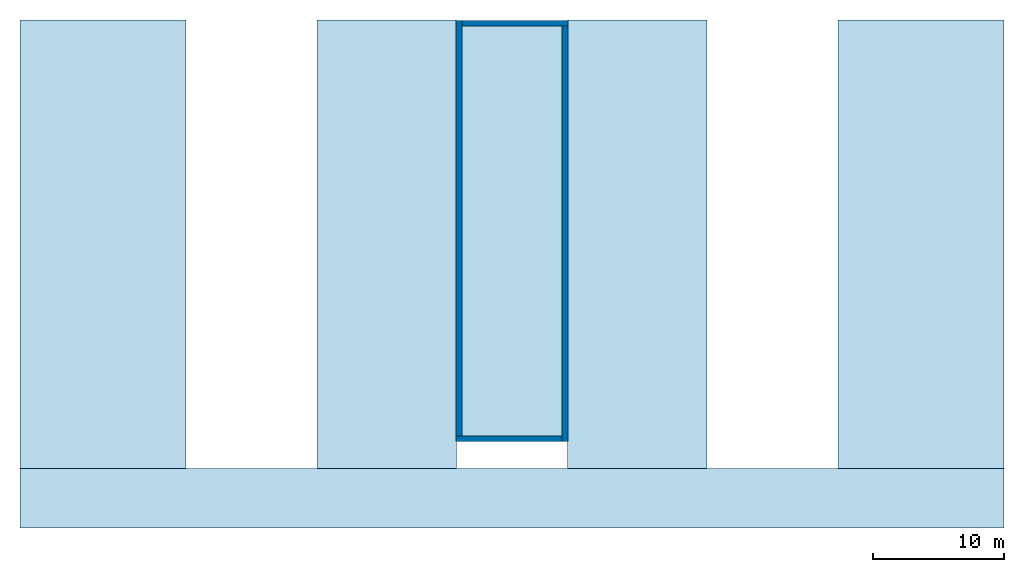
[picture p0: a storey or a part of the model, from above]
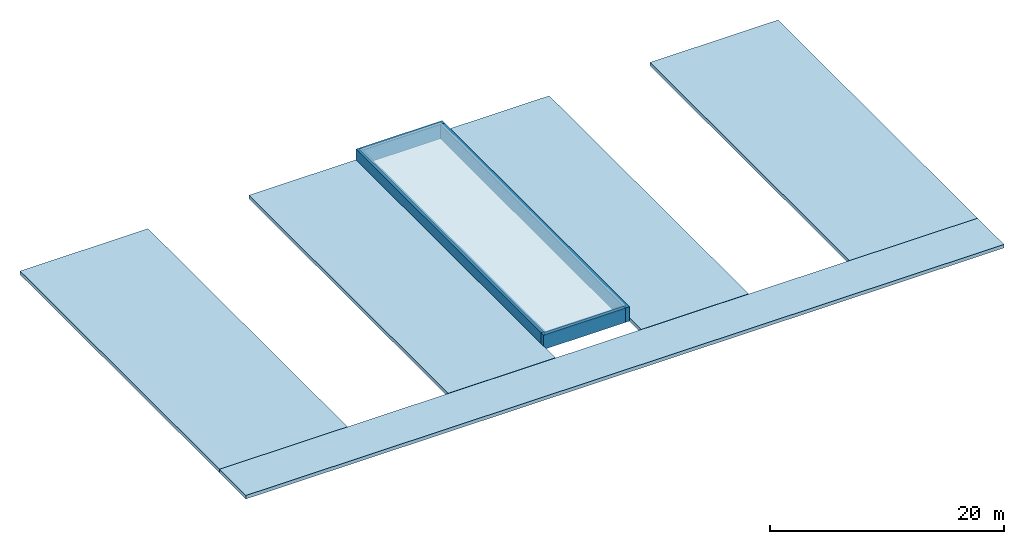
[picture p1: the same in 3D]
Properties of the parts of a building model (IFC2X3), part 3 of 3

# IfcCovering: Basic Ceiling:Generic (120)
Name (Basic Ceiling:Generic:...) | In | Level | Area (m2) | Perimeter (mm)
561077 | R+2 | Level: R+2 | 0.602 | 3660
561084 | R+2 | Level: R+2 | 0.602 | 3660
561091 | R+2 | Level: R+2 | 0.602 | 3660
561098 | R+2 | Level: R+2 | 0.602 | 3660
561105 | R+2 | Level: R+2 | 0.602 | 3660
561112 | R+2 | Level: R+2 | 0.602 | 3660
561119 | R+2 | Level: R+2 | 0.602 | 3660
561126 | R+2 | Level: R+2 | 0.602 | 3660
561133 | R+2 | Level: R+2 | 0.602 | 3660
561140 | R+2 | Level: R+2 | 0.602 | 3660
561147 | R+2 | Level: R+2 | 0.602 | 3660
561154 | R+2 | Level: R+2 | 0.602 | 3660
561161 | R+2 | Level: R+2 | 0.602 | 3660
561168 | R+2 | Level: R+2 | 0.604375 | 3663.39
561175 | R+2 | Level: R+2 | 0.602 | 3660
561182 | R+2 | Level: R+2 | 0.602 | 3660
561189 | R+2 | Level: R+2 | 0.602 | 3660
561196 | R+2 | Level: R+2 | 0.602 | 3660
561203 | R+2 | Level: R+2 | 0.602 | 3660
561210 | R+2 | Level: R+2 | 0.602 | 3660
561217 | R+2 | Level: R+2 | 0.602 | 3660
561224 | R+2 | Level: R+2 | 0.602 | 3660
561231 | R+2 | Level: R+2 | 0.602 | 3660
561238 | R+2 | Level: R+2 | 0.602 | 3660
561245 | R+2 | Level: R+2 | 0.602 | 3660
561252 | R+2 | Level: R+2 | 0.602 | 3660
561259 | R+2 | Level: R+2 | 0.602 | 3660
561266 | R+2 | Level: R+2 | 0.602 | 3660
561273 | R+2 | Level: R+2 | 0.604375 | 3663.39

# IfcCovering: Compound Ceiling:Plain (112)
Type - PredefinedType: CEILING
Type - Analytical Properties - Roughness: 3; Absorptance: 0.7; Heat Transfer Coefficient (U): 0.534229; Thermal Mass: 2.80439; Thermal Resistance (R): 1.87186
Type - Construction - Thickness: 57 mm
Type - Graphics - Coarse Scale Fill Color: 0
Type - Identity Data - Keynote: K40; Type Name: Plain
Type - Other - Category: Ceilings; Family Name: Compound Ceiling
Type - Pset_CoveringCommon - Reference: Plain; TotalThickness: 57 mm
Type - Pset_ElementShading - Roughness: 914.4 mm
Type - Pset_ProductRequirements - Category: Ceilings
Type - Pset_QuantityTakeOff - Reference: Plain
Material: Metal Stud Layer 45 mm, PVC, Flexible 12 mm
Constraints - Room Bounding: yes; Height Offset From Level: 2959 mm
Dimensions - Area: 2.55962 m2; Perimeter: 6456.61 mm; Volume: 0.145899 m3
Identity Data - Comments: ThisIsExisiting
Other - Family: Compound Ceiling: Plain; Family and Type: Compound Ceiling: Plain; Type: Compound Ceiling: Plain; Type Id: Compound Ceiling: Plain
Phasing - Phase Created: Existing
Name (Compound Ceiling:Plain:...) | In | Level
558983 | R+1 | Level: R+1
559039 | R+1 | Level: R+1
559058 | R+1 | Level: R+1
559067 | R+1 | Level: R+1
559076 | R+1 | Level: R+1
559085 | R+1 | Level: R+1
559094 | R+1 | Level: R+1
559103 | R+1 | Level: R+1
559112 | R+1 | Level: R+1
559121 | R+1 | Level: R+1
559130 | R+1 | Level: R+1
559139 | R+1 | Level: R+1
559148 | R+1 | Level: R+1
559157 | R+1 | Level: R+1
559180 | R+1 | Level: R+1
559188 | R+1 | Level: R+1
559196 | R+1 | Level: R+1
559204 | R+1 | Level: R+1
559212 | R+1 | Level: R+1
559220 | R+1 | Level: R+1
559228 | R+1 | Level: R+1
559236 | R+1 | Level: R+1
559244 | R+1 | Level: R+1
559252 | R+1 | Level: R+1
559260 | R+1 | Level: R+1
559268 | R+1 | Level: R+1
559276 | R+1 | Level: R+1
559284 | R+1 | Level: R+1
559400 | R+1 | Level: R+1
559407 | R+1 | Level: R+1
559414 | R+1 | Level: R+1
559421 | R+1 | Level: R+1
559428 | R+1 | Level: R+1
559435 | R+1 | Level: R+1
559442 | R+1 | Level: R+1
559449 | R+1 | Level: R+1
559456 | R+1 | Level: R+1
559463 | R+1 | Level: R+1
559470 | R+1 | Level: R+1
559477 | R+1 | Level: R+1
559484 | R+1 | Level: R+1
559491 | R+1 | Level: R+1
559498 | R+1 | Level: R+1
559505 | R+1 | Level: R+1
559512 | R+1 | Level: R+1
559519 | R+1 | Level: R+1
559526 | R+1 | Level: R+1
559533 | R+1 | Level: R+1
559540 | R+1 | Level: R+1
559547 | R+1 | Level: R+1
559554 | R+1 | Level: R+1
559561 | R+1 | Level: R+1
559568 | R+1 | Level: R+1
559575 | R+1 | Level: R+1
559582 | R+1 | Level: R+1
559589 | R+1 | Level: R+1
559599 | R+2 | Level: R+2
559606 | R+2 | Level: R+2
559613 | R+2 | Level: R+2
559620 | R+2 | Level: R+2
559627 | R+2 | Level: R+2
559634 | R+2 | Level: R+2
559641 | R+2 | Level: R+2
559648 | R+2 | Level: R+2
559655 | R+2 | Level: R+2
559662 | R+2 | Level: R+2
559669 | R+2 | Level: R+2
559676 | R+2 | Level: R+2
559683 | R+2 | Level: R+2
559690 | R+2 | Level: R+2
559697 | R+2 | Level: R+2
559704 | R+2 | Level: R+2
559711 | R+2 | Level: R+2
559718 | R+2 | Level: R+2
559725 | R+2 | Level: R+2
559732 | R+2 | Level: R+2
559739 | R+2 | Level: R+2
559746 | R+2 | Level: R+2
559753 | R+2 | Level: R+2
559760 | R+2 | Level: R+2
559767 | R+2 | Level: R+2
559774 | R+2 | Level: R+2
559781 | R+2 | Level: R+2
559788 | R+2 | Level: R+2
559795 | R+2 | Level: R+2
559802 | R+2 | Level: R+2
559809 | R+2 | Level: R+2
559816 | R+2 | Level: R+2
559823 | R+2 | Level: R+2
559830 | R+2 | Level: R+2
559837 | R+2 | Level: R+2
559844 | R+2 | Level: R+2
559851 | R+2 | Level: R+2
559858 | R+2 | Level: R+2
559865 | R+2 | Level: R+2
559872 | R+2 | Level: R+2
559879 | R+2 | Level: R+2
559886 | R+2 | Level: R+2
559893 | R+2 | Level: R+2
559900 | R+2 | Level: R+2
559907 | R+2 | Level: R+2
559914 | R+2 | Level: R+2
559921 | R+2 | Level: R+2
559928 | R+2 | Level: R+2
559935 | R+2 | Level: R+2
559942 | R+2 | Level: R+2
559949 | R+2 | Level: R+2
559956 | R+2 | Level: R+2
559963 | R+2 | Level: R+2
559970 | R+2 | Level: R+2
559977 | R+2 | Level: R+2
559984 | R+2 | Level: R+2

# IfcCurtainWall: Curtain Wall:Curtain_Wall-Empty 2 (2)
In: RDC
Type - Construction - Function: Exterior; Automatically Embed: yes; Join Condition: Not Defined
Type - Horizontal Grid - Adjust for Mullion Size: no; Spacing: 1500 mm
Type - Horizontal Mullions - Border 1 Type: Rectangular Mullion: 50x150mm; Border 2 Type: Rectangular Mullion: 50x150mm
Type - Identity Data - Keynote: H11; Type Name: Curtain_Wall-Empty 2
Type - Other - Category: Walls; Family Name: Curtain Wall
Type - Vertical Grid - Adjust for Mullion Size: yes; Layout: Fixed Distance; Spacing: 2260 mm
Type - Vertical Mullions - Border 1 Type: Rectangular Mullion: 50x150mm; Border 2 Type: Rectangular Mullion: 50x150mm; Interior Type: Rectangular Mullion: 50x150mm
Type - Pset_CurtainWallCommon - IsExternal: no; Reference: Curtain_Wall-Empty 2
Type - Pset_ProductRequirements - Category: Walls
Type - Pset_QuantityTakeOff - Reference: Curtain_Wall-Empty 2
Pset_CurtainWallCommon - IsExternal: yes
Constraints - Room Bounding: yes; Top Offset: 0 mm; Base is Attached: no; Base Offset: 0 mm; Cross-Section: Vertical; Related to Mass: no; Top is Attached: no; Base Constraint: Level: RDC; Top Constraint: Level: R+1; Unconnected Height: 3660 mm
Dimensions - Area: 36.4316 m2; Length: 9954 mm
Horizontal Grid - Angle: 0 deg; Offset: 0 mm; Justification: Beginning; Number: 4; sets with these values: 2
Identity Data - Comments: ThisIsExisting
Other - Family: Curtain Wall: Curtain_Wall-Empty 2; Family and Type: Curtain Wall: Curtain_Wall-Empty 2; Type: Curtain Wall: Curtain_Wall-Empty 2; Type Id: Curtain Wall: Curtain_Wall-Empty 2
Phasing - Phase Created: Existing
Structural - Enable Analytical Model: no; Structural: no; Structural Usage: Non-bearing
Name (Curtain Wall:Curtain_Wall-Empty 2:...)
578327
578457

# IfcMember: Rectangular Mullion:50x150mm (32)
In: RDC
Type - PredefinedType: MULLION; Material: Aluminium
Type - Constraints - Angle: 0 deg; Offset: 0 mm
Type - Construction - Corner Mullion: no; Position: Perpendicular to Face; Thickness: 150 mm
Type - Dimensions - Width on side 1: 25 mm; Width on side 2: 25 mm
Type - Identity Data - Keynote: H11; Type Name: 50x150mm
Type - Materials and Finishes - Material: Aluminium
Type - Other - Category: Curtain Wall Mullions; Family Name: Rectangular Mullion
Type - Pset_MemberCommon - IsExternal: no; Reference: 50x150mm
Type - Pset_ProductRequirements - Category: Curtain Wall Mullions
Type - Pset_QuantityTakeOff - Reference: 50x150mm
Constraints - Level: Level: RDC
Other - Family: Rectangular Mullion: 50x150mm; Family and Type: Rectangular Mullion: 50x150mm; Host Id: Curtain Wall: Curtain_Wall-Empty 2; Type: Rectangular Mullion: 50x150mm; Type Id: Rectangular Mullion: 50x150mm
Phasing - Phase Created: Existing
Pset_MemberCommon - IsExternal: yes
Name (Rectangular Mullion:50x150mm:...) | Area (m2) | Length (mm) = Span (mm) | Volume (m3)
578341 | 0.1703 | 814 | 0.006105
578342 | 0.4495 | 2210 | 0.016575
578343 | 0.4495 | 2210 | 0.016575
578344 | 0.4495 | 2210 | 0.016575
578345 | 0.4495 | 2210 | 0.016575
578346 | 0.4495 | 2210 | 0.016575
578347 | 0.4495 | 2210 | 0.016575
578348 | 0.4495 | 2210 | 0.016575
578349 | 0.4495 | 2210 | 0.016575
578350 | 0.1703 | 814 | 0.006105
578351 | 0.7395 | 3660 | 0.02745
578352 | 0.7395 | 3660 | 0.02745
578353 | 0.7395 | 3660 | 0.02745
578354 | 0.7395 | 3660 | 0.02745
578355 | 0.7395 | 3660 | 0.02745
578356 | 0.7395 | 3660 | 0.02745
578467 | 0.1703 | 814 | 0.006105
578468 | 0.4495 | 2210 | 0.016575
578469 | 0.4495 | 2210 | 0.016575
578470 | 0.4495 | 2210 | 0.016575
578471 | 0.4495 | 2210 | 0.016575
578472 | 0.4495 | 2210 | 0.016575
578473 | 0.4495 | 2210 | 0.016575
578474 | 0.4495 | 2210 | 0.016575
578475 | 0.4495 | 2210 | 0.016575
578476 | 0.1703 | 814 | 0.006105
578477 | 0.7395 | 3660 | 0.02745
578478 | 0.7395 | 3660 | 0.02745
578479 | 0.7395 | 3660 | 0.02745
578480 | 0.7395 | 3660 | 0.02745
578481 | 0.7395 | 3660 | 0.02745
578482 | 0.7395 | 3660 | 0.02745

# IfcOpeningElement: Opening, Basic Wall:Mur S/SOL 18:385873:1
In: R-1
Pset_ElementShading - Roughness: 914.4 mm
Pset_OpeningElementCommon - Reference: Mur S/SOL 18; sets with these values: 2
Pset_ProductRequirements - Category: Walls

# IfcPlate: System Panel:Glazed (10)
In: RDC
Type - PredefinedType: CURTAIN_PANEL; Material: Glass
Type - Analytical Properties - Define Thermal Properties by: Schematic Type; Analytic Construction: 1/8 in Pilkington single glazing; Heat Transfer Coefficient (U): 6.7069; Solar Heat Gain Coefficient: 0.86; Thermal Resistance (R): 0.1491; Visual Light Transmittance: 0.9
Type - Constraints - Offset: 37 mm
Type - Dimensions - Thickness: 25 mm
Type - Identity Data - Keynote: H11; Type Name: Glazed
Type - Materials and Finishes - Material: Glass
Type - Other - Category: Curtain Panels; Family Name: System Panel
Type - Pset_PlateCommon - IsExternal: no; Reference: Glazed; ThermalTransmittance: 6.7069 kg/K/s3
Type - Pset_ProductRequirements - Category: Curtain Panels
Type - Pset_QuantityTakeOff - Reference: Glazed
Constraints - Level: Level: RDC
Dimensions - Height: 3560 mm
Other - Family: System Panel: Glazed; Family and Type: System Panel: Glazed; Host Id: Curtain Wall: Curtain_Wall-Empty 2; Type: System Panel: Glazed; Type Id: System Panel: Glazed
Phasing - Phase Created: Existing
Pset_PlateCommon - IsExternal: yes
Name (System Panel:Glazed:...) | Area (m2) | Volume (m3) | Width (mm)
578328 | 7.8676 | 0.19669 | 2210
578332 | 7.8676 | 0.19669 | 2210
578334 | 7.8676 | 0.19669 | 2210
578336 | 7.8676 | 0.19669 | 2210
578338 | 2.89784 | 0.072446 | 814
578458 | 7.8676 | 0.19669 | 2210
578460 | 7.8676 | 0.19669 | 2210
578462 | 7.8676 | 0.19669 | 2210
578464 | 7.8676 | 0.19669 | 2210
578466 | 2.89784 | 0.072446 | 814

# IfcRoof: Basic Roof:Roof_Flat-4Felt-150Ins-50Scr-150Conc-12Plr (6)
In: TOP
Pset_ElementShading - Roughness: 914.4 mm
Pset_ProductRequirements - Category: Roofs
Pset_QuantityTakeOff - Reference: Roof_Flat-4Felt-150Ins-50Scr-150Conc-12Plr
Pset_RoofCommon - IsExternal: yes; Reference: Roof_Flat-4Felt-150Ins-50Scr-150Conc-12Plr
Constraints - Room Bounding: yes; Related to Mass: no; Base Level: Level: TOP; Cutoff Offset: 0 mm
Construction - Fascia Depth: 0 mm; Rafter Cut: Plumb Cut
Dimensions - Slope: 0; Thickness: 366.5 mm
Identity Data - Comments: ThisIsExisting
Other - Category: Roofs; Family: Basic Roof: Roof_Flat-4Felt-150Ins-50Scr-150Conc-12Plr; Family and Type: Basic Roof: Roof_Flat-4Felt-150Ins-50Scr-150Conc-12Plr; Type: Basic Roof: Roof_Flat-4Felt-150Ins-50Scr-150Conc-12Plr; Type Id: Basic Roof: Roof_Flat-4Felt-150Ins-50Scr-150Conc-12Plr
Phasing - Phase Created: Existing
Name (Basic Roof:Roof_Flat-4Felt-150Ins-50Scr-150Conc-12Plr:...) | ProjectedArea (m2) = TotalArea (m2) = Area (m2) | Base Offset From Level (mm) | Maximum Ridge Height (mm) | Volume (m3)
584397 | 431.145 | 0 | 11596.5 | 158.015
584445 | 431.145 | 0 | 11596.5 | 158.015
584456 | 361.168 | 0 | 11596.5 | 132.368
584513 | 361.168 | 0 | 11596.5 | 132.368
584836 | 255.769 | 1200 | 12796.5 | 93.7393
584947 | 338.268 | 0 | 11596.5 | 123.975

# IfcSlab: Basic Roof:Roof_Flat-4Felt-150Ins-50Scr-150Conc-12Plr (6)
In: TOP
Type - PredefinedType: ROOF
Type - Analytical Properties - Roughness: 3; Absorptance: 0.7; Heat Transfer Coefficient (U): 0.221758; Thermal Mass: 30.4287; Thermal Resistance (R): 4.50943
Type - Construction - Default Thickness: 366.5 mm
Type - Graphics - Coarse Scale Fill Color: 0
Type - Identity Data - Type Name: Roof_Flat-4Felt-150Ins-50Scr-150Conc-12Plr
Type - Other - Category: Roofs; Family Name: Basic Roof
Type - Pset_ElementShading - Roughness: 914.4 mm
Type - Pset_ProductRequirements - Category: Roofs
Type - Pset_QuantityTakeOff - Reference: Roof_Flat-4Felt-150Ins-50Scr-150Conc-12Plr
Type - Pset_ReinforcementBarPitchOfSlab - Reference: Roof_Flat-4Felt-150Ins-50Scr-150Conc-12Plr
Type - Pset_SlabCommon - IsExternal: yes; Reference: Roof_Flat-4Felt-150Ins-50Scr-150Conc-12Plr; ThermalTransmittance: 0.221758 kg/K/s3
Material: Roofing Felt; Roofing Felt 4 mm, Rigid insulation 150 mm, Concrete, Sand/Cement Screed 50 mm, Concrete, Cast In Situ 150 mm, Plaster 12.5 mm
Pset_QuantityTakeOff - sets with these values: 2
Pset_SlabCommon - PitchAngle: 0 deg
Name (Basic Roof:Roof_Flat-4Felt-150Ins-50Scr-150Conc-12Plr:...)
584397
584445
584456
584513
584836
584947

# IfcSlab: Floor:Floor-Upper_160mmConc-CorusComFlor51 (4)
Type - PredefinedType: FLOOR; Material: Concrete, Cast-in-Place - C15 211 mm
Type - Analytical Properties - Roughness: 3; Absorptance: 0.7; Heat Transfer Coefficient (U): 4.95735; Thermal Mass: 29.6214; Thermal Resistance (R): 0.201721
Type - Construction - Function: Interior; Default Thickness: 211 mm
Type - Graphics - Coarse Scale Fill Color: 0
Type - Identity Data - Type Name: Floor-Upper_160mmConc-CorusComFlor51
Type - Materials and Finishes - Structural Material: Concrete, Cast-in-Place - C15
Type - Other - Category: Floors; Family Name: Floor
Type - Pset_ElementShading - Roughness: 914.4 mm
Type - Pset_ProductRequirements - Category: Floors
Type - Pset_QuantityTakeOff - Reference: Floor-Upper_160mmConc-CorusComFlor51
Type - Pset_ReinforcementBarPitchOfSlab - Reference: Floor-Upper_160mmConc-CorusComFlor51
Type - Pset_SlabCommon - IsExternal: no; Reference: Floor-Upper_160mmConc-CorusComFlor51; ThermalTransmittance: 4.95735 kg/K/s3
Pset_QuantityTakeOff - sets with these values: 2
Pset_SlabCommon - LoadBearing: no; PitchAngle: 0 deg
Constraints - Room Bounding: yes; Related to Mass: no; Height Offset From Level: 0 mm
Dimensions - Thickness: 211 mm
Other - Family: Floor: Floor-Upper_160mmConc-CorusComFlor51; Family and Type: Floor: Floor-Upper_160mmConc-CorusComFlor51; Type: Floor: Floor-Upper_160mmConc-CorusComFlor51; Type Id: Floor: Floor-Upper_160mmConc-CorusComFlor51
Phasing - Phase Created: Existing
Structural - Enable Analytical Model: no; Structural: no
Name (Floor:Floor-Upper_160mmConc-CorusComFlor51:...) | In | Level | Elevation at Top (mm) | Area (m2) | Elevation at Bottom (mm) | Perimeter (mm) | Volume (m3)
579386 | RDC | Level: RDC | 0 | 61.7814 | -211 | 46712.8 | 13.0359
584188 | RDC | Level: RDC | 0 | 40.7037 | -211 | 28084 | 8.58848
584215 | RDC | Level: RDC | 0 | 22.496 | -211 | 24428 | 4.74666
586388 | R+1 | Level: R+1 | 3660 | 6.1257 | 3449 | 10816 | 1.29252 | Identity Data - Comments: ThisIsExisting

# IfcSlab: Floor:Plancher S/SOL Fille 0-1 (2)
Type - PredefinedType: FLOOR; Material: Concrete, Cast-in-Place - C15 300 mm
Type - Analytical Properties - Roughness: 3; Absorptance: 0.7; Heat Transfer Coefficient (U): 3.48667; Thermal Mass: 42.1157; Thermal Resistance (R): 0.286807
Type - Construction - Function: Interior; Default Thickness: 300 mm
Type - Graphics - Coarse Scale Fill Color: 0
Type - Identity Data - Type Name: Plancher S/SOL Fille 0-1
Type - Materials and Finishes - Structural Material: Concrete, Cast-in-Place - C15
Type - Other - Category: Floors; Family Name: Floor
Type - Pset_ElementShading - Roughness: 914.4 mm
Type - Pset_ProductRequirements - Category: Floors
Type - Pset_QuantityTakeOff - Reference: Plancher S/SOL Fille 0-1
Type - Pset_ReinforcementBarPitchOfSlab - Reference: Plancher S/SOL Fille 0-1
Type - Pset_SlabCommon - IsExternal: no; Reference: Plancher S/SOL Fille 0-1; ThermalTransmittance: 3.48667 kg/K/s3
Pset_QuantityTakeOff - sets with these values: 2
Pset_SlabCommon - LoadBearing: yes; PitchAngle: 0 deg
Constraints - Room Bounding: yes; Related to Mass: no
Dimensions - Core Thickness: 300 mm; Thickness: 300 mm
Other - Family: Floor: Plancher S/SOL Fille 0-1; Family and Type: Floor: Plancher S/SOL Fille 0-1; Type: Floor: Plancher S/SOL Fille 0-1; Type Id: Floor: Plancher S/SOL Fille 0-1
Structural - Enable Analytical Model: yes; Rebar Cover - Bottom Face: Rebar Cover Settings: Rebar Cover 1; Rebar Cover - Other Faces: Rebar Cover Settings: Rebar Cover 1; Rebar Cover - Top Face: Rebar Cover Settings: Rebar Cover 1; Structural: yes
Name (Floor:Plancher S/SOL Fille 0-1:...) | In | Level | Height Offset From Level (mm) | Area (m2) | Elevation at Bottom (mm) = Elevation at Bottom Core (mm) = Elevation at Bottom Survey (mm) | Elevation at Top (mm) = Elevation at Top Core (mm) = Elevation at Top Survey (mm) | Perimeter (mm) | Volume (m3) | ElementID | Phase Created
493007 | RDC | Level: RDC | -800 | 2.7778 | -1100 | -800 | 6670 | 0.83334 | 493007 | New Construction | Identity Data - Comments: ThisIsNew
495941 | R-1 | Level: R-1 | 0 | 41.9306 | -3800 | -3500 | 28580 | 12.5792 | 495941 | Existing

# IfcSlab: Floor:Plancher S/SOL Fille 0-1 140mm (2)
In: RDC
Type - PredefinedType: FLOOR; Material: Concrete, Cast-in-Place - C15 140 mm
Type - Analytical Properties - Roughness: 3; Absorptance: 0.7; Heat Transfer Coefficient (U): 7.47143; Thermal Mass: 19.654; Thermal Resistance (R): 0.133843
Type - Construction - Function: Interior; Default Thickness: 140 mm
Type - Graphics - Coarse Scale Fill Color: 0
Type - Identity Data - Type Name: Plancher S/SOL Fille 0-1 140mm
Type - Materials and Finishes - Structural Material: Concrete, Cast-in-Place - C15
Type - Other - Category: Floors; Family Name: Floor
Type - Pset_ElementShading - Roughness: 914.4 mm
Type - Pset_ProductRequirements - Category: Floors
Type - Pset_QuantityTakeOff - Reference: Plancher S/SOL Fille 0-1 140mm
Type - Pset_ReinforcementBarPitchOfSlab - Reference: Plancher S/SOL Fille 0-1 140mm
Type - Pset_SlabCommon - IsExternal: no; Reference: Plancher S/SOL Fille 0-1 140mm; ThermalTransmittance: 7.47143 kg/K/s3
Pset_QuantityTakeOff - sets with these values: 2
Pset_SlabCommon - LoadBearing: no; PitchAngle: 0 deg
Constraints - Room Bounding: yes; Related to Mass: no; Level: Level: RDC; Height Offset From Level: -1030 mm
Dimensions - Area: 3.0228 m2; Elevation at Bottom: -1170 mm; Elevation at Top: -1030 mm; Perimeter: 6964 mm; Thickness: 140 mm; Volume: 0.423192 m3
Other - Family: Floor: Plancher S/SOL Fille 0-1 140mm; Family and Type: Floor: Plancher S/SOL Fille 0-1 140mm; Type: Floor: Plancher S/SOL Fille 0-1 140mm; Type Id: Floor: Plancher S/SOL Fille 0-1 140mm
Structural - Enable Analytical Model: no; Structural: no
Name (Floor:Plancher S/SOL Fille 0-1 140mm:...) | ElementID | Phase Created
496856 | 496856 | New Construction
498159 | 498159 | Existing

# IfcSlab: Floor:PlancherChauffant130Blue (9)
In: R+2
Type - PredefinedType: FLOOR; Material: Polyurethane FoamBlue 30 mm, Concrete, Cast-in-Place - C15 100 mm
Type - Analytical Properties - Roughness: 3; Absorptance: 0.7; Heat Transfer Coefficient (U): 0.967958; Thermal Mass: 14.1879; Thermal Resistance (R): 1.0331
Type - Construction - Function: Interior; Default Thickness: 130 mm
Type - Graphics - Coarse Scale Fill Color: 0
Type - Identity Data - Type Name: PlancherChauffant130Blue
Type - Materials and Finishes - Structural Material: Concrete, Cast-in-Place - C15
Type - Other - Category: Floors; Family Name: Floor
Type - Pset_ElementShading - Roughness: 914.4 mm
Type - Pset_ProductRequirements - Category: Floors
Type - Pset_QuantityTakeOff - Reference: PlancherChauffant130Blue
Type - Pset_ReinforcementBarPitchOfSlab - Reference: PlancherChauffant130Blue
Type - Pset_SlabCommon - IsExternal: no; Reference: PlancherChauffant130Blue; ThermalTransmittance: 0.967958 kg/K/s3
Pset_QuantityTakeOff - sets with these values: 2
Pset_SlabCommon - LoadBearing: no; PitchAngle: 0 deg
Constraints - Room Bounding: yes; Related to Mass: no; Level: Level: R+2; Height Offset From Level: 0 mm
Dimensions - Elevation at Bottom: 7190 mm; Elevation at Top: 7320 mm; Thickness: 130 mm
Identity Data - Comments: ThisIsExisting
Other - Family: Floor: PlancherChauffant130Blue; Family and Type: Floor: PlancherChauffant130Blue; Type: Floor: PlancherChauffant130Blue; Type Id: Floor: PlancherChauffant130Blue
Phasing - Phase Created: Existing
Structural - Enable Analytical Model: no; Structural: no
Name (Floor:PlancherChauffant130Blue:...) | Area (m2) | Perimeter (mm) | Volume (m3) | ElementID
438846 | 469.108 | 101260 | 60.9841 | 438846
453631 | 433.508 | 100830 | 56.3561 | 453631
453670 | 23.4588 | 25280 | 3.04964 | 453670
453677 | 23.4588 | 25280 | 3.04964 | 453677
453744 | 6.94396 | 12053.5 | 0.902715 | 453744
453751 | 6.94396 | 12053.5 | 0.902715 | 453751
488201 | 469.108 | 101260 | 60.9841 | 488201
548189 | 19.6399 | 18084.5 | 2.55318
565415 | 433.508 | 100830 | 56.3561 | 453631

# IfcSlab: Floor:PlancherChauffant130Grey (7)
In: R-1
Type - PredefinedType: FLOOR; Material: Polyurethane Foam 30 mm, Concrete, Cast-in-Place - C15 100 mm
Type - Analytical Properties - Roughness: 3; Absorptance: 0.7; Heat Transfer Coefficient (U): 0.967958; Thermal Mass: 14.1879; Thermal Resistance (R): 1.0331
Type - Construction - Function: Interior; Default Thickness: 130 mm
Type - Graphics - Coarse Scale Fill Color: 0
Type - Identity Data - Type Name: PlancherChauffant130Grey
Type - Materials and Finishes - Structural Material: Concrete, Cast-in-Place - C15
Type - Other - Category: Floors; Family Name: Floor
Type - Pset_ElementShading - Roughness: 914.4 mm
Type - Pset_ProductRequirements - Category: Floors
Type - Pset_QuantityTakeOff - Reference: PlancherChauffant130Grey
Type - Pset_ReinforcementBarPitchOfSlab - Reference: PlancherChauffant130Grey
Type - Pset_SlabCommon - IsExternal: no; Reference: PlancherChauffant130Grey; ThermalTransmittance: 0.967958 kg/K/s3
Pset_QuantityTakeOff - sets with these values: 2
Pset_SlabCommon - LoadBearing: no; PitchAngle: 0 deg
Constraints - Level: Level: R-1; Room Bounding: yes; Related to Mass: no; Height Offset From Level: 0 mm
Dimensions - Elevation at Bottom: -3630 mm; Elevation at Top: -3500 mm; Thickness: 130 mm
Other - Family: Floor: PlancherChauffant130Grey; Family and Type: Floor: PlancherChauffant130Grey; Type: Floor: PlancherChauffant130Grey; Type Id: Floor: PlancherChauffant130Grey
Phasing - Phase Created: Existing
Structural - Enable Analytical Model: no; Structural: no
Name (Floor:PlancherChauffant130Grey:...) | Area (m2) | Perimeter (mm) | Volume (m3) | ElementID | Comments
453783 | 584.141 | 126185 | 75.9383 | 453783
453860 | 70.336 | 80530 | 9.14369 | 453860
453891 | 46.9176 | 29800 | 6.09929 | 453891 | ThisIsExisting
453968 | 70.3764 | 34320 | 9.14893 | 453968 | ThisIsExisting
454008 | 46.9176 | 29800 | 6.09929 | 454008 | ThisIsExisting
454038 | 93.8352 | 38840 | 12.1986 | 454038 | ThisIsExisting
454069 | 117.294 | 43360 | 15.2482 | 454069 | ThisIsExisting

# IfcSlab: Floor:PlancherChauffant130Jaune (10)
In: R+1
Type - PredefinedType: FLOOR; Material: Polyurethane FoamYellowish 30 mm, Concrete, Cast-in-Place - C15 100 mm
Type - Analytical Properties - Roughness: 3; Absorptance: 0.7; Heat Transfer Coefficient (U): 0.967958; Thermal Mass: 14.1879; Thermal Resistance (R): 1.0331
Type - Construction - Function: Interior; Default Thickness: 130 mm
Type - Graphics - Coarse Scale Fill Color: 0
Type - Identity Data - Type Name: PlancherChauffant130Jaune
Type - Materials and Finishes - Structural Material: Concrete, Cast-in-Place - C15
Type - Other - Category: Floors; Family Name: Floor
Type - Pset_ElementShading - Roughness: 914.4 mm
Type - Pset_ProductRequirements - Category: Floors
Type - Pset_QuantityTakeOff - Reference: PlancherChauffant130Jaune
Type - Pset_ReinforcementBarPitchOfSlab - Reference: PlancherChauffant130Jaune
Type - Pset_SlabCommon - IsExternal: no; Reference: PlancherChauffant130Jaune; ThermalTransmittance: 0.967958 kg/K/s3
Pset_QuantityTakeOff - sets with these values: 2
Pset_SlabCommon - LoadBearing: no; PitchAngle: 0 deg
Constraints - Room Bounding: yes; Related to Mass: no; Level: Level: R+1; Height Offset From Level: 0 mm
Dimensions - Elevation at Bottom: 3530 mm; Elevation at Top: 3660 mm; Thickness: 130 mm
Other - Family: Floor: PlancherChauffant130Jaune; Family and Type: Floor: PlancherChauffant130Jaune; Type: Floor: PlancherChauffant130Jaune; Type Id: Floor: PlancherChauffant130Jaune
Phasing - Phase Created: Existing
Structural - Enable Analytical Model: no; Structural: no
Name (Floor:PlancherChauffant130Jaune:...) | Area (m2) | Perimeter (mm) | Volume (m3) | ElementID
438105 | 466.292 | 100820 | 60.618 | 438105 | Identity Data - Comments: ThisIsExisting
453519 | 19.6249 | 18076 | 2.55124 | 453519
453547 | 23.6664 | 25320 | 3.07663 | 453547
453584 | 23.4588 | 25280 | 3.04964 | 453584
453688 | 6.85446 | 12013.5 | 0.891079 | 453688
453735 | 6.94396 | 12053.5 | 0.902715 | 453735
537608 | 450.922 | 100460 | 58.6198 | 448713 | Identity Data - Comments: ThisIsExisting
541597 | 468.916 | 101250 | 60.9591 | 438105 | Identity Data - Comments: ThisIsExisting
541605 | 466.292 | 100820 | 60.618 | 438105 | Identity Data - Comments: ThisIsExisting
565485 | 450.922 | 100460 | 58.6198 | 448713 | Identity Data - Comments: ThisIsExisting

# IfcSlab: Floor:PlancherChauffant130Rouge (10)
In: RDC
Type - PredefinedType: FLOOR; Material: Polyurethane FoamRouge 30 mm, Concrete, Cast-in-Place - C15 100 mm
Type - Analytical Properties - Roughness: 3; Absorptance: 0.7; Heat Transfer Coefficient (U): 0.967958; Thermal Mass: 14.1879; Thermal Resistance (R): 1.0331
Type - Construction - Function: Interior; Default Thickness: 130 mm
Type - Graphics - Coarse Scale Fill Color: 0
Type - Identity Data - Type Name: PlancherChauffant130Rouge
Type - Materials and Finishes - Structural Material: Concrete, Cast-in-Place - C15
Type - Other - Category: Floors; Family Name: Floor
Type - Pset_ElementShading - Roughness: 914.4 mm
Type - Pset_ProductRequirements - Category: Floors
Type - Pset_QuantityTakeOff - Reference: PlancherChauffant130Rouge
Type - Pset_ReinforcementBarPitchOfSlab - Reference: PlancherChauffant130Rouge
Type - Pset_SlabCommon - IsExternal: no; Reference: PlancherChauffant130Rouge; ThermalTransmittance: 0.967958 kg/K/s3
Pset_QuantityTakeOff - sets with these values: 2
Pset_SlabCommon - LoadBearing: no; PitchAngle: 0 deg
Constraints - Room Bounding: yes; Related to Mass: no; Level: Level: RDC
Dimensions - Thickness: 130 mm
Other - Family: Floor: PlancherChauffant130Rouge; Family and Type: Floor: PlancherChauffant130Rouge; Type: Floor: PlancherChauffant130Rouge; Type Id: Floor: PlancherChauffant130Rouge
Phasing - Phase Created: Existing
Structural - Enable Analytical Model: no; Structural: no
Name (Floor:PlancherChauffant130Rouge:...) | Height Offset From Level (mm) = Elevation at Top (mm) | Area (m2) | Elevation at Bottom (mm) | Perimeter (mm) | Volume (m3) | ElementID
449009 | -5 | 470.027 | -135 | 101308 | 61.1036 | 449009
449051 | 0 | 328.423 | -130 | 84040 | 42.695 | 449051
449081 | 0 | 793.302 | -130 | 112740 | 103.129 | 449081
449109 | 0 | 328.423 | -130 | 84040 | 42.695 | 449109
449996 | 0 | 230.789 | -130 | 89670 | 30.0026 | 449996
451025 | 0 | 70.3361 | -130 | 80530 | 9.14369 | 451025
451056 | 0 | 49.1626 | -130 | 30232.6 | 6.39114 | 451056
451158 | 0 | 22.1953 | -130 | 25036.6 | 2.88539 | 451158
451208 | 0 | 40.6989 | -130 | 28086.6 | 5.29086 | 451208
451438 | 0 | 40.6989 | -130 | 28086.6 | 5.29086 | 451438

# IfcWallStandardCase: Basic Wall:Mur Facade Fille 0 430mm (5)
Type - PredefinedType: STANDARD; Material: Concrete, Precast Smooth, Light Grey 430 mm
Type - Analytical Properties - Roughness: 3; Absorptance: 0.7; Heat Transfer Coefficient (U): 2.43256; Thermal Mass: 60.3659; Thermal Resistance (R): 0.41109
Type - Construction - Wrapping at Inserts: Both; Function: Exterior; Width: 430 mm
Type - Graphics - Coarse Scale Fill Pattern: <Solid fill>; Coarse Scale Fill Color: 12632256
Type - Identity Data - Keynote: F10; Type Name: Mur Facade Fille 0 430mm
Type - Materials and Finishes - Structural Material: Concrete, Precast Smooth, Light Grey
Type - Other - Category: Walls; Family Name: Basic Wall
Type - Pset_ElementShading - Roughness: 914.4 mm
Type - Pset_ProductRequirements - Category: Walls
Type - Pset_QuantityTakeOff - Reference: Mur Facade Fille 0 430mm
Type - Pset_ReinforcementBarPitchOfWall - Reference: Mur Facade Fille 0 430mm
Type - Pset_WallCommon - IsExternal: no; Reference: Mur Facade Fille 0 430mm; ThermalTransmittance: 2.43256 kg/K/s3
Constraints - Room Bounding: yes; Base Extension Distance: 0 mm; Base is Attached: no; Cross-Section: Vertical; Related to Mass: no; Top Extension Distance: 0 mm; Top is Attached: no; Location Line: Core Centerline
Identity Data - Comments: ThisIsExisting
Other - Family: Basic Wall: Mur Facade Fille 0 430mm; Family and Type: Basic Wall: Mur Facade Fille 0 430mm; Type: Basic Wall: Mur Facade Fille 0 430mm; Type Id: Basic Wall: Mur Facade Fille 0 430mm
Phasing - Phase Created: Existing
Structural - Enable Analytical Model: no; Structural: no; Structural Usage: Non-bearing
Pset_QuantityTakeOff - sets with these values: 2
Pset_WallCommon - ExtendToStructure: no; LoadBearing: no; IsExternal: yes
Name (Basic Wall:Mur Facade Fille 0 430mm:...) | In | Top Offset (mm) | Base Constraint | Base Offset (mm) | Top Constraint | Unconnected Height (mm) | Area (m2) | Length (mm) | Volume (m3) | ElementID
537724 | R+1 | 0 | Level: R+1 | -930.421 | Level: R+2 | 4590.42 | 22.7702 | 4960.37 | 9.79118
537813 | R+2 | 140 | Level: R+2 | 0 | Level: TOP | 4050 | 20.0895 | 4960.37 | 8.63849
545126 | RDC | 0 | Level: RDC | 0 | Level: R+1 | 3660 | 6.74659 | 1843.33 | 2.90104 | 504722
545127 | R+2 | 140 | Level: R+2 | 0 | Level: TOITURE | 3660 | 6.74659 | 1843.33 | 2.90104 | 504867
545128 | R+1 | 0 | Level: R+1 | 0 | Level: R+2 | 3660 | 6.74659 | 1843.33 | 2.90104 | 504904

# IfcWallStandardCase: Basic Wall:Mur S/SOL 18 (18)
In: R-1
Type - PredefinedType: STANDARD; Material: Concrete - Cast-in-Place Concrete 180 mm
Type - Analytical Properties - Roughness: 3; Absorptance: 0.7
Type - Construction - Wrapping at Inserts: Both; Function: Exterior; Width: 180 mm
Type - Graphics - Coarse Scale Fill Pattern: <Solid fill>; Coarse Scale Fill Color: 12632256
Type - Identity Data - Keynote: F10; Type Name: Mur S/SOL 18
Type - Materials and Finishes - Structural Material: Concrete - Cast-in-Place Concrete
Type - Other - Category: Walls; Family Name: Basic Wall
Type - Pset_ElementShading - Roughness: 914.4 mm
Type - Pset_ProductRequirements - Category: Walls
Type - Pset_QuantityTakeOff - Reference: Mur S/SOL 18
Type - Pset_ReinforcementBarPitchOfWall - Reference: Mur S/SOL 18
Type - Pset_WallCommon - IsExternal: no; Reference: Mur S/SOL 18
Constraints - Room Bounding: yes; Base Constraint: Level: R-1; Base Extension Distance: 0 mm; Base is Attached: no; Base Offset: 0 mm; Cross-Section: Vertical; Related to Mass: no; Top Constraint: Level: RDC; Top Extension Distance: 0 mm
Other - Family: Basic Wall: Mur S/SOL 18; Family and Type: Basic Wall: Mur S/SOL 18; Type: Basic Wall: Mur S/SOL 18; Type Id: Basic Wall: Mur S/SOL 18
Phasing - Phase Created: Existing
Pset_QuantityTakeOff - sets with these values: 2
Pset_WallCommon - IsExternal: yes
Name (Basic Wall:Mur S/SOL 18:...) | Top is Attached = ExtendToStructure | Top Offset (mm) | Location Line | Unconnected Height (mm) | Area (m2) | Length (mm) | Volume (m3) | ElementID | Enable Analytical Model = Structural = LoadBearing | Structural Usage
385873 | yes | 0 | Core Face: Exterior | 3500 | 69.2872 | 20760 | 12.4717 | 385873 | no | Non-bearing
385982 | yes | 0 | Core Face: Exterior | 3500 | 69.2434 | 20547 | 12.4638 | 385982 | no | Non-bearing
386024 | no | 0 | Core Face: Exterior | 3500 | 8.4175 | 2405 | 1.51515 | 386024 | no | Non-bearing
386125 | no | 0 | Core Face: Exterior | 3500 | 8.32125 | 2277.5 | 1.49782 | 386125 | no | Non-bearing
386176 | no | 0 | Core Face: Exterior | 3500 | 4.9 | 1400 | 0.882 | 386176 | no | Non-bearing
386210 | no | 0 | Core Face: Exterior | 3500 | 4.9 | 1400 | 0.882 | 386210 | no | Non-bearing
389455 | yes | 0 | Core Face: Exterior | 3500 | 75.4105 | 22377 | 13.5739 | 389455 | no | Non-bearing
389456 | yes | 0 | Core Face: Exterior | 3500 | 69.2434 | 20547 | 12.4638 | 389456 | no | Non-bearing
389457 | no | 0 | Core Face: Exterior | 3500 | 8.4175 | 2405 | 1.51515 | 389457 | no | Non-bearing
389458 | no | 0 | Core Face: Exterior | 3500 | 8.32125 | 2277.5 | 1.49782 | 389458 | no | Non-bearing
389459 | no | 0 | Core Face: Exterior | 3500 | 4.9 | 1400 | 0.882 | 389459 | no | Non-bearing
389460 | no | 0 | Core Face: Exterior | 3500 | 4.9 | 1400 | 0.882 | 389460 | no | Non-bearing
493651 | no | 0 | Finish Face: Exterior | 3500 | 71.19 | 20340 | 12.8142 | 493651 | yes | Bearing | Identity Data - Comments: ThisIsExisting; Structural - Rebar Cover - Other Faces: Rebar Cover Settings: Rebar Cover 1; Rebar Cover - Exterior Face: Rebar Cover Settings: Rebar Cover 1; Rebar Cover - Interior Face: Rebar Cover Settings: Rebar Cover 1
582127 | no | -600 | Finish Face: Exterior | 2900 | 30.044 | 10360 | 5.40792 |  | yes | Bearing | Identity Data - Comments: ThisIsExisting; Structural - Rebar Cover - Other Faces: Rebar Cover Settings: Rebar Cover 1; Rebar Cover - Exterior Face: Rebar Cover Settings: Rebar Cover 1; Rebar Cover - Interior Face: Rebar Cover Settings: Rebar Cover 1
582358 | no | 0 | Finish Face: Exterior | 3500 | 31.22 | 8920 | 5.6196 |  | yes | Bearing | Identity Data - Comments: ThisIsExisting; Structural - Rebar Cover - Other Faces: Rebar Cover Settings: Rebar Cover 1; Rebar Cover - Exterior Face: Rebar Cover Settings: Rebar Cover 1; Rebar Cover - Interior Face: Rebar Cover Settings: Rebar Cover 1
582487 | no | -400 | Finish Face: Exterior | 3100 | 30.814 | 9940 | 5.54652 |  | yes | Bearing | Identity Data - Comments: ThisIsExisting; Structural - Rebar Cover - Other Faces: Rebar Cover Settings: Rebar Cover 1; Rebar Cover - Exterior Face: Rebar Cover Settings: Rebar Cover 1; Rebar Cover - Interior Face: Rebar Cover Settings: Rebar Cover 1
582658 | no | 0 | Finish Face: Exterior | 3500 | 34.79 | 10155 | 6.2622 |  | yes | Bearing | Identity Data - Comments: ThisIsExisting; Structural - Rebar Cover - Other Faces: Rebar Cover Settings: Rebar Cover 1; Rebar Cover - Exterior Face: Rebar Cover Settings: Rebar Cover 1; Rebar Cover - Interior Face: Rebar Cover Settings: Rebar Cover 1
582890 | yes | 0 | Finish Face: Exterior | 3500 | 40.1916 | 12220 | 7.23448 |  | yes | Bearing | Identity Data - Comments: ThisIsExisting; Structural - Rebar Cover - Other Faces: Rebar Cover Settings: Rebar Cover 1; Rebar Cover - Exterior Face: Rebar Cover Settings: Rebar Cover 1; Rebar Cover - Interior Face: Rebar Cover Settings: Rebar Cover 1

# IfcWallStandardCase: Basic Wall:Mur S/SOL 20 (3)
Type - PredefinedType: STANDARD; Material: Concrete - Cast-in-Place Concrete 200 mm
Type - Analytical Properties - Roughness: 3; Absorptance: 0.7
Type - Construction - Wrapping at Inserts: Both; Function: Exterior; Width: 200 mm
Type - Graphics - Coarse Scale Fill Pattern: <Solid fill>; Coarse Scale Fill Color: 12632256
Type - Identity Data - Keynote: F10; Type Name: Mur S/SOL 20
Type - Materials and Finishes - Structural Material: Concrete - Cast-in-Place Concrete
Type - Other - Category: Walls; Family Name: Basic Wall
Type - Pset_ElementShading - Roughness: 914.4 mm
Type - Pset_ProductRequirements - Category: Walls
Type - Pset_QuantityTakeOff - Reference: Mur S/SOL 20
Type - Pset_ReinforcementBarPitchOfWall - Reference: Mur S/SOL 20
Type - Pset_WallCommon - IsExternal: no; Reference: Mur S/SOL 20
Constraints - Room Bounding: yes; Top Offset: 0 mm; Base Extension Distance: 0 mm; Base is Attached: no; Base Offset: 0 mm; Cross-Section: Vertical; Related to Mass: no; Top Extension Distance: 0 mm; Top is Attached: no; Location Line: Finish Face: Exterior
Other - Family: Basic Wall: Mur S/SOL 20; Family and Type: Basic Wall: Mur S/SOL 20; Type: Basic Wall: Mur S/SOL 20; Type Id: Basic Wall: Mur S/SOL 20
Phasing - Phase Created: Existing
Pset_QuantityTakeOff - sets with these values: 2
Pset_WallCommon - ExtendToStructure: no; IsExternal: yes
Name (Basic Wall:Mur S/SOL 20:...) | In | Base Constraint | Unconnected Height (mm) | Area (m2) | Length (mm) | Volume (m3) | ElementID | Enable Analytical Model = Structural = LoadBearing | Rebar Cover - Other Faces = Rebar Cover - Exterior Face = Rebar Cover - Interior Face | Structural Usage
492767 | R-1 | Level: R-1 | 2000 | 3.3 | 1840 | 0.66 | 492767 | yes | Rebar Cover Settings: Rebar Cover 1 | Bearing
492980 | R-1 | Level: R-1 | 2000 | 3.3 | 1840 | 0.66 | 492980 | yes | Rebar Cover Settings: Rebar Cover 1 | Bearing
548321 | R+2 | Level: R+2 | 3520 | 4.94208 | 1404 | 0.988416 |  | no |  | Non-bearing | Constraints - Top Constraint: Level: TOITURE; Identity Data - Comments: ThisIsExisting

# IfcWallStandardCase: Basic Wall:Mur S/SOL 21 (2)
In: R-1
Type - PredefinedType: STANDARD; Material: Concrete - Cast-in-Place Concrete 210 mm
Type - Analytical Properties - Roughness: 3; Absorptance: 0.7
Type - Construction - Wrapping at Inserts: Both; Function: Exterior; Width: 210 mm
Type - Graphics - Coarse Scale Fill Pattern: <Solid fill>; Coarse Scale Fill Color: 12632256
Type - Identity Data - Keynote: F10; Type Name: Mur S/SOL 21
Type - Materials and Finishes - Structural Material: Concrete - Cast-in-Place Concrete
Type - Other - Category: Walls; Family Name: Basic Wall
Type - Pset_ElementShading - Roughness: 914.4 mm
Type - Pset_ProductRequirements - Category: Walls
Type - Pset_QuantityTakeOff - Reference: Mur S/SOL 21
Type - Pset_ReinforcementBarPitchOfWall - Reference: Mur S/SOL 21
Type - Pset_WallCommon - IsExternal: no; Reference: Mur S/SOL 21
Constraints - Room Bounding: yes; Base Constraint: Level: R-1; Base Extension Distance: 0 mm; Base is Attached: no; Base Offset: 0 mm; Cross-Section: Vertical; Related to Mass: no; Top Constraint: Level: RDC; Top Extension Distance: 0 mm; Top is Attached: no
Other - Family: Basic Wall: Mur S/SOL 21; Family and Type: Basic Wall: Mur S/SOL 21; Type: Basic Wall: Mur S/SOL 21; Type Id: Basic Wall: Mur S/SOL 21
Phasing - Phase Created: Existing
Structural - Enable Analytical Model: yes; Rebar Cover - Other Faces: Rebar Cover Settings: Rebar Cover 1; Rebar Cover - Exterior Face: Rebar Cover Settings: Rebar Cover 1; Rebar Cover - Interior Face: Rebar Cover Settings: Rebar Cover 1; Structural: yes; Structural Usage: Bearing
Pset_QuantityTakeOff - sets with these values: 2
Pset_WallCommon - LoadBearing: yes; ExtendToStructure: no; IsExternal: yes
Name (Basic Wall:Mur S/SOL 21:...) | Location Line | Top Offset (mm) | Unconnected Height (mm) | Area (m2) | Length (mm) | Volume (m3) | ElementID
494140 | Finish Face: Exterior | -800 | 2700 | 3.7854 | 1402 | 0.794934 | 494140
495766 | Core Centerline | 0 | 3500 | 36.33 | 10380 | 7.6293 | 495766

# IfcWallStandardCase: Basic Wall:Mur S/SOL 43 (2)
In: RDC
Type - PredefinedType: STANDARD; Material: Concrete, Precast Smooth, Light Grey 430 mm
Type - Analytical Properties - Roughness: 3; Absorptance: 0.7; Heat Transfer Coefficient (U): 2.43256; Thermal Mass: 60.3659; Thermal Resistance (R): 0.41109
Type - Construction - Wrapping at Inserts: Both; Function: Exterior; Width: 430 mm
Type - Graphics - Coarse Scale Fill Pattern: <Solid fill>; Coarse Scale Fill Color: 12632256
Type - Identity Data - Keynote: F10; Type Name: Mur S/SOL 43
Type - Materials and Finishes - Structural Material: Concrete, Precast Smooth, Light Grey
Type - Other - Category: Walls; Family Name: Basic Wall
Type - Pset_ElementShading - Roughness: 914.4 mm
Type - Pset_ProductRequirements - Category: Walls
Type - Pset_QuantityTakeOff - Reference: Mur S/SOL 43
Type - Pset_ReinforcementBarPitchOfWall - Reference: Mur S/SOL 43
Type - Pset_WallCommon - IsExternal: no; Reference: Mur S/SOL 43; ThermalTransmittance: 2.43256 kg/K/s3
Constraints - Room Bounding: yes; Top Offset: 0 mm; Base Extension Distance: 0 mm; Base is Attached: no; Base Offset: 0 mm; Cross-Section: Vertical; Location Line: Core Face: Exterior; Related to Mass: no; Top Extension Distance: 0 mm; Top is Attached: no; Base Constraint: Level: RDC; Unconnected Height: 210 mm
Dimensions - Area: 5.77659 m2; Length: 27507.6 mm; Volume: 2.48394 m3
Identity Data - Comments: ThisIsExisting
Other - ElementID: 384326; Family: Basic Wall: Mur S/SOL 43; Family and Type: Basic Wall: Mur S/SOL 43; Type: Basic Wall: Mur S/SOL 43; Type Id: Basic Wall: Mur S/SOL 43
Phasing - Phase Created: Existing
Structural - Enable Analytical Model: yes; Rebar Cover - Other Faces: Rebar Cover Settings: Rebar Cover 1; Rebar Cover - Exterior Face: Rebar Cover Settings: Rebar Cover 1; Rebar Cover - Interior Face: Rebar Cover Settings: Rebar Cover 1; Structural: yes; Structural Usage: Bearing
Pset_QuantityTakeOff - sets with these values: 2
Pset_WallCommon - LoadBearing: yes; ExtendToStructure: no; IsExternal: yes
Name (Basic Wall:Mur S/SOL 43:...)
579071
579335

# IfcWallStandardCase: Basic Wall:Mur430PentureBlanche (4)
In: TOP
Type - PredefinedType: STANDARD; Material: Paint - White Lining 15 mm, Concrete - Precast Concrete - 35 MPa 400 mm, Paint - White Lining 15 mm
Type - Analytical Properties - Roughness: 3; Absorptance: 0.7
Type - Construction - Wrapping at Inserts: Both; Function: Exterior; Width: 430 mm
Type - Graphics - Coarse Scale Fill Pattern: <Solid fill>; Coarse Scale Fill Color: 12632256
Type - Identity Data - Keynote: F10; Type Name: Mur430PentureBlanche
Type - Materials and Finishes - Structural Material: Concrete - Precast Concrete - 35 MPa
Type - Other - Category: Walls; Family Name: Basic Wall
Type - Pset_ElementShading - Roughness: 914.4 mm
Type - Pset_ProductRequirements - Category: Walls
Type - Pset_QuantityTakeOff - Reference: Mur430PentureBlanche
Type - Pset_ReinforcementBarPitchOfWall - Reference: Mur430PentureBlanche
Type - Pset_WallCommon - IsExternal: no; Reference: Mur430PentureBlanche
Constraints - Room Bounding: yes; Top Offset: 0 mm; Base Extension Distance: 0 mm; Base is Attached: no; Base Offset: 0 mm; Cross-Section: Vertical; Related to Mass: no; Top Extension Distance: 0 mm; Top is Attached: no; Base Constraint: Level: TOP; Location Line: Wall Centerline; Unconnected Height: 1500 mm
Identity Data - Comments: ThisIsExisting
Other - Family: Basic Wall: Mur430PentureBlanche; Family and Type: Basic Wall: Mur430PentureBlanche; Type: Basic Wall: Mur430PentureBlanche; Type Id: Basic Wall: Mur430PentureBlanche
Phasing - Phase Created: Existing
Structural - Enable Analytical Model: no; Structural: no; Structural Usage: Non-bearing
Pset_QuantityTakeOff - sets with these values: 2
Pset_WallCommon - ExtendToStructure: no; LoadBearing: no; IsExternal: yes
Name (Basic Wall:Mur430PentureBlanche:...) | Area (m2) | Length (mm) | Volume (m3)
584672 | 12.105 | 8070 | 5.20515
584673 | 47.43 | 31620 | 20.3949
584674 | 12.105 | 8070 | 5.20515
584675 | 47.43 | 31620 | 20.3949

# IfcWallStandardCase: Basic Wall:Wall-Fnd_200 (29)
In: R-1
Type - PredefinedType: STANDARD; Material: Concrete - Cast-in-Place Concrete 200 mm
Type - Analytical Properties - Roughness: 3; Absorptance: 0.7
Type - Construction - Wrapping at Inserts: Both; Function: Exterior; Width: 200 mm
Type - Graphics - Coarse Scale Fill Pattern: <Solid fill>; Coarse Scale Fill Color: 12632256
Type - Identity Data - Keynote: F10; Type Name: Wall-Fnd_200
Type - Materials and Finishes - Structural Material: Concrete - Cast-in-Place Concrete
Type - Other - Category: Walls; Family Name: Basic Wall
Type - Pset_ElementShading - Roughness: 914.4 mm
Type - Pset_ProductRequirements - Category: Walls
Type - Pset_QuantityTakeOff - Reference: Wall-Fnd_200
Type - Pset_ReinforcementBarPitchOfWall - Reference: Wall-Fnd_200
Type - Pset_WallCommon - IsExternal: no; Reference: Wall-Fnd_200
Constraints - Room Bounding: yes; Top Offset: 0 mm; Base Constraint: Level: R-1; Base Extension Distance: 0 mm; Base is Attached: no; Base Offset: 0 mm; Cross-Section: Vertical; Related to Mass: no; Top Constraint: Level: RDC; Top Extension Distance: 0 mm; Unconnected Height: 3500 mm
Other - Family: Basic Wall: Wall-Fnd_200; Family and Type: Basic Wall: Wall-Fnd_200; Type: Basic Wall: Wall-Fnd_200; Type Id: Basic Wall: Wall-Fnd_200
Phasing - Phase Created: Existing
Structural - Enable Analytical Model: no; Structural: no; Structural Usage: Non-bearing
Pset_QuantityTakeOff - sets with these values: 2
Pset_WallCommon - LoadBearing: no; IsExternal: yes
Name (Basic Wall:Wall-Fnd_200:...) | Location Line | Top is Attached = ExtendToStructure | Area (m2) | Length (mm) | Volume (m3) | ElementID
384621 | Core Face: Exterior | no | 111.142 | 31755 | 22.2285 | 384621
385173 | Core Face: Exterior | no | 7.4731 | 1930 | 1.49462 | 385173
385244 | Core Centerline | yes | 22.9666 | 7005 | 4.59331 | 385244
385338 | Core Face: Exterior | yes | 49.5896 | 14715 | 9.91791 | 385338
385400 | Core Face: Exterior | yes | 14.2085 | 4635 | 2.8417 | 385400
385546 | Core Face: Exterior | no | 85.75 | 24500 | 17.15 | 385546
385637 | Core Face: Exterior | yes | 13.8338 | 4305 | 2.76677 | 385637
385693 | Core Face: Exterior | yes | 13.8338 | 4305 | 2.76677 | 385693
389444 | Core Face: Exterior | yes | 192.538 | 58540 | 38.5076 | 389444
389448 | Core Face: Exterior | no | 6.405 | 1830 | 1.281 | 389448
389449 | Core Centerline | yes | 7.6162 | 2360 | 1.52324 | 389449
389450 | Core Face: Exterior | yes | 49.5896 | 14715 | 9.91791 | 389450
389451 | Core Face: Exterior | yes | 14.2085 | 4635 | 2.8417 | 389451
389452 | Core Face: Exterior | no | 15.05 | 4300 | 3.01 | 389452
389453 | Core Face: Exterior | no | 14.3675 | 4305 | 2.8735 | 389453
389454 | Core Face: Exterior | no | 14.3675 | 4305 | 2.8735 | 389454
390332 | Finish Face: Exterior | yes | 14.5078 | 4305 | 2.90157 | 390332
390372 | Finish Face: Exterior | yes | 22.3768 | 6540 | 4.47536 | 390372
390401 | Finish Face: Exterior | yes | 2.92915 | 869.183 | 0.585829 | 390401
390427 | Finish Face: Exterior | yes | 4.72474 | 1602 | 0.944948 | 390427
390460 | Finish Face: Exterior | yes | 5.44929 | 1617 | 1.08986 | 390460
390499 | Finish Face: Exterior | yes | 13.7833 | 4090 | 2.75666 | 390499
390787 | Finish Face: Exterior | no | 38.7975 | 11085 | 7.7595 | 390787
390810 | Finish Face: Exterior | no | 4.914 | 1404 | 0.9828 | 390810
390861 | Finish Face: Exterior | no | 14.315 | 4090 | 2.863 | 390861
390919 | Finish Face: Exterior | yes | 18.8046 | 5780 | 3.76092 | 390919
390965 | Finish Face: Exterior | yes | 15.4683 | 4770 | 3.09366 | 390965
391010 | Finish Face: Exterior | yes | 10.0763 | 3180 | 2.01526 | 391010
392395 | Finish Face: Exterior | no | 8.55727 | 2644.93 | 1.71145 | 392395

# IfcWallStandardCase: Basic Wall:Wall-Fnd_200interior (8)
In: R-1
Type - PredefinedType: STANDARD; Material: Concrete - Cast-in-Place Concrete 200 mm
Type - Analytical Properties - Absorptance: 0.7; Roughness: 3
Type - Construction - Function: Interior; Width: 200 mm; Wrapping at Inserts: Both
Type - Graphics - Coarse Scale Fill Color: 12632256; Coarse Scale Fill Pattern: <Solid fill>
Type - Identity Data - Keynote: F10; Type Name: Wall-Fnd_200interior
Type - Materials and Finishes - Structural Material: Concrete - Cast-in-Place Concrete
Type - Other - Category: Walls; Family Name: Basic Wall
Type - Pset_ElementShading - Roughness: 914.4 mm
Type - Pset_ProductRequirements - Category: Walls
Type - Pset_QuantityTakeOff - Reference: Wall-Fnd_200interior
Type - Pset_ReinforcementBarPitchOfWall - Reference: Wall-Fnd_200interior
Type - Pset_WallCommon - IsExternal: no; Reference: Wall-Fnd_200interior
Constraints - Room Bounding: yes; Base Constraint: Level: R-1; Base Extension Distance: 0 mm; Base is Attached: no; Base Offset: 0 mm; Cross-Section: Vertical; Location Line: Core Face: Exterior; Related to Mass: no; Top Constraint: Level: RDC; Top Extension Distance: 0 mm
Other - Family: Basic Wall: Wall-Fnd_200interior; Family and Type: Basic Wall: Wall-Fnd_200interior; Type: Basic Wall: Wall-Fnd_200interior; Type Id: Basic Wall: Wall-Fnd_200interior
Phasing - Phase Created: Existing
Structural - Enable Analytical Model: no; Structural: no; Structural Usage: Non-bearing
Pset_QuantityTakeOff - sets with these values: 2
Pset_WallCommon - LoadBearing: no
Name (Basic Wall:Wall-Fnd_200interior:...) | Top is Attached = ExtendToStructure | Top Offset (mm) | Unconnected Height (mm) | Area (m2) | Length (mm) | Volume (m3) | ElementID
383282 | no | 200 | 3700 | 30.8395 | 8550 | 6.1679 | 383282 | Identity Data - Comments: ThisIsExisting
383382 | no | 0 | 3500 | 35.63 | 10180 | 7.126 | 383382
383433 | no | 0 | 3500 | 15.12 | 4635 | 3.024 | 383433
383479 | yes | 0 | 3500 | 14.5584 | 4635 | 2.91168 | 383479
386321 | no | 0 | 3500 | 34.825 | 10380 | 6.965 | 386321
389430 | yes | 0 | 3500 | 45.4704 | 14040 | 9.09409 | 389430
389431 | yes | 0 | 3500 | 34.3066 | 10180 | 6.86132 | 389431
389433 | no | 0 | 3500 | 15.12 | 4635 | 3.024 | 389433

# IfcWallStandardCase: Basic Wall:Wall-Int_200 (15)
In: R-1
Type - PredefinedType: STANDARD; Material: Plaster 12.5 mm, Concrete Masonry Units 175 mm, Plaster 12.5 mm
Type - Analytical Properties - Roughness: 3; Absorptance: 0.7; Heat Transfer Coefficient (U): 5.44559; Thermal Mass: 27.0794; Thermal Resistance (R): 0.183635
Type - Construction - Function: Interior; Wrapping at Inserts: Both; Width: 200 mm
Type - Graphics - Coarse Scale Fill Pattern: <Solid fill>; Coarse Scale Fill Color: 12632256
Type - Identity Data - Type Name: Wall-Int_200
Type - Materials and Finishes - Structural Material: Concrete Masonry Units
Type - Other - Category: Walls; Family Name: Basic Wall
Type - Pset_ElementShading - Roughness: 914.4 mm
Type - Pset_ProductRequirements - Category: Walls
Type - Pset_QuantityTakeOff - Reference: Wall-Int_200
Type - Pset_ReinforcementBarPitchOfWall - Reference: Wall-Int_200
Type - Pset_WallCommon - IsExternal: no; Reference: Wall-Int_200; ThermalTransmittance: 5.44559 kg/K/s3
Constraints - Room Bounding: yes; Top Offset: 0 mm; Base Constraint: Level: R-1; Base Extension Distance: 0 mm; Base is Attached: no; Base Offset: 0 mm; Cross-Section: Vertical; Related to Mass: no; Top Constraint: Level: RDC; Top Extension Distance: 0 mm; Unconnected Height: 3500 mm
Other - Family: Basic Wall: Wall-Int_200; Family and Type: Basic Wall: Wall-Int_200; Type: Basic Wall: Wall-Int_200; Type Id: Basic Wall: Wall-Int_200
Phasing - Phase Created: Existing
Structural - Enable Analytical Model: no; Structural: no; Structural Usage: Non-bearing
Pset_QuantityTakeOff - sets with these values: 2
Pset_WallCommon - LoadBearing: no
Name (Basic Wall:Wall-Int_200:...) | Top is Attached = ExtendToStructure | Location Line | Area (m2) | Length (mm) | Volume (m3) | ElementID
387178 | yes | Core Centerline | 15.4683 | 4770 | 3.09366 | 387178
387339 | no | Finish Face: Exterior | 15.9425 | 4645 | 3.1885 | 387339
387530 | yes | Core Centerline | 15.4683 | 4770 | 3.09366 | 387530
388163 | no | Core Face: Exterior | 15.82 | 4520 | 3.164 | 388163
388276 | no | Core Face: Exterior | 16.065 | 4770 | 3.213 | 388276
388346 | yes | Core Face: Exterior | 13.1177 | 4092.5 | 2.62354 | 388346
388430 | no | Core Face: Exterior | 34.93 | 10180 | 6.986 | 388430
388461 | no | Core Face: Exterior | 6.405 | 1930 | 1.281 | 388461
388504 | no | Core Face: Exterior | 34.8594 | 10380 | 6.97188 | 388504
389467 | yes | Core Centerline | 15.4683 | 4770 | 3.09366 | 389467
389468 | no | Finish Face: Exterior | 15.9425 | 4645 | 3.1885 | 389468
389470 | yes | Core Centerline | 15.4683 | 4770 | 3.09366 | 389470
389480 | no | Core Face: Exterior | 15.82 | 4520 | 3.164 | 389480
389481 | no | Core Face: Exterior | 16.065 | 4770 | 3.213 | 389481
389484 | no | Core Face: Exterior | 6.755 | 1930 | 1.351 | 389484

# IfcWindow: Entrance windows:Central, Entrance windows:Central:534478
In: RDC
Type - ParameterTakesPrecedence: no; Sizeable: no; Material: Stainless Steel, Brushed
Type - Analytical Properties - Analytic Construction: <None>; Define Thermal Properties by: Schematic Type
Type - Construction - Wall Closure: By host
Type - Dimensions - Height: 2340 mm; Width: 640 mm
Type - Identity Data - OmniClass Number: 23.30.20.00; OmniClass Title: Windows; Type Mark: 62; Type Name: Central
Type - Other - Category: Windows; Default Sill Height: 2 mm; Family Name: Entrance windows
Type - Pset_ProductRequirements - Category: Windows
Type - Pset_QuantityTakeOff - Reference: Central
Type - Pset_WindowCommon - IsExternal: no; Reference: Central
OverallHeight: 2340 mm; OverallWidth: 640 mm; Material: Stainless Steel, Brushed, Glass
Constraints - Level: Level: RDC; Sill Height: 2 mm
Dimensions - Area: 2.7635 m2; Volume: 0.0334496 m3
Identity Data - Comments: ThisIsExisting; Mark: 20
Other - Family: Entrance windows: Central; Family and Type: Entrance windows: Central; Head Height: 2342 mm; Host Id: Basic Wall: Wall-Int 100; Type: Entrance windows: Central; Type Id: Entrance windows: Central
Phasing - Phase Created: Existing
